VERSION 5.7 ;
BUSBITCHARS "[]" ;
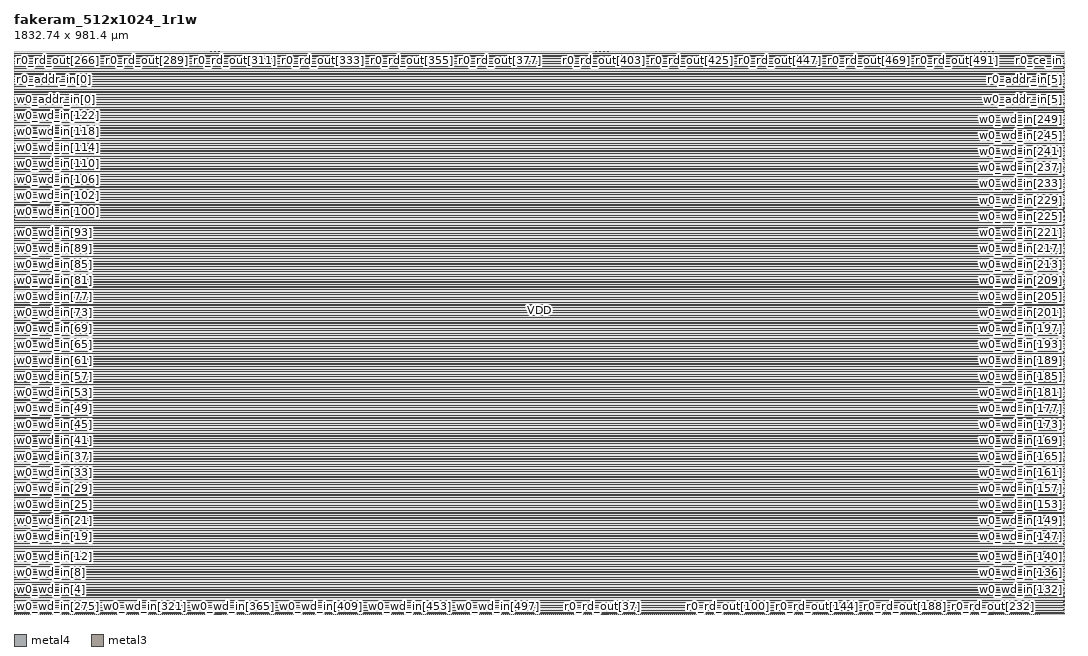
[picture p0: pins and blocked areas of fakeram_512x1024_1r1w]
MACRO fakeram_512x1024_1r1w
  FOREIGN fakeram_512x1024_1r1w 0 0 ;
  SYMMETRY X Y R90 ;
  SIZE 1832.740 BY 981.400 ;
  CLASS BLOCK ;
  PIN w0_wd_in[0]
    DIRECTION INPUT ;
    USE SIGNAL ;
    SHAPE ABUTMENT ;
    PORT
      LAYER metal4 ;
      RECT 0.000 1.645 0.210 1.715 ;
    END
  END w0_wd_in[0]
  PIN w0_wd_in[1]
    DIRECTION INPUT ;
    USE SIGNAL ;
    SHAPE ABUTMENT ;
    PORT
      LAYER metal4 ;
      RECT 0.000 8.645 0.210 8.715 ;
    END
  END w0_wd_in[1]
  PIN w0_wd_in[2]
    DIRECTION INPUT ;
    USE SIGNAL ;
    SHAPE ABUTMENT ;
    PORT
      LAYER metal4 ;
      RECT 0.000 15.645 0.210 15.715 ;
    END
  END w0_wd_in[2]
  PIN w0_wd_in[3]
    DIRECTION INPUT ;
    USE SIGNAL ;
    SHAPE ABUTMENT ;
    PORT
      LAYER metal4 ;
      RECT 0.000 22.645 0.210 22.715 ;
    END
  END w0_wd_in[3]
  PIN w0_wd_in[4]
    DIRECTION INPUT ;
    USE SIGNAL ;
    SHAPE ABUTMENT ;
    PORT
      LAYER metal4 ;
      RECT 0.000 29.645 0.210 29.715 ;
    END
  END w0_wd_in[4]
  PIN w0_wd_in[5]
    DIRECTION INPUT ;
    USE SIGNAL ;
    SHAPE ABUTMENT ;
    PORT
      LAYER metal4 ;
      RECT 0.000 36.645 0.210 36.715 ;
    END
  END w0_wd_in[5]
  PIN w0_wd_in[6]
    DIRECTION INPUT ;
    USE SIGNAL ;
    SHAPE ABUTMENT ;
    PORT
      LAYER metal4 ;
      RECT 0.000 43.645 0.210 43.715 ;
    END
  END w0_wd_in[6]
  PIN w0_wd_in[7]
    DIRECTION INPUT ;
    USE SIGNAL ;
    SHAPE ABUTMENT ;
    PORT
      LAYER metal4 ;
      RECT 0.000 50.645 0.210 50.715 ;
    END
  END w0_wd_in[7]
  PIN w0_wd_in[8]
    DIRECTION INPUT ;
    USE SIGNAL ;
    SHAPE ABUTMENT ;
    PORT
      LAYER metal4 ;
      RECT 0.000 57.645 0.210 57.715 ;
    END
  END w0_wd_in[8]
  PIN w0_wd_in[9]
    DIRECTION INPUT ;
    USE SIGNAL ;
    SHAPE ABUTMENT ;
    PORT
      LAYER metal4 ;
      RECT 0.000 64.645 0.210 64.715 ;
    END
  END w0_wd_in[9]
  PIN w0_wd_in[10]
    DIRECTION INPUT ;
    USE SIGNAL ;
    SHAPE ABUTMENT ;
    PORT
      LAYER metal4 ;
      RECT 0.000 71.645 0.210 71.715 ;
    END
  END w0_wd_in[10]
  PIN w0_wd_in[11]
    DIRECTION INPUT ;
    USE SIGNAL ;
    SHAPE ABUTMENT ;
    PORT
      LAYER metal4 ;
      RECT 0.000 78.645 0.210 78.715 ;
    END
  END w0_wd_in[11]
  PIN w0_wd_in[12]
    DIRECTION INPUT ;
    USE SIGNAL ;
    SHAPE ABUTMENT ;
    PORT
      LAYER metal4 ;
      RECT 0.000 85.645 0.210 85.715 ;
    END
  END w0_wd_in[12]
  PIN w0_wd_in[13]
    DIRECTION INPUT ;
    USE SIGNAL ;
    SHAPE ABUTMENT ;
    PORT
      LAYER metal4 ;
      RECT 0.000 92.645 0.210 92.715 ;
    END
  END w0_wd_in[13]
  PIN w0_wd_in[14]
    DIRECTION INPUT ;
    USE SIGNAL ;
    SHAPE ABUTMENT ;
    PORT
      LAYER metal4 ;
      RECT 0.000 99.645 0.210 99.715 ;
    END
  END w0_wd_in[14]
  PIN w0_wd_in[15]
    DIRECTION INPUT ;
    USE SIGNAL ;
    SHAPE ABUTMENT ;
    PORT
      LAYER metal4 ;
      RECT 0.000 106.645 0.210 106.715 ;
    END
  END w0_wd_in[15]
  PIN w0_wd_in[16]
    DIRECTION INPUT ;
    USE SIGNAL ;
    SHAPE ABUTMENT ;
    PORT
      LAYER metal4 ;
      RECT 0.000 113.645 0.210 113.715 ;
    END
  END w0_wd_in[16]
  PIN w0_wd_in[17]
    DIRECTION INPUT ;
    USE SIGNAL ;
    SHAPE ABUTMENT ;
    PORT
      LAYER metal4 ;
      RECT 0.000 120.645 0.210 120.715 ;
    END
  END w0_wd_in[17]
  PIN w0_wd_in[18]
    DIRECTION INPUT ;
    USE SIGNAL ;
    SHAPE ABUTMENT ;
    PORT
      LAYER metal4 ;
      RECT 0.000 127.645 0.210 127.715 ;
    END
  END w0_wd_in[18]
  PIN w0_wd_in[19]
    DIRECTION INPUT ;
    USE SIGNAL ;
    SHAPE ABUTMENT ;
    PORT
      LAYER metal4 ;
      RECT 0.000 134.645 0.210 134.715 ;
    END
  END w0_wd_in[19]
  PIN w0_wd_in[20]
    DIRECTION INPUT ;
    USE SIGNAL ;
    SHAPE ABUTMENT ;
    PORT
      LAYER metal4 ;
      RECT 0.000 141.645 0.210 141.715 ;
    END
  END w0_wd_in[20]
  PIN w0_wd_in[21]
    DIRECTION INPUT ;
    USE SIGNAL ;
    SHAPE ABUTMENT ;
    PORT
      LAYER metal4 ;
      RECT 0.000 148.645 0.210 148.715 ;
    END
  END w0_wd_in[21]
  PIN w0_wd_in[22]
    DIRECTION INPUT ;
    USE SIGNAL ;
    SHAPE ABUTMENT ;
    PORT
      LAYER metal4 ;
      RECT 0.000 155.645 0.210 155.715 ;
    END
  END w0_wd_in[22]
  PIN w0_wd_in[23]
    DIRECTION INPUT ;
    USE SIGNAL ;
    SHAPE ABUTMENT ;
    PORT
      LAYER metal4 ;
      RECT 0.000 162.645 0.210 162.715 ;
    END
  END w0_wd_in[23]
  PIN w0_wd_in[24]
    DIRECTION INPUT ;
    USE SIGNAL ;
    SHAPE ABUTMENT ;
    PORT
      LAYER metal4 ;
      RECT 0.000 169.645 0.210 169.715 ;
    END
  END w0_wd_in[24]
  PIN w0_wd_in[25]
    DIRECTION INPUT ;
    USE SIGNAL ;
    SHAPE ABUTMENT ;
    PORT
      LAYER metal4 ;
      RECT 0.000 176.645 0.210 176.715 ;
    END
  END w0_wd_in[25]
  PIN w0_wd_in[26]
    DIRECTION INPUT ;
    USE SIGNAL ;
    SHAPE ABUTMENT ;
    PORT
      LAYER metal4 ;
      RECT 0.000 183.645 0.210 183.715 ;
    END
  END w0_wd_in[26]
  PIN w0_wd_in[27]
    DIRECTION INPUT ;
    USE SIGNAL ;
    SHAPE ABUTMENT ;
    PORT
      LAYER metal4 ;
      RECT 0.000 190.645 0.210 190.715 ;
    END
  END w0_wd_in[27]
  PIN w0_wd_in[28]
    DIRECTION INPUT ;
    USE SIGNAL ;
    SHAPE ABUTMENT ;
    PORT
      LAYER metal4 ;
      RECT 0.000 197.645 0.210 197.715 ;
    END
  END w0_wd_in[28]
  PIN w0_wd_in[29]
    DIRECTION INPUT ;
    USE SIGNAL ;
    SHAPE ABUTMENT ;
    PORT
      LAYER metal4 ;
      RECT 0.000 204.645 0.210 204.715 ;
    END
  END w0_wd_in[29]
  PIN w0_wd_in[30]
    DIRECTION INPUT ;
    USE SIGNAL ;
    SHAPE ABUTMENT ;
    PORT
      LAYER metal4 ;
      RECT 0.000 211.645 0.210 211.715 ;
    END
  END w0_wd_in[30]
  PIN w0_wd_in[31]
    DIRECTION INPUT ;
    USE SIGNAL ;
    SHAPE ABUTMENT ;
    PORT
      LAYER metal4 ;
      RECT 0.000 218.645 0.210 218.715 ;
    END
  END w0_wd_in[31]
  PIN w0_wd_in[32]
    DIRECTION INPUT ;
    USE SIGNAL ;
    SHAPE ABUTMENT ;
    PORT
      LAYER metal4 ;
      RECT 0.000 225.645 0.210 225.715 ;
    END
  END w0_wd_in[32]
  PIN w0_wd_in[33]
    DIRECTION INPUT ;
    USE SIGNAL ;
    SHAPE ABUTMENT ;
    PORT
      LAYER metal4 ;
      RECT 0.000 232.645 0.210 232.715 ;
    END
  END w0_wd_in[33]
  PIN w0_wd_in[34]
    DIRECTION INPUT ;
    USE SIGNAL ;
    SHAPE ABUTMENT ;
    PORT
      LAYER metal4 ;
      RECT 0.000 239.645 0.210 239.715 ;
    END
  END w0_wd_in[34]
  PIN w0_wd_in[35]
    DIRECTION INPUT ;
    USE SIGNAL ;
    SHAPE ABUTMENT ;
    PORT
      LAYER metal4 ;
      RECT 0.000 246.645 0.210 246.715 ;
    END
  END w0_wd_in[35]
  PIN w0_wd_in[36]
    DIRECTION INPUT ;
    USE SIGNAL ;
    SHAPE ABUTMENT ;
    PORT
      LAYER metal4 ;
      RECT 0.000 253.645 0.210 253.715 ;
    END
  END w0_wd_in[36]
  PIN w0_wd_in[37]
    DIRECTION INPUT ;
    USE SIGNAL ;
    SHAPE ABUTMENT ;
    PORT
      LAYER metal4 ;
      RECT 0.000 260.645 0.210 260.715 ;
    END
  END w0_wd_in[37]
  PIN w0_wd_in[38]
    DIRECTION INPUT ;
    USE SIGNAL ;
    SHAPE ABUTMENT ;
    PORT
      LAYER metal4 ;
      RECT 0.000 267.645 0.210 267.715 ;
    END
  END w0_wd_in[38]
  PIN w0_wd_in[39]
    DIRECTION INPUT ;
    USE SIGNAL ;
    SHAPE ABUTMENT ;
    PORT
      LAYER metal4 ;
      RECT 0.000 274.645 0.210 274.715 ;
    END
  END w0_wd_in[39]
  PIN w0_wd_in[40]
    DIRECTION INPUT ;
    USE SIGNAL ;
    SHAPE ABUTMENT ;
    PORT
      LAYER metal4 ;
      RECT 0.000 281.645 0.210 281.715 ;
    END
  END w0_wd_in[40]
  PIN w0_wd_in[41]
    DIRECTION INPUT ;
    USE SIGNAL ;
    SHAPE ABUTMENT ;
    PORT
      LAYER metal4 ;
      RECT 0.000 288.645 0.210 288.715 ;
    END
  END w0_wd_in[41]
  PIN w0_wd_in[42]
    DIRECTION INPUT ;
    USE SIGNAL ;
    SHAPE ABUTMENT ;
    PORT
      LAYER metal4 ;
      RECT 0.000 295.645 0.210 295.715 ;
    END
  END w0_wd_in[42]
  PIN w0_wd_in[43]
    DIRECTION INPUT ;
    USE SIGNAL ;
    SHAPE ABUTMENT ;
    PORT
      LAYER metal4 ;
      RECT 0.000 302.645 0.210 302.715 ;
    END
  END w0_wd_in[43]
  PIN w0_wd_in[44]
    DIRECTION INPUT ;
    USE SIGNAL ;
    SHAPE ABUTMENT ;
    PORT
      LAYER metal4 ;
      RECT 0.000 309.645 0.210 309.715 ;
    END
  END w0_wd_in[44]
  PIN w0_wd_in[45]
    DIRECTION INPUT ;
    USE SIGNAL ;
    SHAPE ABUTMENT ;
    PORT
      LAYER metal4 ;
      RECT 0.000 316.645 0.210 316.715 ;
    END
  END w0_wd_in[45]
  PIN w0_wd_in[46]
    DIRECTION INPUT ;
    USE SIGNAL ;
    SHAPE ABUTMENT ;
    PORT
      LAYER metal4 ;
      RECT 0.000 323.645 0.210 323.715 ;
    END
  END w0_wd_in[46]
  PIN w0_wd_in[47]
    DIRECTION INPUT ;
    USE SIGNAL ;
    SHAPE ABUTMENT ;
    PORT
      LAYER metal4 ;
      RECT 0.000 330.645 0.210 330.715 ;
    END
  END w0_wd_in[47]
  PIN w0_wd_in[48]
    DIRECTION INPUT ;
    USE SIGNAL ;
    SHAPE ABUTMENT ;
    PORT
      LAYER metal4 ;
      RECT 0.000 337.645 0.210 337.715 ;
    END
  END w0_wd_in[48]
  PIN w0_wd_in[49]
    DIRECTION INPUT ;
    USE SIGNAL ;
    SHAPE ABUTMENT ;
    PORT
      LAYER metal4 ;
      RECT 0.000 344.645 0.210 344.715 ;
    END
  END w0_wd_in[49]
  PIN w0_wd_in[50]
    DIRECTION INPUT ;
    USE SIGNAL ;
    SHAPE ABUTMENT ;
    PORT
      LAYER metal4 ;
      RECT 0.000 351.645 0.210 351.715 ;
    END
  END w0_wd_in[50]
  PIN w0_wd_in[51]
    DIRECTION INPUT ;
    USE SIGNAL ;
    SHAPE ABUTMENT ;
    PORT
      LAYER metal4 ;
      RECT 0.000 358.645 0.210 358.715 ;
    END
  END w0_wd_in[51]
  PIN w0_wd_in[52]
    DIRECTION INPUT ;
    USE SIGNAL ;
    SHAPE ABUTMENT ;
    PORT
      LAYER metal4 ;
      RECT 0.000 365.645 0.210 365.715 ;
    END
  END w0_wd_in[52]
  PIN w0_wd_in[53]
    DIRECTION INPUT ;
    USE SIGNAL ;
    SHAPE ABUTMENT ;
    PORT
      LAYER metal4 ;
      RECT 0.000 372.645 0.210 372.715 ;
    END
  END w0_wd_in[53]
  PIN w0_wd_in[54]
    DIRECTION INPUT ;
    USE SIGNAL ;
    SHAPE ABUTMENT ;
    PORT
      LAYER metal4 ;
      RECT 0.000 379.645 0.210 379.715 ;
    END
  END w0_wd_in[54]
  PIN w0_wd_in[55]
    DIRECTION INPUT ;
    USE SIGNAL ;
    SHAPE ABUTMENT ;
    PORT
      LAYER metal4 ;
      RECT 0.000 386.645 0.210 386.715 ;
    END
  END w0_wd_in[55]
  PIN w0_wd_in[56]
    DIRECTION INPUT ;
    USE SIGNAL ;
    SHAPE ABUTMENT ;
    PORT
      LAYER metal4 ;
      RECT 0.000 393.645 0.210 393.715 ;
    END
  END w0_wd_in[56]
  PIN w0_wd_in[57]
    DIRECTION INPUT ;
    USE SIGNAL ;
    SHAPE ABUTMENT ;
    PORT
      LAYER metal4 ;
      RECT 0.000 400.645 0.210 400.715 ;
    END
  END w0_wd_in[57]
  PIN w0_wd_in[58]
    DIRECTION INPUT ;
    USE SIGNAL ;
    SHAPE ABUTMENT ;
    PORT
      LAYER metal4 ;
      RECT 0.000 407.645 0.210 407.715 ;
    END
  END w0_wd_in[58]
  PIN w0_wd_in[59]
    DIRECTION INPUT ;
    USE SIGNAL ;
    SHAPE ABUTMENT ;
    PORT
      LAYER metal4 ;
      RECT 0.000 414.645 0.210 414.715 ;
    END
  END w0_wd_in[59]
  PIN w0_wd_in[60]
    DIRECTION INPUT ;
    USE SIGNAL ;
    SHAPE ABUTMENT ;
    PORT
      LAYER metal4 ;
      RECT 0.000 421.645 0.210 421.715 ;
    END
  END w0_wd_in[60]
  PIN w0_wd_in[61]
    DIRECTION INPUT ;
    USE SIGNAL ;
    SHAPE ABUTMENT ;
    PORT
      LAYER metal4 ;
      RECT 0.000 428.645 0.210 428.715 ;
    END
  END w0_wd_in[61]
  PIN w0_wd_in[62]
    DIRECTION INPUT ;
    USE SIGNAL ;
    SHAPE ABUTMENT ;
    PORT
      LAYER metal4 ;
      RECT 0.000 435.645 0.210 435.715 ;
    END
  END w0_wd_in[62]
  PIN w0_wd_in[63]
    DIRECTION INPUT ;
    USE SIGNAL ;
    SHAPE ABUTMENT ;
    PORT
      LAYER metal4 ;
      RECT 0.000 442.645 0.210 442.715 ;
    END
  END w0_wd_in[63]
  PIN w0_wd_in[64]
    DIRECTION INPUT ;
    USE SIGNAL ;
    SHAPE ABUTMENT ;
    PORT
      LAYER metal4 ;
      RECT 0.000 449.645 0.210 449.715 ;
    END
  END w0_wd_in[64]
  PIN w0_wd_in[65]
    DIRECTION INPUT ;
    USE SIGNAL ;
    SHAPE ABUTMENT ;
    PORT
      LAYER metal4 ;
      RECT 0.000 456.645 0.210 456.715 ;
    END
  END w0_wd_in[65]
  PIN w0_wd_in[66]
    DIRECTION INPUT ;
    USE SIGNAL ;
    SHAPE ABUTMENT ;
    PORT
      LAYER metal4 ;
      RECT 0.000 463.645 0.210 463.715 ;
    END
  END w0_wd_in[66]
  PIN w0_wd_in[67]
    DIRECTION INPUT ;
    USE SIGNAL ;
    SHAPE ABUTMENT ;
    PORT
      LAYER metal4 ;
      RECT 0.000 470.645 0.210 470.715 ;
    END
  END w0_wd_in[67]
  PIN w0_wd_in[68]
    DIRECTION INPUT ;
    USE SIGNAL ;
    SHAPE ABUTMENT ;
    PORT
      LAYER metal4 ;
      RECT 0.000 477.645 0.210 477.715 ;
    END
  END w0_wd_in[68]
  PIN w0_wd_in[69]
    DIRECTION INPUT ;
    USE SIGNAL ;
    SHAPE ABUTMENT ;
    PORT
      LAYER metal4 ;
      RECT 0.000 484.645 0.210 484.715 ;
    END
  END w0_wd_in[69]
  PIN w0_wd_in[70]
    DIRECTION INPUT ;
    USE SIGNAL ;
    SHAPE ABUTMENT ;
    PORT
      LAYER metal4 ;
      RECT 0.000 491.645 0.210 491.715 ;
    END
  END w0_wd_in[70]
  PIN w0_wd_in[71]
    DIRECTION INPUT ;
    USE SIGNAL ;
    SHAPE ABUTMENT ;
    PORT
      LAYER metal4 ;
      RECT 0.000 498.645 0.210 498.715 ;
    END
  END w0_wd_in[71]
  PIN w0_wd_in[72]
    DIRECTION INPUT ;
    USE SIGNAL ;
    SHAPE ABUTMENT ;
    PORT
      LAYER metal4 ;
      RECT 0.000 505.645 0.210 505.715 ;
    END
  END w0_wd_in[72]
  PIN w0_wd_in[73]
    DIRECTION INPUT ;
    USE SIGNAL ;
    SHAPE ABUTMENT ;
    PORT
      LAYER metal4 ;
      RECT 0.000 512.645 0.210 512.715 ;
    END
  END w0_wd_in[73]
  PIN w0_wd_in[74]
    DIRECTION INPUT ;
    USE SIGNAL ;
    SHAPE ABUTMENT ;
    PORT
      LAYER metal4 ;
      RECT 0.000 519.645 0.210 519.715 ;
    END
  END w0_wd_in[74]
  PIN w0_wd_in[75]
    DIRECTION INPUT ;
    USE SIGNAL ;
    SHAPE ABUTMENT ;
    PORT
      LAYER metal4 ;
      RECT 0.000 526.645 0.210 526.715 ;
    END
  END w0_wd_in[75]
  PIN w0_wd_in[76]
    DIRECTION INPUT ;
    USE SIGNAL ;
    SHAPE ABUTMENT ;
    PORT
      LAYER metal4 ;
      RECT 0.000 533.645 0.210 533.715 ;
    END
  END w0_wd_in[76]
  PIN w0_wd_in[77]
    DIRECTION INPUT ;
    USE SIGNAL ;
    SHAPE ABUTMENT ;
    PORT
      LAYER metal4 ;
      RECT 0.000 540.645 0.210 540.715 ;
    END
  END w0_wd_in[77]
  PIN w0_wd_in[78]
    DIRECTION INPUT ;
    USE SIGNAL ;
    SHAPE ABUTMENT ;
    PORT
      LAYER metal4 ;
      RECT 0.000 547.645 0.210 547.715 ;
    END
  END w0_wd_in[78]
  PIN w0_wd_in[79]
    DIRECTION INPUT ;
    USE SIGNAL ;
    SHAPE ABUTMENT ;
    PORT
      LAYER metal4 ;
      RECT 0.000 554.645 0.210 554.715 ;
    END
  END w0_wd_in[79]
  PIN w0_wd_in[80]
    DIRECTION INPUT ;
    USE SIGNAL ;
    SHAPE ABUTMENT ;
    PORT
      LAYER metal4 ;
      RECT 0.000 561.645 0.210 561.715 ;
    END
  END w0_wd_in[80]
  PIN w0_wd_in[81]
    DIRECTION INPUT ;
    USE SIGNAL ;
    SHAPE ABUTMENT ;
    PORT
      LAYER metal4 ;
      RECT 0.000 568.645 0.210 568.715 ;
    END
  END w0_wd_in[81]
  PIN w0_wd_in[82]
    DIRECTION INPUT ;
    USE SIGNAL ;
    SHAPE ABUTMENT ;
    PORT
      LAYER metal4 ;
      RECT 0.000 575.645 0.210 575.715 ;
    END
  END w0_wd_in[82]
  PIN w0_wd_in[83]
    DIRECTION INPUT ;
    USE SIGNAL ;
    SHAPE ABUTMENT ;
    PORT
      LAYER metal4 ;
      RECT 0.000 582.645 0.210 582.715 ;
    END
  END w0_wd_in[83]
  PIN w0_wd_in[84]
    DIRECTION INPUT ;
    USE SIGNAL ;
    SHAPE ABUTMENT ;
    PORT
      LAYER metal4 ;
      RECT 0.000 589.645 0.210 589.715 ;
    END
  END w0_wd_in[84]
  PIN w0_wd_in[85]
    DIRECTION INPUT ;
    USE SIGNAL ;
    SHAPE ABUTMENT ;
    PORT
      LAYER metal4 ;
      RECT 0.000 596.645 0.210 596.715 ;
    END
  END w0_wd_in[85]
  PIN w0_wd_in[86]
    DIRECTION INPUT ;
    USE SIGNAL ;
    SHAPE ABUTMENT ;
    PORT
      LAYER metal4 ;
      RECT 0.000 603.645 0.210 603.715 ;
    END
  END w0_wd_in[86]
  PIN w0_wd_in[87]
    DIRECTION INPUT ;
    USE SIGNAL ;
    SHAPE ABUTMENT ;
    PORT
      LAYER metal4 ;
      RECT 0.000 610.645 0.210 610.715 ;
    END
  END w0_wd_in[87]
  PIN w0_wd_in[88]
    DIRECTION INPUT ;
    USE SIGNAL ;
    SHAPE ABUTMENT ;
    PORT
      LAYER metal4 ;
      RECT 0.000 617.645 0.210 617.715 ;
    END
  END w0_wd_in[88]
  PIN w0_wd_in[89]
    DIRECTION INPUT ;
    USE SIGNAL ;
    SHAPE ABUTMENT ;
    PORT
      LAYER metal4 ;
      RECT 0.000 624.645 0.210 624.715 ;
    END
  END w0_wd_in[89]
  PIN w0_wd_in[90]
    DIRECTION INPUT ;
    USE SIGNAL ;
    SHAPE ABUTMENT ;
    PORT
      LAYER metal4 ;
      RECT 0.000 631.645 0.210 631.715 ;
    END
  END w0_wd_in[90]
  PIN w0_wd_in[91]
    DIRECTION INPUT ;
    USE SIGNAL ;
    SHAPE ABUTMENT ;
    PORT
      LAYER metal4 ;
      RECT 0.000 638.645 0.210 638.715 ;
    END
  END w0_wd_in[91]
  PIN w0_wd_in[92]
    DIRECTION INPUT ;
    USE SIGNAL ;
    SHAPE ABUTMENT ;
    PORT
      LAYER metal4 ;
      RECT 0.000 645.645 0.210 645.715 ;
    END
  END w0_wd_in[92]
  PIN w0_wd_in[93]
    DIRECTION INPUT ;
    USE SIGNAL ;
    SHAPE ABUTMENT ;
    PORT
      LAYER metal4 ;
      RECT 0.000 652.645 0.210 652.715 ;
    END
  END w0_wd_in[93]
  PIN w0_wd_in[94]
    DIRECTION INPUT ;
    USE SIGNAL ;
    SHAPE ABUTMENT ;
    PORT
      LAYER metal4 ;
      RECT 0.000 659.645 0.210 659.715 ;
    END
  END w0_wd_in[94]
  PIN w0_wd_in[95]
    DIRECTION INPUT ;
    USE SIGNAL ;
    SHAPE ABUTMENT ;
    PORT
      LAYER metal4 ;
      RECT 0.000 666.645 0.210 666.715 ;
    END
  END w0_wd_in[95]
  PIN w0_wd_in[96]
    DIRECTION INPUT ;
    USE SIGNAL ;
    SHAPE ABUTMENT ;
    PORT
      LAYER metal4 ;
      RECT 0.000 673.645 0.210 673.715 ;
    END
  END w0_wd_in[96]
  PIN w0_wd_in[97]
    DIRECTION INPUT ;
    USE SIGNAL ;
    SHAPE ABUTMENT ;
    PORT
      LAYER metal4 ;
      RECT 0.000 680.645 0.210 680.715 ;
    END
  END w0_wd_in[97]
  PIN w0_wd_in[98]
    DIRECTION INPUT ;
    USE SIGNAL ;
    SHAPE ABUTMENT ;
    PORT
      LAYER metal4 ;
      RECT 0.000 687.645 0.210 687.715 ;
    END
  END w0_wd_in[98]
  PIN w0_wd_in[99]
    DIRECTION INPUT ;
    USE SIGNAL ;
    SHAPE ABUTMENT ;
    PORT
      LAYER metal4 ;
      RECT 0.000 694.645 0.210 694.715 ;
    END
  END w0_wd_in[99]
  PIN w0_wd_in[100]
    DIRECTION INPUT ;
    USE SIGNAL ;
    SHAPE ABUTMENT ;
    PORT
      LAYER metal4 ;
      RECT 0.000 701.645 0.210 701.715 ;
    END
  END w0_wd_in[100]
  PIN w0_wd_in[101]
    DIRECTION INPUT ;
    USE SIGNAL ;
    SHAPE ABUTMENT ;
    PORT
      LAYER metal4 ;
      RECT 0.000 708.645 0.210 708.715 ;
    END
  END w0_wd_in[101]
  PIN w0_wd_in[102]
    DIRECTION INPUT ;
    USE SIGNAL ;
    SHAPE ABUTMENT ;
    PORT
      LAYER metal4 ;
      RECT 0.000 715.645 0.210 715.715 ;
    END
  END w0_wd_in[102]
  PIN w0_wd_in[103]
    DIRECTION INPUT ;
    USE SIGNAL ;
    SHAPE ABUTMENT ;
    PORT
      LAYER metal4 ;
      RECT 0.000 722.645 0.210 722.715 ;
    END
  END w0_wd_in[103]
  PIN w0_wd_in[104]
    DIRECTION INPUT ;
    USE SIGNAL ;
    SHAPE ABUTMENT ;
    PORT
      LAYER metal4 ;
      RECT 0.000 729.645 0.210 729.715 ;
    END
  END w0_wd_in[104]
  PIN w0_wd_in[105]
    DIRECTION INPUT ;
    USE SIGNAL ;
    SHAPE ABUTMENT ;
    PORT
      LAYER metal4 ;
      RECT 0.000 736.645 0.210 736.715 ;
    END
  END w0_wd_in[105]
  PIN w0_wd_in[106]
    DIRECTION INPUT ;
    USE SIGNAL ;
    SHAPE ABUTMENT ;
    PORT
      LAYER metal4 ;
      RECT 0.000 743.645 0.210 743.715 ;
    END
  END w0_wd_in[106]
  PIN w0_wd_in[107]
    DIRECTION INPUT ;
    USE SIGNAL ;
    SHAPE ABUTMENT ;
    PORT
      LAYER metal4 ;
      RECT 0.000 750.645 0.210 750.715 ;
    END
  END w0_wd_in[107]
  PIN w0_wd_in[108]
    DIRECTION INPUT ;
    USE SIGNAL ;
    SHAPE ABUTMENT ;
    PORT
      LAYER metal4 ;
      RECT 0.000 757.645 0.210 757.715 ;
    END
  END w0_wd_in[108]
  PIN w0_wd_in[109]
    DIRECTION INPUT ;
    USE SIGNAL ;
    SHAPE ABUTMENT ;
    PORT
      LAYER metal4 ;
      RECT 0.000 764.645 0.210 764.715 ;
    END
  END w0_wd_in[109]
  PIN w0_wd_in[110]
    DIRECTION INPUT ;
    USE SIGNAL ;
    SHAPE ABUTMENT ;
    PORT
      LAYER metal4 ;
      RECT 0.000 771.645 0.210 771.715 ;
    END
  END w0_wd_in[110]
  PIN w0_wd_in[111]
    DIRECTION INPUT ;
    USE SIGNAL ;
    SHAPE ABUTMENT ;
    PORT
      LAYER metal4 ;
      RECT 0.000 778.645 0.210 778.715 ;
    END
  END w0_wd_in[111]
  PIN w0_wd_in[112]
    DIRECTION INPUT ;
    USE SIGNAL ;
    SHAPE ABUTMENT ;
    PORT
      LAYER metal4 ;
      RECT 0.000 785.645 0.210 785.715 ;
    END
  END w0_wd_in[112]
  PIN w0_wd_in[113]
    DIRECTION INPUT ;
    USE SIGNAL ;
    SHAPE ABUTMENT ;
    PORT
      LAYER metal4 ;
      RECT 0.000 792.645 0.210 792.715 ;
    END
  END w0_wd_in[113]
  PIN w0_wd_in[114]
    DIRECTION INPUT ;
    USE SIGNAL ;
    SHAPE ABUTMENT ;
    PORT
      LAYER metal4 ;
      RECT 0.000 799.645 0.210 799.715 ;
    END
  END w0_wd_in[114]
  PIN w0_wd_in[115]
    DIRECTION INPUT ;
    USE SIGNAL ;
    SHAPE ABUTMENT ;
    PORT
      LAYER metal4 ;
      RECT 0.000 806.645 0.210 806.715 ;
    END
  END w0_wd_in[115]
  PIN w0_wd_in[116]
    DIRECTION INPUT ;
    USE SIGNAL ;
    SHAPE ABUTMENT ;
    PORT
      LAYER metal4 ;
      RECT 0.000 813.645 0.210 813.715 ;
    END
  END w0_wd_in[116]
  PIN w0_wd_in[117]
    DIRECTION INPUT ;
    USE SIGNAL ;
    SHAPE ABUTMENT ;
    PORT
      LAYER metal4 ;
      RECT 0.000 820.645 0.210 820.715 ;
    END
  END w0_wd_in[117]
  PIN w0_wd_in[118]
    DIRECTION INPUT ;
    USE SIGNAL ;
    SHAPE ABUTMENT ;
    PORT
      LAYER metal4 ;
      RECT 0.000 827.645 0.210 827.715 ;
    END
  END w0_wd_in[118]
  PIN w0_wd_in[119]
    DIRECTION INPUT ;
    USE SIGNAL ;
    SHAPE ABUTMENT ;
    PORT
      LAYER metal4 ;
      RECT 0.000 834.645 0.210 834.715 ;
    END
  END w0_wd_in[119]
  PIN w0_wd_in[120]
    DIRECTION INPUT ;
    USE SIGNAL ;
    SHAPE ABUTMENT ;
    PORT
      LAYER metal4 ;
      RECT 0.000 841.645 0.210 841.715 ;
    END
  END w0_wd_in[120]
  PIN w0_wd_in[121]
    DIRECTION INPUT ;
    USE SIGNAL ;
    SHAPE ABUTMENT ;
    PORT
      LAYER metal4 ;
      RECT 0.000 848.645 0.210 848.715 ;
    END
  END w0_wd_in[121]
  PIN w0_wd_in[122]
    DIRECTION INPUT ;
    USE SIGNAL ;
    SHAPE ABUTMENT ;
    PORT
      LAYER metal4 ;
      RECT 0.000 855.645 0.210 855.715 ;
    END
  END w0_wd_in[122]
  PIN w0_wd_in[123]
    DIRECTION INPUT ;
    USE SIGNAL ;
    SHAPE ABUTMENT ;
    PORT
      LAYER metal4 ;
      RECT 0.000 862.645 0.210 862.715 ;
    END
  END w0_wd_in[123]
  PIN w0_wd_in[124]
    DIRECTION INPUT ;
    USE SIGNAL ;
    SHAPE ABUTMENT ;
    PORT
      LAYER metal4 ;
      RECT 0.000 869.645 0.210 869.715 ;
    END
  END w0_wd_in[124]
  PIN w0_wd_in[125]
    DIRECTION INPUT ;
    USE SIGNAL ;
    SHAPE ABUTMENT ;
    PORT
      LAYER metal4 ;
      RECT 0.000 876.645 0.210 876.715 ;
    END
  END w0_wd_in[125]
  PIN w0_wd_in[126]
    DIRECTION INPUT ;
    USE SIGNAL ;
    SHAPE ABUTMENT ;
    PORT
      LAYER metal4 ;
      RECT 0.000 883.645 0.210 883.715 ;
    END
  END w0_wd_in[126]
  PIN w0_wd_in[127]
    DIRECTION INPUT ;
    USE SIGNAL ;
    SHAPE ABUTMENT ;
    PORT
      LAYER metal4 ;
      RECT 0.000 890.645 0.210 890.715 ;
    END
  END w0_wd_in[127]
  PIN w0_wd_in[128]
    DIRECTION INPUT ;
    USE SIGNAL ;
    SHAPE ABUTMENT ;
    PORT
      LAYER metal4 ;
      RECT 1832.530 1.645 1832.740 1.715 ;
    END
  END w0_wd_in[128]
  PIN w0_wd_in[129]
    DIRECTION INPUT ;
    USE SIGNAL ;
    SHAPE ABUTMENT ;
    PORT
      LAYER metal4 ;
      RECT 1832.530 8.645 1832.740 8.715 ;
    END
  END w0_wd_in[129]
  PIN w0_wd_in[130]
    DIRECTION INPUT ;
    USE SIGNAL ;
    SHAPE ABUTMENT ;
    PORT
      LAYER metal4 ;
      RECT 1832.530 15.645 1832.740 15.715 ;
    END
  END w0_wd_in[130]
  PIN w0_wd_in[131]
    DIRECTION INPUT ;
    USE SIGNAL ;
    SHAPE ABUTMENT ;
    PORT
      LAYER metal4 ;
      RECT 1832.530 22.645 1832.740 22.715 ;
    END
  END w0_wd_in[131]
  PIN w0_wd_in[132]
    DIRECTION INPUT ;
    USE SIGNAL ;
    SHAPE ABUTMENT ;
    PORT
      LAYER metal4 ;
      RECT 1832.530 29.645 1832.740 29.715 ;
    END
  END w0_wd_in[132]
  PIN w0_wd_in[133]
    DIRECTION INPUT ;
    USE SIGNAL ;
    SHAPE ABUTMENT ;
    PORT
      LAYER metal4 ;
      RECT 1832.530 36.645 1832.740 36.715 ;
    END
  END w0_wd_in[133]
  PIN w0_wd_in[134]
    DIRECTION INPUT ;
    USE SIGNAL ;
    SHAPE ABUTMENT ;
    PORT
      LAYER metal4 ;
      RECT 1832.530 43.645 1832.740 43.715 ;
    END
  END w0_wd_in[134]
  PIN w0_wd_in[135]
    DIRECTION INPUT ;
    USE SIGNAL ;
    SHAPE ABUTMENT ;
    PORT
      LAYER metal4 ;
      RECT 1832.530 50.645 1832.740 50.715 ;
    END
  END w0_wd_in[135]
  PIN w0_wd_in[136]
    DIRECTION INPUT ;
    USE SIGNAL ;
    SHAPE ABUTMENT ;
    PORT
      LAYER metal4 ;
      RECT 1832.530 57.645 1832.740 57.715 ;
    END
  END w0_wd_in[136]
  PIN w0_wd_in[137]
    DIRECTION INPUT ;
    USE SIGNAL ;
    SHAPE ABUTMENT ;
    PORT
      LAYER metal4 ;
      RECT 1832.530 64.645 1832.740 64.715 ;
    END
  END w0_wd_in[137]
  PIN w0_wd_in[138]
    DIRECTION INPUT ;
    USE SIGNAL ;
    SHAPE ABUTMENT ;
    PORT
      LAYER metal4 ;
      RECT 1832.530 71.645 1832.740 71.715 ;
    END
  END w0_wd_in[138]
  PIN w0_wd_in[139]
    DIRECTION INPUT ;
    USE SIGNAL ;
    SHAPE ABUTMENT ;
    PORT
      LAYER metal4 ;
      RECT 1832.530 78.645 1832.740 78.715 ;
    END
  END w0_wd_in[139]
  PIN w0_wd_in[140]
    DIRECTION INPUT ;
    USE SIGNAL ;
    SHAPE ABUTMENT ;
    PORT
      LAYER metal4 ;
      RECT 1832.530 85.645 1832.740 85.715 ;
    END
  END w0_wd_in[140]
  PIN w0_wd_in[141]
    DIRECTION INPUT ;
    USE SIGNAL ;
    SHAPE ABUTMENT ;
    PORT
      LAYER metal4 ;
      RECT 1832.530 92.645 1832.740 92.715 ;
    END
  END w0_wd_in[141]
  PIN w0_wd_in[142]
    DIRECTION INPUT ;
    USE SIGNAL ;
    SHAPE ABUTMENT ;
    PORT
      LAYER metal4 ;
      RECT 1832.530 99.645 1832.740 99.715 ;
    END
  END w0_wd_in[142]
  PIN w0_wd_in[143]
    DIRECTION INPUT ;
    USE SIGNAL ;
    SHAPE ABUTMENT ;
    PORT
      LAYER metal4 ;
      RECT 1832.530 106.645 1832.740 106.715 ;
    END
  END w0_wd_in[143]
  PIN w0_wd_in[144]
    DIRECTION INPUT ;
    USE SIGNAL ;
    SHAPE ABUTMENT ;
    PORT
      LAYER metal4 ;
      RECT 1832.530 113.645 1832.740 113.715 ;
    END
  END w0_wd_in[144]
  PIN w0_wd_in[145]
    DIRECTION INPUT ;
    USE SIGNAL ;
    SHAPE ABUTMENT ;
    PORT
      LAYER metal4 ;
      RECT 1832.530 120.645 1832.740 120.715 ;
    END
  END w0_wd_in[145]
  PIN w0_wd_in[146]
    DIRECTION INPUT ;
    USE SIGNAL ;
    SHAPE ABUTMENT ;
    PORT
      LAYER metal4 ;
      RECT 1832.530 127.645 1832.740 127.715 ;
    END
  END w0_wd_in[146]
  PIN w0_wd_in[147]
    DIRECTION INPUT ;
    USE SIGNAL ;
    SHAPE ABUTMENT ;
    PORT
      LAYER metal4 ;
      RECT 1832.530 134.645 1832.740 134.715 ;
    END
  END w0_wd_in[147]
  PIN w0_wd_in[148]
    DIRECTION INPUT ;
    USE SIGNAL ;
    SHAPE ABUTMENT ;
    PORT
      LAYER metal4 ;
      RECT 1832.530 141.645 1832.740 141.715 ;
    END
  END w0_wd_in[148]
  PIN w0_wd_in[149]
    DIRECTION INPUT ;
    USE SIGNAL ;
    SHAPE ABUTMENT ;
    PORT
      LAYER metal4 ;
      RECT 1832.530 148.645 1832.740 148.715 ;
    END
  END w0_wd_in[149]
  PIN w0_wd_in[150]
    DIRECTION INPUT ;
    USE SIGNAL ;
    SHAPE ABUTMENT ;
    PORT
      LAYER metal4 ;
      RECT 1832.530 155.645 1832.740 155.715 ;
    END
  END w0_wd_in[150]
  PIN w0_wd_in[151]
    DIRECTION INPUT ;
    USE SIGNAL ;
    SHAPE ABUTMENT ;
    PORT
      LAYER metal4 ;
      RECT 1832.530 162.645 1832.740 162.715 ;
    END
  END w0_wd_in[151]
  PIN w0_wd_in[152]
    DIRECTION INPUT ;
    USE SIGNAL ;
    SHAPE ABUTMENT ;
    PORT
      LAYER metal4 ;
      RECT 1832.530 169.645 1832.740 169.715 ;
    END
  END w0_wd_in[152]
  PIN w0_wd_in[153]
    DIRECTION INPUT ;
    USE SIGNAL ;
    SHAPE ABUTMENT ;
    PORT
      LAYER metal4 ;
      RECT 1832.530 176.645 1832.740 176.715 ;
    END
  END w0_wd_in[153]
  PIN w0_wd_in[154]
    DIRECTION INPUT ;
    USE SIGNAL ;
    SHAPE ABUTMENT ;
    PORT
      LAYER metal4 ;
      RECT 1832.530 183.645 1832.740 183.715 ;
    END
  END w0_wd_in[154]
  PIN w0_wd_in[155]
    DIRECTION INPUT ;
    USE SIGNAL ;
    SHAPE ABUTMENT ;
    PORT
      LAYER metal4 ;
      RECT 1832.530 190.645 1832.740 190.715 ;
    END
  END w0_wd_in[155]
  PIN w0_wd_in[156]
    DIRECTION INPUT ;
    USE SIGNAL ;
    SHAPE ABUTMENT ;
    PORT
      LAYER metal4 ;
      RECT 1832.530 197.645 1832.740 197.715 ;
    END
  END w0_wd_in[156]
  PIN w0_wd_in[157]
    DIRECTION INPUT ;
    USE SIGNAL ;
    SHAPE ABUTMENT ;
    PORT
      LAYER metal4 ;
      RECT 1832.530 204.645 1832.740 204.715 ;
    END
  END w0_wd_in[157]
  PIN w0_wd_in[158]
    DIRECTION INPUT ;
    USE SIGNAL ;
    SHAPE ABUTMENT ;
    PORT
      LAYER metal4 ;
      RECT 1832.530 211.645 1832.740 211.715 ;
    END
  END w0_wd_in[158]
  PIN w0_wd_in[159]
    DIRECTION INPUT ;
    USE SIGNAL ;
    SHAPE ABUTMENT ;
    PORT
      LAYER metal4 ;
      RECT 1832.530 218.645 1832.740 218.715 ;
    END
  END w0_wd_in[159]
  PIN w0_wd_in[160]
    DIRECTION INPUT ;
    USE SIGNAL ;
    SHAPE ABUTMENT ;
    PORT
      LAYER metal4 ;
      RECT 1832.530 225.645 1832.740 225.715 ;
    END
  END w0_wd_in[160]
  PIN w0_wd_in[161]
    DIRECTION INPUT ;
    USE SIGNAL ;
    SHAPE ABUTMENT ;
    PORT
      LAYER metal4 ;
      RECT 1832.530 232.645 1832.740 232.715 ;
    END
  END w0_wd_in[161]
  PIN w0_wd_in[162]
    DIRECTION INPUT ;
    USE SIGNAL ;
    SHAPE ABUTMENT ;
    PORT
      LAYER metal4 ;
      RECT 1832.530 239.645 1832.740 239.715 ;
    END
  END w0_wd_in[162]
  PIN w0_wd_in[163]
    DIRECTION INPUT ;
    USE SIGNAL ;
    SHAPE ABUTMENT ;
    PORT
      LAYER metal4 ;
      RECT 1832.530 246.645 1832.740 246.715 ;
    END
  END w0_wd_in[163]
  PIN w0_wd_in[164]
    DIRECTION INPUT ;
    USE SIGNAL ;
    SHAPE ABUTMENT ;
    PORT
      LAYER metal4 ;
      RECT 1832.530 253.645 1832.740 253.715 ;
    END
  END w0_wd_in[164]
  PIN w0_wd_in[165]
    DIRECTION INPUT ;
    USE SIGNAL ;
    SHAPE ABUTMENT ;
    PORT
      LAYER metal4 ;
      RECT 1832.530 260.645 1832.740 260.715 ;
    END
  END w0_wd_in[165]
  PIN w0_wd_in[166]
    DIRECTION INPUT ;
    USE SIGNAL ;
    SHAPE ABUTMENT ;
    PORT
      LAYER metal4 ;
      RECT 1832.530 267.645 1832.740 267.715 ;
    END
  END w0_wd_in[166]
  PIN w0_wd_in[167]
    DIRECTION INPUT ;
    USE SIGNAL ;
    SHAPE ABUTMENT ;
    PORT
      LAYER metal4 ;
      RECT 1832.530 274.645 1832.740 274.715 ;
    END
  END w0_wd_in[167]
  PIN w0_wd_in[168]
    DIRECTION INPUT ;
    USE SIGNAL ;
    SHAPE ABUTMENT ;
    PORT
      LAYER metal4 ;
      RECT 1832.530 281.645 1832.740 281.715 ;
    END
  END w0_wd_in[168]
  PIN w0_wd_in[169]
    DIRECTION INPUT ;
    USE SIGNAL ;
    SHAPE ABUTMENT ;
    PORT
      LAYER metal4 ;
      RECT 1832.530 288.645 1832.740 288.715 ;
    END
  END w0_wd_in[169]
  PIN w0_wd_in[170]
    DIRECTION INPUT ;
    USE SIGNAL ;
    SHAPE ABUTMENT ;
    PORT
      LAYER metal4 ;
      RECT 1832.530 295.645 1832.740 295.715 ;
    END
  END w0_wd_in[170]
  PIN w0_wd_in[171]
    DIRECTION INPUT ;
    USE SIGNAL ;
    SHAPE ABUTMENT ;
    PORT
      LAYER metal4 ;
      RECT 1832.530 302.645 1832.740 302.715 ;
    END
  END w0_wd_in[171]
  PIN w0_wd_in[172]
    DIRECTION INPUT ;
    USE SIGNAL ;
    SHAPE ABUTMENT ;
    PORT
      LAYER metal4 ;
      RECT 1832.530 309.645 1832.740 309.715 ;
    END
  END w0_wd_in[172]
  PIN w0_wd_in[173]
    DIRECTION INPUT ;
    USE SIGNAL ;
    SHAPE ABUTMENT ;
    PORT
      LAYER metal4 ;
      RECT 1832.530 316.645 1832.740 316.715 ;
    END
  END w0_wd_in[173]
  PIN w0_wd_in[174]
    DIRECTION INPUT ;
    USE SIGNAL ;
    SHAPE ABUTMENT ;
    PORT
      LAYER metal4 ;
      RECT 1832.530 323.645 1832.740 323.715 ;
    END
  END w0_wd_in[174]
  PIN w0_wd_in[175]
    DIRECTION INPUT ;
    USE SIGNAL ;
    SHAPE ABUTMENT ;
    PORT
      LAYER metal4 ;
      RECT 1832.530 330.645 1832.740 330.715 ;
    END
  END w0_wd_in[175]
  PIN w0_wd_in[176]
    DIRECTION INPUT ;
    USE SIGNAL ;
    SHAPE ABUTMENT ;
    PORT
      LAYER metal4 ;
      RECT 1832.530 337.645 1832.740 337.715 ;
    END
  END w0_wd_in[176]
  PIN w0_wd_in[177]
    DIRECTION INPUT ;
    USE SIGNAL ;
    SHAPE ABUTMENT ;
    PORT
      LAYER metal4 ;
      RECT 1832.530 344.645 1832.740 344.715 ;
    END
  END w0_wd_in[177]
  PIN w0_wd_in[178]
    DIRECTION INPUT ;
    USE SIGNAL ;
    SHAPE ABUTMENT ;
    PORT
      LAYER metal4 ;
      RECT 1832.530 351.645 1832.740 351.715 ;
    END
  END w0_wd_in[178]
  PIN w0_wd_in[179]
    DIRECTION INPUT ;
    USE SIGNAL ;
    SHAPE ABUTMENT ;
    PORT
      LAYER metal4 ;
      RECT 1832.530 358.645 1832.740 358.715 ;
    END
  END w0_wd_in[179]
  PIN w0_wd_in[180]
    DIRECTION INPUT ;
    USE SIGNAL ;
    SHAPE ABUTMENT ;
    PORT
      LAYER metal4 ;
      RECT 1832.530 365.645 1832.740 365.715 ;
    END
  END w0_wd_in[180]
  PIN w0_wd_in[181]
    DIRECTION INPUT ;
    USE SIGNAL ;
    SHAPE ABUTMENT ;
    PORT
      LAYER metal4 ;
      RECT 1832.530 372.645 1832.740 372.715 ;
    END
  END w0_wd_in[181]
  PIN w0_wd_in[182]
    DIRECTION INPUT ;
    USE SIGNAL ;
    SHAPE ABUTMENT ;
    PORT
      LAYER metal4 ;
      RECT 1832.530 379.645 1832.740 379.715 ;
    END
  END w0_wd_in[182]
  PIN w0_wd_in[183]
    DIRECTION INPUT ;
    USE SIGNAL ;
    SHAPE ABUTMENT ;
    PORT
      LAYER metal4 ;
      RECT 1832.530 386.645 1832.740 386.715 ;
    END
  END w0_wd_in[183]
  PIN w0_wd_in[184]
    DIRECTION INPUT ;
    USE SIGNAL ;
    SHAPE ABUTMENT ;
    PORT
      LAYER metal4 ;
      RECT 1832.530 393.645 1832.740 393.715 ;
    END
  END w0_wd_in[184]
  PIN w0_wd_in[185]
    DIRECTION INPUT ;
    USE SIGNAL ;
    SHAPE ABUTMENT ;
    PORT
      LAYER metal4 ;
      RECT 1832.530 400.645 1832.740 400.715 ;
    END
  END w0_wd_in[185]
  PIN w0_wd_in[186]
    DIRECTION INPUT ;
    USE SIGNAL ;
    SHAPE ABUTMENT ;
    PORT
      LAYER metal4 ;
      RECT 1832.530 407.645 1832.740 407.715 ;
    END
  END w0_wd_in[186]
  PIN w0_wd_in[187]
    DIRECTION INPUT ;
    USE SIGNAL ;
    SHAPE ABUTMENT ;
    PORT
      LAYER metal4 ;
      RECT 1832.530 414.645 1832.740 414.715 ;
    END
  END w0_wd_in[187]
  PIN w0_wd_in[188]
    DIRECTION INPUT ;
    USE SIGNAL ;
    SHAPE ABUTMENT ;
    PORT
      LAYER metal4 ;
      RECT 1832.530 421.645 1832.740 421.715 ;
    END
  END w0_wd_in[188]
  PIN w0_wd_in[189]
    DIRECTION INPUT ;
    USE SIGNAL ;
    SHAPE ABUTMENT ;
    PORT
      LAYER metal4 ;
      RECT 1832.530 428.645 1832.740 428.715 ;
    END
  END w0_wd_in[189]
  PIN w0_wd_in[190]
    DIRECTION INPUT ;
    USE SIGNAL ;
    SHAPE ABUTMENT ;
    PORT
      LAYER metal4 ;
      RECT 1832.530 435.645 1832.740 435.715 ;
    END
  END w0_wd_in[190]
  PIN w0_wd_in[191]
    DIRECTION INPUT ;
    USE SIGNAL ;
    SHAPE ABUTMENT ;
    PORT
      LAYER metal4 ;
      RECT 1832.530 442.645 1832.740 442.715 ;
    END
  END w0_wd_in[191]
  PIN w0_wd_in[192]
    DIRECTION INPUT ;
    USE SIGNAL ;
    SHAPE ABUTMENT ;
    PORT
      LAYER metal4 ;
      RECT 1832.530 449.645 1832.740 449.715 ;
    END
  END w0_wd_in[192]
  PIN w0_wd_in[193]
    DIRECTION INPUT ;
    USE SIGNAL ;
    SHAPE ABUTMENT ;
    PORT
      LAYER metal4 ;
      RECT 1832.530 456.645 1832.740 456.715 ;
    END
  END w0_wd_in[193]
  PIN w0_wd_in[194]
    DIRECTION INPUT ;
    USE SIGNAL ;
    SHAPE ABUTMENT ;
    PORT
      LAYER metal4 ;
      RECT 1832.530 463.645 1832.740 463.715 ;
    END
  END w0_wd_in[194]
  PIN w0_wd_in[195]
    DIRECTION INPUT ;
    USE SIGNAL ;
    SHAPE ABUTMENT ;
    PORT
      LAYER metal4 ;
      RECT 1832.530 470.645 1832.740 470.715 ;
    END
  END w0_wd_in[195]
  PIN w0_wd_in[196]
    DIRECTION INPUT ;
    USE SIGNAL ;
    SHAPE ABUTMENT ;
    PORT
      LAYER metal4 ;
      RECT 1832.530 477.645 1832.740 477.715 ;
    END
  END w0_wd_in[196]
  PIN w0_wd_in[197]
    DIRECTION INPUT ;
    USE SIGNAL ;
    SHAPE ABUTMENT ;
    PORT
      LAYER metal4 ;
      RECT 1832.530 484.645 1832.740 484.715 ;
    END
  END w0_wd_in[197]
  PIN w0_wd_in[198]
    DIRECTION INPUT ;
    USE SIGNAL ;
    SHAPE ABUTMENT ;
    PORT
      LAYER metal4 ;
      RECT 1832.530 491.645 1832.740 491.715 ;
    END
  END w0_wd_in[198]
  PIN w0_wd_in[199]
    DIRECTION INPUT ;
    USE SIGNAL ;
    SHAPE ABUTMENT ;
    PORT
      LAYER metal4 ;
      RECT 1832.530 498.645 1832.740 498.715 ;
    END
  END w0_wd_in[199]
  PIN w0_wd_in[200]
    DIRECTION INPUT ;
    USE SIGNAL ;
    SHAPE ABUTMENT ;
    PORT
      LAYER metal4 ;
      RECT 1832.530 505.645 1832.740 505.715 ;
    END
  END w0_wd_in[200]
  PIN w0_wd_in[201]
    DIRECTION INPUT ;
    USE SIGNAL ;
    SHAPE ABUTMENT ;
    PORT
      LAYER metal4 ;
      RECT 1832.530 512.645 1832.740 512.715 ;
    END
  END w0_wd_in[201]
  PIN w0_wd_in[202]
    DIRECTION INPUT ;
    USE SIGNAL ;
    SHAPE ABUTMENT ;
    PORT
      LAYER metal4 ;
      RECT 1832.530 519.645 1832.740 519.715 ;
    END
  END w0_wd_in[202]
  PIN w0_wd_in[203]
    DIRECTION INPUT ;
    USE SIGNAL ;
    SHAPE ABUTMENT ;
    PORT
      LAYER metal4 ;
      RECT 1832.530 526.645 1832.740 526.715 ;
    END
  END w0_wd_in[203]
  PIN w0_wd_in[204]
    DIRECTION INPUT ;
    USE SIGNAL ;
    SHAPE ABUTMENT ;
    PORT
      LAYER metal4 ;
      RECT 1832.530 533.645 1832.740 533.715 ;
    END
  END w0_wd_in[204]
  PIN w0_wd_in[205]
    DIRECTION INPUT ;
    USE SIGNAL ;
    SHAPE ABUTMENT ;
    PORT
      LAYER metal4 ;
      RECT 1832.530 540.645 1832.740 540.715 ;
    END
  END w0_wd_in[205]
  PIN w0_wd_in[206]
    DIRECTION INPUT ;
    USE SIGNAL ;
    SHAPE ABUTMENT ;
    PORT
      LAYER metal4 ;
      RECT 1832.530 547.645 1832.740 547.715 ;
    END
  END w0_wd_in[206]
  PIN w0_wd_in[207]
    DIRECTION INPUT ;
    USE SIGNAL ;
    SHAPE ABUTMENT ;
    PORT
      LAYER metal4 ;
      RECT 1832.530 554.645 1832.740 554.715 ;
    END
  END w0_wd_in[207]
  PIN w0_wd_in[208]
    DIRECTION INPUT ;
    USE SIGNAL ;
    SHAPE ABUTMENT ;
    PORT
      LAYER metal4 ;
      RECT 1832.530 561.645 1832.740 561.715 ;
    END
  END w0_wd_in[208]
  PIN w0_wd_in[209]
    DIRECTION INPUT ;
    USE SIGNAL ;
    SHAPE ABUTMENT ;
    PORT
      LAYER metal4 ;
      RECT 1832.530 568.645 1832.740 568.715 ;
    END
  END w0_wd_in[209]
  PIN w0_wd_in[210]
    DIRECTION INPUT ;
    USE SIGNAL ;
    SHAPE ABUTMENT ;
    PORT
      LAYER metal4 ;
      RECT 1832.530 575.645 1832.740 575.715 ;
    END
  END w0_wd_in[210]
  PIN w0_wd_in[211]
    DIRECTION INPUT ;
    USE SIGNAL ;
    SHAPE ABUTMENT ;
    PORT
      LAYER metal4 ;
      RECT 1832.530 582.645 1832.740 582.715 ;
    END
  END w0_wd_in[211]
  PIN w0_wd_in[212]
    DIRECTION INPUT ;
    USE SIGNAL ;
    SHAPE ABUTMENT ;
    PORT
      LAYER metal4 ;
      RECT 1832.530 589.645 1832.740 589.715 ;
    END
  END w0_wd_in[212]
  PIN w0_wd_in[213]
    DIRECTION INPUT ;
    USE SIGNAL ;
    SHAPE ABUTMENT ;
    PORT
      LAYER metal4 ;
      RECT 1832.530 596.645 1832.740 596.715 ;
    END
  END w0_wd_in[213]
  PIN w0_wd_in[214]
    DIRECTION INPUT ;
    USE SIGNAL ;
    SHAPE ABUTMENT ;
    PORT
      LAYER metal4 ;
      RECT 1832.530 603.645 1832.740 603.715 ;
    END
  END w0_wd_in[214]
  PIN w0_wd_in[215]
    DIRECTION INPUT ;
    USE SIGNAL ;
    SHAPE ABUTMENT ;
    PORT
      LAYER metal4 ;
      RECT 1832.530 610.645 1832.740 610.715 ;
    END
  END w0_wd_in[215]
  PIN w0_wd_in[216]
    DIRECTION INPUT ;
    USE SIGNAL ;
    SHAPE ABUTMENT ;
    PORT
      LAYER metal4 ;
      RECT 1832.530 617.645 1832.740 617.715 ;
    END
  END w0_wd_in[216]
  PIN w0_wd_in[217]
    DIRECTION INPUT ;
    USE SIGNAL ;
    SHAPE ABUTMENT ;
    PORT
      LAYER metal4 ;
      RECT 1832.530 624.645 1832.740 624.715 ;
    END
  END w0_wd_in[217]
  PIN w0_wd_in[218]
    DIRECTION INPUT ;
    USE SIGNAL ;
    SHAPE ABUTMENT ;
    PORT
      LAYER metal4 ;
      RECT 1832.530 631.645 1832.740 631.715 ;
    END
  END w0_wd_in[218]
  PIN w0_wd_in[219]
    DIRECTION INPUT ;
    USE SIGNAL ;
    SHAPE ABUTMENT ;
    PORT
      LAYER metal4 ;
      RECT 1832.530 638.645 1832.740 638.715 ;
    END
  END w0_wd_in[219]
  PIN w0_wd_in[220]
    DIRECTION INPUT ;
    USE SIGNAL ;
    SHAPE ABUTMENT ;
    PORT
      LAYER metal4 ;
      RECT 1832.530 645.645 1832.740 645.715 ;
    END
  END w0_wd_in[220]
  PIN w0_wd_in[221]
    DIRECTION INPUT ;
    USE SIGNAL ;
    SHAPE ABUTMENT ;
    PORT
      LAYER metal4 ;
      RECT 1832.530 652.645 1832.740 652.715 ;
    END
  END w0_wd_in[221]
  PIN w0_wd_in[222]
    DIRECTION INPUT ;
    USE SIGNAL ;
    SHAPE ABUTMENT ;
    PORT
      LAYER metal4 ;
      RECT 1832.530 659.645 1832.740 659.715 ;
    END
  END w0_wd_in[222]
  PIN w0_wd_in[223]
    DIRECTION INPUT ;
    USE SIGNAL ;
    SHAPE ABUTMENT ;
    PORT
      LAYER metal4 ;
      RECT 1832.530 666.645 1832.740 666.715 ;
    END
  END w0_wd_in[223]
  PIN w0_wd_in[224]
    DIRECTION INPUT ;
    USE SIGNAL ;
    SHAPE ABUTMENT ;
    PORT
      LAYER metal4 ;
      RECT 1832.530 673.645 1832.740 673.715 ;
    END
  END w0_wd_in[224]
  PIN w0_wd_in[225]
    DIRECTION INPUT ;
    USE SIGNAL ;
    SHAPE ABUTMENT ;
    PORT
      LAYER metal4 ;
      RECT 1832.530 680.645 1832.740 680.715 ;
    END
  END w0_wd_in[225]
  PIN w0_wd_in[226]
    DIRECTION INPUT ;
    USE SIGNAL ;
    SHAPE ABUTMENT ;
    PORT
      LAYER metal4 ;
      RECT 1832.530 687.645 1832.740 687.715 ;
    END
  END w0_wd_in[226]
  PIN w0_wd_in[227]
    DIRECTION INPUT ;
    USE SIGNAL ;
    SHAPE ABUTMENT ;
    PORT
      LAYER metal4 ;
      RECT 1832.530 694.645 1832.740 694.715 ;
    END
  END w0_wd_in[227]
  PIN w0_wd_in[228]
    DIRECTION INPUT ;
    USE SIGNAL ;
    SHAPE ABUTMENT ;
    PORT
      LAYER metal4 ;
      RECT 1832.530 701.645 1832.740 701.715 ;
    END
  END w0_wd_in[228]
  PIN w0_wd_in[229]
    DIRECTION INPUT ;
    USE SIGNAL ;
    SHAPE ABUTMENT ;
    PORT
      LAYER metal4 ;
      RECT 1832.530 708.645 1832.740 708.715 ;
    END
  END w0_wd_in[229]
  PIN w0_wd_in[230]
    DIRECTION INPUT ;
    USE SIGNAL ;
    SHAPE ABUTMENT ;
    PORT
      LAYER metal4 ;
      RECT 1832.530 715.645 1832.740 715.715 ;
    END
  END w0_wd_in[230]
  PIN w0_wd_in[231]
    DIRECTION INPUT ;
    USE SIGNAL ;
    SHAPE ABUTMENT ;
    PORT
      LAYER metal4 ;
      RECT 1832.530 722.645 1832.740 722.715 ;
    END
  END w0_wd_in[231]
  PIN w0_wd_in[232]
    DIRECTION INPUT ;
    USE SIGNAL ;
    SHAPE ABUTMENT ;
    PORT
      LAYER metal4 ;
      RECT 1832.530 729.645 1832.740 729.715 ;
    END
  END w0_wd_in[232]
  PIN w0_wd_in[233]
    DIRECTION INPUT ;
    USE SIGNAL ;
    SHAPE ABUTMENT ;
    PORT
      LAYER metal4 ;
      RECT 1832.530 736.645 1832.740 736.715 ;
    END
  END w0_wd_in[233]
  PIN w0_wd_in[234]
    DIRECTION INPUT ;
    USE SIGNAL ;
    SHAPE ABUTMENT ;
    PORT
      LAYER metal4 ;
      RECT 1832.530 743.645 1832.740 743.715 ;
    END
  END w0_wd_in[234]
  PIN w0_wd_in[235]
    DIRECTION INPUT ;
    USE SIGNAL ;
    SHAPE ABUTMENT ;
    PORT
      LAYER metal4 ;
      RECT 1832.530 750.645 1832.740 750.715 ;
    END
  END w0_wd_in[235]
  PIN w0_wd_in[236]
    DIRECTION INPUT ;
    USE SIGNAL ;
    SHAPE ABUTMENT ;
    PORT
      LAYER metal4 ;
      RECT 1832.530 757.645 1832.740 757.715 ;
    END
  END w0_wd_in[236]
  PIN w0_wd_in[237]
    DIRECTION INPUT ;
    USE SIGNAL ;
    SHAPE ABUTMENT ;
    PORT
      LAYER metal4 ;
      RECT 1832.530 764.645 1832.740 764.715 ;
    END
  END w0_wd_in[237]
  PIN w0_wd_in[238]
    DIRECTION INPUT ;
    USE SIGNAL ;
    SHAPE ABUTMENT ;
    PORT
      LAYER metal4 ;
      RECT 1832.530 771.645 1832.740 771.715 ;
    END
  END w0_wd_in[238]
  PIN w0_wd_in[239]
    DIRECTION INPUT ;
    USE SIGNAL ;
    SHAPE ABUTMENT ;
    PORT
      LAYER metal4 ;
      RECT 1832.530 778.645 1832.740 778.715 ;
    END
  END w0_wd_in[239]
  PIN w0_wd_in[240]
    DIRECTION INPUT ;
    USE SIGNAL ;
    SHAPE ABUTMENT ;
    PORT
      LAYER metal4 ;
      RECT 1832.530 785.645 1832.740 785.715 ;
    END
  END w0_wd_in[240]
  PIN w0_wd_in[241]
    DIRECTION INPUT ;
    USE SIGNAL ;
    SHAPE ABUTMENT ;
    PORT
      LAYER metal4 ;
      RECT 1832.530 792.645 1832.740 792.715 ;
    END
  END w0_wd_in[241]
  PIN w0_wd_in[242]
    DIRECTION INPUT ;
    USE SIGNAL ;
    SHAPE ABUTMENT ;
    PORT
      LAYER metal4 ;
      RECT 1832.530 799.645 1832.740 799.715 ;
    END
  END w0_wd_in[242]
  PIN w0_wd_in[243]
    DIRECTION INPUT ;
    USE SIGNAL ;
    SHAPE ABUTMENT ;
    PORT
      LAYER metal4 ;
      RECT 1832.530 806.645 1832.740 806.715 ;
    END
  END w0_wd_in[243]
  PIN w0_wd_in[244]
    DIRECTION INPUT ;
    USE SIGNAL ;
    SHAPE ABUTMENT ;
    PORT
      LAYER metal4 ;
      RECT 1832.530 813.645 1832.740 813.715 ;
    END
  END w0_wd_in[244]
  PIN w0_wd_in[245]
    DIRECTION INPUT ;
    USE SIGNAL ;
    SHAPE ABUTMENT ;
    PORT
      LAYER metal4 ;
      RECT 1832.530 820.645 1832.740 820.715 ;
    END
  END w0_wd_in[245]
  PIN w0_wd_in[246]
    DIRECTION INPUT ;
    USE SIGNAL ;
    SHAPE ABUTMENT ;
    PORT
      LAYER metal4 ;
      RECT 1832.530 827.645 1832.740 827.715 ;
    END
  END w0_wd_in[246]
  PIN w0_wd_in[247]
    DIRECTION INPUT ;
    USE SIGNAL ;
    SHAPE ABUTMENT ;
    PORT
      LAYER metal4 ;
      RECT 1832.530 834.645 1832.740 834.715 ;
    END
  END w0_wd_in[247]
  PIN w0_wd_in[248]
    DIRECTION INPUT ;
    USE SIGNAL ;
    SHAPE ABUTMENT ;
    PORT
      LAYER metal4 ;
      RECT 1832.530 841.645 1832.740 841.715 ;
    END
  END w0_wd_in[248]
  PIN w0_wd_in[249]
    DIRECTION INPUT ;
    USE SIGNAL ;
    SHAPE ABUTMENT ;
    PORT
      LAYER metal4 ;
      RECT 1832.530 848.645 1832.740 848.715 ;
    END
  END w0_wd_in[249]
  PIN w0_wd_in[250]
    DIRECTION INPUT ;
    USE SIGNAL ;
    SHAPE ABUTMENT ;
    PORT
      LAYER metal4 ;
      RECT 1832.530 855.645 1832.740 855.715 ;
    END
  END w0_wd_in[250]
  PIN w0_wd_in[251]
    DIRECTION INPUT ;
    USE SIGNAL ;
    SHAPE ABUTMENT ;
    PORT
      LAYER metal4 ;
      RECT 1832.530 862.645 1832.740 862.715 ;
    END
  END w0_wd_in[251]
  PIN w0_wd_in[252]
    DIRECTION INPUT ;
    USE SIGNAL ;
    SHAPE ABUTMENT ;
    PORT
      LAYER metal4 ;
      RECT 1832.530 869.645 1832.740 869.715 ;
    END
  END w0_wd_in[252]
  PIN w0_wd_in[253]
    DIRECTION INPUT ;
    USE SIGNAL ;
    SHAPE ABUTMENT ;
    PORT
      LAYER metal4 ;
      RECT 1832.530 876.645 1832.740 876.715 ;
    END
  END w0_wd_in[253]
  PIN w0_wd_in[254]
    DIRECTION INPUT ;
    USE SIGNAL ;
    SHAPE ABUTMENT ;
    PORT
      LAYER metal4 ;
      RECT 1832.530 883.645 1832.740 883.715 ;
    END
  END w0_wd_in[254]
  PIN w0_wd_in[255]
    DIRECTION INPUT ;
    USE SIGNAL ;
    SHAPE ABUTMENT ;
    PORT
      LAYER metal4 ;
      RECT 1832.530 890.645 1832.740 890.715 ;
    END
  END w0_wd_in[255]
  PIN w0_wd_in[256]
    DIRECTION OUTPUT ;
    USE SIGNAL ;
    SHAPE ABUTMENT ;
    PORT
      LAYER metal3 ;
      RECT 0.805 0.000 0.875 0.210 ;
    END
  END w0_wd_in[256]
  PIN w0_wd_in[257]
    DIRECTION OUTPUT ;
    USE SIGNAL ;
    SHAPE ABUTMENT ;
    PORT
      LAYER metal3 ;
      RECT 4.305 0.000 4.375 0.210 ;
    END
  END w0_wd_in[257]
  PIN w0_wd_in[258]
    DIRECTION OUTPUT ;
    USE SIGNAL ;
    SHAPE ABUTMENT ;
    PORT
      LAYER metal3 ;
      RECT 7.805 0.000 7.875 0.210 ;
    END
  END w0_wd_in[258]
  PIN w0_wd_in[259]
    DIRECTION OUTPUT ;
    USE SIGNAL ;
    SHAPE ABUTMENT ;
    PORT
      LAYER metal3 ;
      RECT 11.305 0.000 11.375 0.210 ;
    END
  END w0_wd_in[259]
  PIN w0_wd_in[260]
    DIRECTION OUTPUT ;
    USE SIGNAL ;
    SHAPE ABUTMENT ;
    PORT
      LAYER metal3 ;
      RECT 14.805 0.000 14.875 0.210 ;
    END
  END w0_wd_in[260]
  PIN w0_wd_in[261]
    DIRECTION OUTPUT ;
    USE SIGNAL ;
    SHAPE ABUTMENT ;
    PORT
      LAYER metal3 ;
      RECT 18.305 0.000 18.375 0.210 ;
    END
  END w0_wd_in[261]
  PIN w0_wd_in[262]
    DIRECTION OUTPUT ;
    USE SIGNAL ;
    SHAPE ABUTMENT ;
    PORT
      LAYER metal3 ;
      RECT 21.805 0.000 21.875 0.210 ;
    END
  END w0_wd_in[262]
  PIN w0_wd_in[263]
    DIRECTION OUTPUT ;
    USE SIGNAL ;
    SHAPE ABUTMENT ;
    PORT
      LAYER metal3 ;
      RECT 25.305 0.000 25.375 0.210 ;
    END
  END w0_wd_in[263]
  PIN w0_wd_in[264]
    DIRECTION OUTPUT ;
    USE SIGNAL ;
    SHAPE ABUTMENT ;
    PORT
      LAYER metal3 ;
      RECT 28.805 0.000 28.875 0.210 ;
    END
  END w0_wd_in[264]
  PIN w0_wd_in[265]
    DIRECTION OUTPUT ;
    USE SIGNAL ;
    SHAPE ABUTMENT ;
    PORT
      LAYER metal3 ;
      RECT 32.305 0.000 32.375 0.210 ;
    END
  END w0_wd_in[265]
  PIN w0_wd_in[266]
    DIRECTION OUTPUT ;
    USE SIGNAL ;
    SHAPE ABUTMENT ;
    PORT
      LAYER metal3 ;
      RECT 35.805 0.000 35.875 0.210 ;
    END
  END w0_wd_in[266]
  PIN w0_wd_in[267]
    DIRECTION OUTPUT ;
    USE SIGNAL ;
    SHAPE ABUTMENT ;
    PORT
      LAYER metal3 ;
      RECT 39.305 0.000 39.375 0.210 ;
    END
  END w0_wd_in[267]
  PIN w0_wd_in[268]
    DIRECTION OUTPUT ;
    USE SIGNAL ;
    SHAPE ABUTMENT ;
    PORT
      LAYER metal3 ;
      RECT 42.805 0.000 42.875 0.210 ;
    END
  END w0_wd_in[268]
  PIN w0_wd_in[269]
    DIRECTION OUTPUT ;
    USE SIGNAL ;
    SHAPE ABUTMENT ;
    PORT
      LAYER metal3 ;
      RECT 46.305 0.000 46.375 0.210 ;
    END
  END w0_wd_in[269]
  PIN w0_wd_in[270]
    DIRECTION OUTPUT ;
    USE SIGNAL ;
    SHAPE ABUTMENT ;
    PORT
      LAYER metal3 ;
      RECT 49.805 0.000 49.875 0.210 ;
    END
  END w0_wd_in[270]
  PIN w0_wd_in[271]
    DIRECTION OUTPUT ;
    USE SIGNAL ;
    SHAPE ABUTMENT ;
    PORT
      LAYER metal3 ;
      RECT 53.305 0.000 53.375 0.210 ;
    END
  END w0_wd_in[271]
  PIN w0_wd_in[272]
    DIRECTION OUTPUT ;
    USE SIGNAL ;
    SHAPE ABUTMENT ;
    PORT
      LAYER metal3 ;
      RECT 56.805 0.000 56.875 0.210 ;
    END
  END w0_wd_in[272]
  PIN w0_wd_in[273]
    DIRECTION OUTPUT ;
    USE SIGNAL ;
    SHAPE ABUTMENT ;
    PORT
      LAYER metal3 ;
      RECT 60.305 0.000 60.375 0.210 ;
    END
  END w0_wd_in[273]
  PIN w0_wd_in[274]
    DIRECTION OUTPUT ;
    USE SIGNAL ;
    SHAPE ABUTMENT ;
    PORT
      LAYER metal3 ;
      RECT 63.805 0.000 63.875 0.210 ;
    END
  END w0_wd_in[274]
  PIN w0_wd_in[275]
    DIRECTION OUTPUT ;
    USE SIGNAL ;
    SHAPE ABUTMENT ;
    PORT
      LAYER metal3 ;
      RECT 67.305 0.000 67.375 0.210 ;
    END
  END w0_wd_in[275]
  PIN w0_wd_in[276]
    DIRECTION OUTPUT ;
    USE SIGNAL ;
    SHAPE ABUTMENT ;
    PORT
      LAYER metal3 ;
      RECT 70.805 0.000 70.875 0.210 ;
    END
  END w0_wd_in[276]
  PIN w0_wd_in[277]
    DIRECTION OUTPUT ;
    USE SIGNAL ;
    SHAPE ABUTMENT ;
    PORT
      LAYER metal3 ;
      RECT 74.305 0.000 74.375 0.210 ;
    END
  END w0_wd_in[277]
  PIN w0_wd_in[278]
    DIRECTION OUTPUT ;
    USE SIGNAL ;
    SHAPE ABUTMENT ;
    PORT
      LAYER metal3 ;
      RECT 77.805 0.000 77.875 0.210 ;
    END
  END w0_wd_in[278]
  PIN w0_wd_in[279]
    DIRECTION OUTPUT ;
    USE SIGNAL ;
    SHAPE ABUTMENT ;
    PORT
      LAYER metal3 ;
      RECT 81.305 0.000 81.375 0.210 ;
    END
  END w0_wd_in[279]
  PIN w0_wd_in[280]
    DIRECTION OUTPUT ;
    USE SIGNAL ;
    SHAPE ABUTMENT ;
    PORT
      LAYER metal3 ;
      RECT 84.805 0.000 84.875 0.210 ;
    END
  END w0_wd_in[280]
  PIN w0_wd_in[281]
    DIRECTION OUTPUT ;
    USE SIGNAL ;
    SHAPE ABUTMENT ;
    PORT
      LAYER metal3 ;
      RECT 88.305 0.000 88.375 0.210 ;
    END
  END w0_wd_in[281]
  PIN w0_wd_in[282]
    DIRECTION OUTPUT ;
    USE SIGNAL ;
    SHAPE ABUTMENT ;
    PORT
      LAYER metal3 ;
      RECT 91.805 0.000 91.875 0.210 ;
    END
  END w0_wd_in[282]
  PIN w0_wd_in[283]
    DIRECTION OUTPUT ;
    USE SIGNAL ;
    SHAPE ABUTMENT ;
    PORT
      LAYER metal3 ;
      RECT 95.305 0.000 95.375 0.210 ;
    END
  END w0_wd_in[283]
  PIN w0_wd_in[284]
    DIRECTION OUTPUT ;
    USE SIGNAL ;
    SHAPE ABUTMENT ;
    PORT
      LAYER metal3 ;
      RECT 98.805 0.000 98.875 0.210 ;
    END
  END w0_wd_in[284]
  PIN w0_wd_in[285]
    DIRECTION OUTPUT ;
    USE SIGNAL ;
    SHAPE ABUTMENT ;
    PORT
      LAYER metal3 ;
      RECT 102.305 0.000 102.375 0.210 ;
    END
  END w0_wd_in[285]
  PIN w0_wd_in[286]
    DIRECTION OUTPUT ;
    USE SIGNAL ;
    SHAPE ABUTMENT ;
    PORT
      LAYER metal3 ;
      RECT 105.805 0.000 105.875 0.210 ;
    END
  END w0_wd_in[286]
  PIN w0_wd_in[287]
    DIRECTION OUTPUT ;
    USE SIGNAL ;
    SHAPE ABUTMENT ;
    PORT
      LAYER metal3 ;
      RECT 109.305 0.000 109.375 0.210 ;
    END
  END w0_wd_in[287]
  PIN w0_wd_in[288]
    DIRECTION OUTPUT ;
    USE SIGNAL ;
    SHAPE ABUTMENT ;
    PORT
      LAYER metal3 ;
      RECT 112.805 0.000 112.875 0.210 ;
    END
  END w0_wd_in[288]
  PIN w0_wd_in[289]
    DIRECTION OUTPUT ;
    USE SIGNAL ;
    SHAPE ABUTMENT ;
    PORT
      LAYER metal3 ;
      RECT 116.305 0.000 116.375 0.210 ;
    END
  END w0_wd_in[289]
  PIN w0_wd_in[290]
    DIRECTION OUTPUT ;
    USE SIGNAL ;
    SHAPE ABUTMENT ;
    PORT
      LAYER metal3 ;
      RECT 119.805 0.000 119.875 0.210 ;
    END
  END w0_wd_in[290]
  PIN w0_wd_in[291]
    DIRECTION OUTPUT ;
    USE SIGNAL ;
    SHAPE ABUTMENT ;
    PORT
      LAYER metal3 ;
      RECT 123.305 0.000 123.375 0.210 ;
    END
  END w0_wd_in[291]
  PIN w0_wd_in[292]
    DIRECTION OUTPUT ;
    USE SIGNAL ;
    SHAPE ABUTMENT ;
    PORT
      LAYER metal3 ;
      RECT 126.805 0.000 126.875 0.210 ;
    END
  END w0_wd_in[292]
  PIN w0_wd_in[293]
    DIRECTION OUTPUT ;
    USE SIGNAL ;
    SHAPE ABUTMENT ;
    PORT
      LAYER metal3 ;
      RECT 130.305 0.000 130.375 0.210 ;
    END
  END w0_wd_in[293]
  PIN w0_wd_in[294]
    DIRECTION OUTPUT ;
    USE SIGNAL ;
    SHAPE ABUTMENT ;
    PORT
      LAYER metal3 ;
      RECT 133.805 0.000 133.875 0.210 ;
    END
  END w0_wd_in[294]
  PIN w0_wd_in[295]
    DIRECTION OUTPUT ;
    USE SIGNAL ;
    SHAPE ABUTMENT ;
    PORT
      LAYER metal3 ;
      RECT 137.305 0.000 137.375 0.210 ;
    END
  END w0_wd_in[295]
  PIN w0_wd_in[296]
    DIRECTION OUTPUT ;
    USE SIGNAL ;
    SHAPE ABUTMENT ;
    PORT
      LAYER metal3 ;
      RECT 140.805 0.000 140.875 0.210 ;
    END
  END w0_wd_in[296]
  PIN w0_wd_in[297]
    DIRECTION OUTPUT ;
    USE SIGNAL ;
    SHAPE ABUTMENT ;
    PORT
      LAYER metal3 ;
      RECT 144.305 0.000 144.375 0.210 ;
    END
  END w0_wd_in[297]
  PIN w0_wd_in[298]
    DIRECTION OUTPUT ;
    USE SIGNAL ;
    SHAPE ABUTMENT ;
    PORT
      LAYER metal3 ;
      RECT 147.805 0.000 147.875 0.210 ;
    END
  END w0_wd_in[298]
  PIN w0_wd_in[299]
    DIRECTION OUTPUT ;
    USE SIGNAL ;
    SHAPE ABUTMENT ;
    PORT
      LAYER metal3 ;
      RECT 151.305 0.000 151.375 0.210 ;
    END
  END w0_wd_in[299]
  PIN w0_wd_in[300]
    DIRECTION OUTPUT ;
    USE SIGNAL ;
    SHAPE ABUTMENT ;
    PORT
      LAYER metal3 ;
      RECT 154.805 0.000 154.875 0.210 ;
    END
  END w0_wd_in[300]
  PIN w0_wd_in[301]
    DIRECTION OUTPUT ;
    USE SIGNAL ;
    SHAPE ABUTMENT ;
    PORT
      LAYER metal3 ;
      RECT 158.305 0.000 158.375 0.210 ;
    END
  END w0_wd_in[301]
  PIN w0_wd_in[302]
    DIRECTION OUTPUT ;
    USE SIGNAL ;
    SHAPE ABUTMENT ;
    PORT
      LAYER metal3 ;
      RECT 161.805 0.000 161.875 0.210 ;
    END
  END w0_wd_in[302]
  PIN w0_wd_in[303]
    DIRECTION OUTPUT ;
    USE SIGNAL ;
    SHAPE ABUTMENT ;
    PORT
      LAYER metal3 ;
      RECT 165.305 0.000 165.375 0.210 ;
    END
  END w0_wd_in[303]
  PIN w0_wd_in[304]
    DIRECTION OUTPUT ;
    USE SIGNAL ;
    SHAPE ABUTMENT ;
    PORT
      LAYER metal3 ;
      RECT 168.805 0.000 168.875 0.210 ;
    END
  END w0_wd_in[304]
  PIN w0_wd_in[305]
    DIRECTION OUTPUT ;
    USE SIGNAL ;
    SHAPE ABUTMENT ;
    PORT
      LAYER metal3 ;
      RECT 172.305 0.000 172.375 0.210 ;
    END
  END w0_wd_in[305]
  PIN w0_wd_in[306]
    DIRECTION OUTPUT ;
    USE SIGNAL ;
    SHAPE ABUTMENT ;
    PORT
      LAYER metal3 ;
      RECT 175.805 0.000 175.875 0.210 ;
    END
  END w0_wd_in[306]
  PIN w0_wd_in[307]
    DIRECTION OUTPUT ;
    USE SIGNAL ;
    SHAPE ABUTMENT ;
    PORT
      LAYER metal3 ;
      RECT 179.305 0.000 179.375 0.210 ;
    END
  END w0_wd_in[307]
  PIN w0_wd_in[308]
    DIRECTION OUTPUT ;
    USE SIGNAL ;
    SHAPE ABUTMENT ;
    PORT
      LAYER metal3 ;
      RECT 182.805 0.000 182.875 0.210 ;
    END
  END w0_wd_in[308]
  PIN w0_wd_in[309]
    DIRECTION OUTPUT ;
    USE SIGNAL ;
    SHAPE ABUTMENT ;
    PORT
      LAYER metal3 ;
      RECT 186.305 0.000 186.375 0.210 ;
    END
  END w0_wd_in[309]
  PIN w0_wd_in[310]
    DIRECTION OUTPUT ;
    USE SIGNAL ;
    SHAPE ABUTMENT ;
    PORT
      LAYER metal3 ;
      RECT 189.805 0.000 189.875 0.210 ;
    END
  END w0_wd_in[310]
  PIN w0_wd_in[311]
    DIRECTION OUTPUT ;
    USE SIGNAL ;
    SHAPE ABUTMENT ;
    PORT
      LAYER metal3 ;
      RECT 193.305 0.000 193.375 0.210 ;
    END
  END w0_wd_in[311]
  PIN w0_wd_in[312]
    DIRECTION OUTPUT ;
    USE SIGNAL ;
    SHAPE ABUTMENT ;
    PORT
      LAYER metal3 ;
      RECT 196.805 0.000 196.875 0.210 ;
    END
  END w0_wd_in[312]
  PIN w0_wd_in[313]
    DIRECTION OUTPUT ;
    USE SIGNAL ;
    SHAPE ABUTMENT ;
    PORT
      LAYER metal3 ;
      RECT 200.305 0.000 200.375 0.210 ;
    END
  END w0_wd_in[313]
  PIN w0_wd_in[314]
    DIRECTION OUTPUT ;
    USE SIGNAL ;
    SHAPE ABUTMENT ;
    PORT
      LAYER metal3 ;
      RECT 203.805 0.000 203.875 0.210 ;
    END
  END w0_wd_in[314]
  PIN w0_wd_in[315]
    DIRECTION OUTPUT ;
    USE SIGNAL ;
    SHAPE ABUTMENT ;
    PORT
      LAYER metal3 ;
      RECT 207.305 0.000 207.375 0.210 ;
    END
  END w0_wd_in[315]
  PIN w0_wd_in[316]
    DIRECTION OUTPUT ;
    USE SIGNAL ;
    SHAPE ABUTMENT ;
    PORT
      LAYER metal3 ;
      RECT 210.805 0.000 210.875 0.210 ;
    END
  END w0_wd_in[316]
  PIN w0_wd_in[317]
    DIRECTION OUTPUT ;
    USE SIGNAL ;
    SHAPE ABUTMENT ;
    PORT
      LAYER metal3 ;
      RECT 214.305 0.000 214.375 0.210 ;
    END
  END w0_wd_in[317]
  PIN w0_wd_in[318]
    DIRECTION OUTPUT ;
    USE SIGNAL ;
    SHAPE ABUTMENT ;
    PORT
      LAYER metal3 ;
      RECT 217.805 0.000 217.875 0.210 ;
    END
  END w0_wd_in[318]
  PIN w0_wd_in[319]
    DIRECTION OUTPUT ;
    USE SIGNAL ;
    SHAPE ABUTMENT ;
    PORT
      LAYER metal3 ;
      RECT 221.305 0.000 221.375 0.210 ;
    END
  END w0_wd_in[319]
  PIN w0_wd_in[320]
    DIRECTION OUTPUT ;
    USE SIGNAL ;
    SHAPE ABUTMENT ;
    PORT
      LAYER metal3 ;
      RECT 224.805 0.000 224.875 0.210 ;
    END
  END w0_wd_in[320]
  PIN w0_wd_in[321]
    DIRECTION OUTPUT ;
    USE SIGNAL ;
    SHAPE ABUTMENT ;
    PORT
      LAYER metal3 ;
      RECT 228.305 0.000 228.375 0.210 ;
    END
  END w0_wd_in[321]
  PIN w0_wd_in[322]
    DIRECTION OUTPUT ;
    USE SIGNAL ;
    SHAPE ABUTMENT ;
    PORT
      LAYER metal3 ;
      RECT 231.805 0.000 231.875 0.210 ;
    END
  END w0_wd_in[322]
  PIN w0_wd_in[323]
    DIRECTION OUTPUT ;
    USE SIGNAL ;
    SHAPE ABUTMENT ;
    PORT
      LAYER metal3 ;
      RECT 235.305 0.000 235.375 0.210 ;
    END
  END w0_wd_in[323]
  PIN w0_wd_in[324]
    DIRECTION OUTPUT ;
    USE SIGNAL ;
    SHAPE ABUTMENT ;
    PORT
      LAYER metal3 ;
      RECT 238.805 0.000 238.875 0.210 ;
    END
  END w0_wd_in[324]
  PIN w0_wd_in[325]
    DIRECTION OUTPUT ;
    USE SIGNAL ;
    SHAPE ABUTMENT ;
    PORT
      LAYER metal3 ;
      RECT 242.305 0.000 242.375 0.210 ;
    END
  END w0_wd_in[325]
  PIN w0_wd_in[326]
    DIRECTION OUTPUT ;
    USE SIGNAL ;
    SHAPE ABUTMENT ;
    PORT
      LAYER metal3 ;
      RECT 245.805 0.000 245.875 0.210 ;
    END
  END w0_wd_in[326]
  PIN w0_wd_in[327]
    DIRECTION OUTPUT ;
    USE SIGNAL ;
    SHAPE ABUTMENT ;
    PORT
      LAYER metal3 ;
      RECT 249.305 0.000 249.375 0.210 ;
    END
  END w0_wd_in[327]
  PIN w0_wd_in[328]
    DIRECTION OUTPUT ;
    USE SIGNAL ;
    SHAPE ABUTMENT ;
    PORT
      LAYER metal3 ;
      RECT 252.805 0.000 252.875 0.210 ;
    END
  END w0_wd_in[328]
  PIN w0_wd_in[329]
    DIRECTION OUTPUT ;
    USE SIGNAL ;
    SHAPE ABUTMENT ;
    PORT
      LAYER metal3 ;
      RECT 256.305 0.000 256.375 0.210 ;
    END
  END w0_wd_in[329]
  PIN w0_wd_in[330]
    DIRECTION OUTPUT ;
    USE SIGNAL ;
    SHAPE ABUTMENT ;
    PORT
      LAYER metal3 ;
      RECT 259.805 0.000 259.875 0.210 ;
    END
  END w0_wd_in[330]
  PIN w0_wd_in[331]
    DIRECTION OUTPUT ;
    USE SIGNAL ;
    SHAPE ABUTMENT ;
    PORT
      LAYER metal3 ;
      RECT 263.305 0.000 263.375 0.210 ;
    END
  END w0_wd_in[331]
  PIN w0_wd_in[332]
    DIRECTION OUTPUT ;
    USE SIGNAL ;
    SHAPE ABUTMENT ;
    PORT
      LAYER metal3 ;
      RECT 266.805 0.000 266.875 0.210 ;
    END
  END w0_wd_in[332]
  PIN w0_wd_in[333]
    DIRECTION OUTPUT ;
    USE SIGNAL ;
    SHAPE ABUTMENT ;
    PORT
      LAYER metal3 ;
      RECT 270.305 0.000 270.375 0.210 ;
    END
  END w0_wd_in[333]
  PIN w0_wd_in[334]
    DIRECTION OUTPUT ;
    USE SIGNAL ;
    SHAPE ABUTMENT ;
    PORT
      LAYER metal3 ;
      RECT 273.805 0.000 273.875 0.210 ;
    END
  END w0_wd_in[334]
  PIN w0_wd_in[335]
    DIRECTION OUTPUT ;
    USE SIGNAL ;
    SHAPE ABUTMENT ;
    PORT
      LAYER metal3 ;
      RECT 277.305 0.000 277.375 0.210 ;
    END
  END w0_wd_in[335]
  PIN w0_wd_in[336]
    DIRECTION OUTPUT ;
    USE SIGNAL ;
    SHAPE ABUTMENT ;
    PORT
      LAYER metal3 ;
      RECT 280.805 0.000 280.875 0.210 ;
    END
  END w0_wd_in[336]
  PIN w0_wd_in[337]
    DIRECTION OUTPUT ;
    USE SIGNAL ;
    SHAPE ABUTMENT ;
    PORT
      LAYER metal3 ;
      RECT 284.305 0.000 284.375 0.210 ;
    END
  END w0_wd_in[337]
  PIN w0_wd_in[338]
    DIRECTION OUTPUT ;
    USE SIGNAL ;
    SHAPE ABUTMENT ;
    PORT
      LAYER metal3 ;
      RECT 287.805 0.000 287.875 0.210 ;
    END
  END w0_wd_in[338]
  PIN w0_wd_in[339]
    DIRECTION OUTPUT ;
    USE SIGNAL ;
    SHAPE ABUTMENT ;
    PORT
      LAYER metal3 ;
      RECT 291.305 0.000 291.375 0.210 ;
    END
  END w0_wd_in[339]
  PIN w0_wd_in[340]
    DIRECTION OUTPUT ;
    USE SIGNAL ;
    SHAPE ABUTMENT ;
    PORT
      LAYER metal3 ;
      RECT 294.805 0.000 294.875 0.210 ;
    END
  END w0_wd_in[340]
  PIN w0_wd_in[341]
    DIRECTION OUTPUT ;
    USE SIGNAL ;
    SHAPE ABUTMENT ;
    PORT
      LAYER metal3 ;
      RECT 298.305 0.000 298.375 0.210 ;
    END
  END w0_wd_in[341]
  PIN w0_wd_in[342]
    DIRECTION OUTPUT ;
    USE SIGNAL ;
    SHAPE ABUTMENT ;
    PORT
      LAYER metal3 ;
      RECT 301.805 0.000 301.875 0.210 ;
    END
  END w0_wd_in[342]
  PIN w0_wd_in[343]
    DIRECTION OUTPUT ;
    USE SIGNAL ;
    SHAPE ABUTMENT ;
    PORT
      LAYER metal3 ;
      RECT 305.305 0.000 305.375 0.210 ;
    END
  END w0_wd_in[343]
  PIN w0_wd_in[344]
    DIRECTION OUTPUT ;
    USE SIGNAL ;
    SHAPE ABUTMENT ;
    PORT
      LAYER metal3 ;
      RECT 308.805 0.000 308.875 0.210 ;
    END
  END w0_wd_in[344]
  PIN w0_wd_in[345]
    DIRECTION OUTPUT ;
    USE SIGNAL ;
    SHAPE ABUTMENT ;
    PORT
      LAYER metal3 ;
      RECT 312.305 0.000 312.375 0.210 ;
    END
  END w0_wd_in[345]
  PIN w0_wd_in[346]
    DIRECTION OUTPUT ;
    USE SIGNAL ;
    SHAPE ABUTMENT ;
    PORT
      LAYER metal3 ;
      RECT 315.805 0.000 315.875 0.210 ;
    END
  END w0_wd_in[346]
  PIN w0_wd_in[347]
    DIRECTION OUTPUT ;
    USE SIGNAL ;
    SHAPE ABUTMENT ;
    PORT
      LAYER metal3 ;
      RECT 319.305 0.000 319.375 0.210 ;
    END
  END w0_wd_in[347]
  PIN w0_wd_in[348]
    DIRECTION OUTPUT ;
    USE SIGNAL ;
    SHAPE ABUTMENT ;
    PORT
      LAYER metal3 ;
      RECT 322.805 0.000 322.875 0.210 ;
    END
  END w0_wd_in[348]
  PIN w0_wd_in[349]
    DIRECTION OUTPUT ;
    USE SIGNAL ;
    SHAPE ABUTMENT ;
    PORT
      LAYER metal3 ;
      RECT 326.305 0.000 326.375 0.210 ;
    END
  END w0_wd_in[349]
  PIN w0_wd_in[350]
    DIRECTION OUTPUT ;
    USE SIGNAL ;
    SHAPE ABUTMENT ;
    PORT
      LAYER metal3 ;
      RECT 329.805 0.000 329.875 0.210 ;
    END
  END w0_wd_in[350]
  PIN w0_wd_in[351]
    DIRECTION OUTPUT ;
    USE SIGNAL ;
    SHAPE ABUTMENT ;
    PORT
      LAYER metal3 ;
      RECT 333.305 0.000 333.375 0.210 ;
    END
  END w0_wd_in[351]
  PIN w0_wd_in[352]
    DIRECTION OUTPUT ;
    USE SIGNAL ;
    SHAPE ABUTMENT ;
    PORT
      LAYER metal3 ;
      RECT 336.805 0.000 336.875 0.210 ;
    END
  END w0_wd_in[352]
  PIN w0_wd_in[353]
    DIRECTION OUTPUT ;
    USE SIGNAL ;
    SHAPE ABUTMENT ;
    PORT
      LAYER metal3 ;
      RECT 340.305 0.000 340.375 0.210 ;
    END
  END w0_wd_in[353]
  PIN w0_wd_in[354]
    DIRECTION OUTPUT ;
    USE SIGNAL ;
    SHAPE ABUTMENT ;
    PORT
      LAYER metal3 ;
      RECT 343.805 0.000 343.875 0.210 ;
    END
  END w0_wd_in[354]
  PIN w0_wd_in[355]
    DIRECTION OUTPUT ;
    USE SIGNAL ;
    SHAPE ABUTMENT ;
    PORT
      LAYER metal3 ;
      RECT 347.305 0.000 347.375 0.210 ;
    END
  END w0_wd_in[355]
  PIN w0_wd_in[356]
    DIRECTION OUTPUT ;
    USE SIGNAL ;
    SHAPE ABUTMENT ;
    PORT
      LAYER metal3 ;
      RECT 350.805 0.000 350.875 0.210 ;
    END
  END w0_wd_in[356]
  PIN w0_wd_in[357]
    DIRECTION OUTPUT ;
    USE SIGNAL ;
    SHAPE ABUTMENT ;
    PORT
      LAYER metal3 ;
      RECT 354.305 0.000 354.375 0.210 ;
    END
  END w0_wd_in[357]
  PIN w0_wd_in[358]
    DIRECTION OUTPUT ;
    USE SIGNAL ;
    SHAPE ABUTMENT ;
    PORT
      LAYER metal3 ;
      RECT 357.805 0.000 357.875 0.210 ;
    END
  END w0_wd_in[358]
  PIN w0_wd_in[359]
    DIRECTION OUTPUT ;
    USE SIGNAL ;
    SHAPE ABUTMENT ;
    PORT
      LAYER metal3 ;
      RECT 361.305 0.000 361.375 0.210 ;
    END
  END w0_wd_in[359]
  PIN w0_wd_in[360]
    DIRECTION OUTPUT ;
    USE SIGNAL ;
    SHAPE ABUTMENT ;
    PORT
      LAYER metal3 ;
      RECT 364.805 0.000 364.875 0.210 ;
    END
  END w0_wd_in[360]
  PIN w0_wd_in[361]
    DIRECTION OUTPUT ;
    USE SIGNAL ;
    SHAPE ABUTMENT ;
    PORT
      LAYER metal3 ;
      RECT 368.305 0.000 368.375 0.210 ;
    END
  END w0_wd_in[361]
  PIN w0_wd_in[362]
    DIRECTION OUTPUT ;
    USE SIGNAL ;
    SHAPE ABUTMENT ;
    PORT
      LAYER metal3 ;
      RECT 371.805 0.000 371.875 0.210 ;
    END
  END w0_wd_in[362]
  PIN w0_wd_in[363]
    DIRECTION OUTPUT ;
    USE SIGNAL ;
    SHAPE ABUTMENT ;
    PORT
      LAYER metal3 ;
      RECT 375.305 0.000 375.375 0.210 ;
    END
  END w0_wd_in[363]
  PIN w0_wd_in[364]
    DIRECTION OUTPUT ;
    USE SIGNAL ;
    SHAPE ABUTMENT ;
    PORT
      LAYER metal3 ;
      RECT 378.805 0.000 378.875 0.210 ;
    END
  END w0_wd_in[364]
  PIN w0_wd_in[365]
    DIRECTION OUTPUT ;
    USE SIGNAL ;
    SHAPE ABUTMENT ;
    PORT
      LAYER metal3 ;
      RECT 382.305 0.000 382.375 0.210 ;
    END
  END w0_wd_in[365]
  PIN w0_wd_in[366]
    DIRECTION OUTPUT ;
    USE SIGNAL ;
    SHAPE ABUTMENT ;
    PORT
      LAYER metal3 ;
      RECT 385.805 0.000 385.875 0.210 ;
    END
  END w0_wd_in[366]
  PIN w0_wd_in[367]
    DIRECTION OUTPUT ;
    USE SIGNAL ;
    SHAPE ABUTMENT ;
    PORT
      LAYER metal3 ;
      RECT 389.305 0.000 389.375 0.210 ;
    END
  END w0_wd_in[367]
  PIN w0_wd_in[368]
    DIRECTION OUTPUT ;
    USE SIGNAL ;
    SHAPE ABUTMENT ;
    PORT
      LAYER metal3 ;
      RECT 392.805 0.000 392.875 0.210 ;
    END
  END w0_wd_in[368]
  PIN w0_wd_in[369]
    DIRECTION OUTPUT ;
    USE SIGNAL ;
    SHAPE ABUTMENT ;
    PORT
      LAYER metal3 ;
      RECT 396.305 0.000 396.375 0.210 ;
    END
  END w0_wd_in[369]
  PIN w0_wd_in[370]
    DIRECTION OUTPUT ;
    USE SIGNAL ;
    SHAPE ABUTMENT ;
    PORT
      LAYER metal3 ;
      RECT 399.805 0.000 399.875 0.210 ;
    END
  END w0_wd_in[370]
  PIN w0_wd_in[371]
    DIRECTION OUTPUT ;
    USE SIGNAL ;
    SHAPE ABUTMENT ;
    PORT
      LAYER metal3 ;
      RECT 403.305 0.000 403.375 0.210 ;
    END
  END w0_wd_in[371]
  PIN w0_wd_in[372]
    DIRECTION OUTPUT ;
    USE SIGNAL ;
    SHAPE ABUTMENT ;
    PORT
      LAYER metal3 ;
      RECT 406.805 0.000 406.875 0.210 ;
    END
  END w0_wd_in[372]
  PIN w0_wd_in[373]
    DIRECTION OUTPUT ;
    USE SIGNAL ;
    SHAPE ABUTMENT ;
    PORT
      LAYER metal3 ;
      RECT 410.305 0.000 410.375 0.210 ;
    END
  END w0_wd_in[373]
  PIN w0_wd_in[374]
    DIRECTION OUTPUT ;
    USE SIGNAL ;
    SHAPE ABUTMENT ;
    PORT
      LAYER metal3 ;
      RECT 413.805 0.000 413.875 0.210 ;
    END
  END w0_wd_in[374]
  PIN w0_wd_in[375]
    DIRECTION OUTPUT ;
    USE SIGNAL ;
    SHAPE ABUTMENT ;
    PORT
      LAYER metal3 ;
      RECT 417.305 0.000 417.375 0.210 ;
    END
  END w0_wd_in[375]
  PIN w0_wd_in[376]
    DIRECTION OUTPUT ;
    USE SIGNAL ;
    SHAPE ABUTMENT ;
    PORT
      LAYER metal3 ;
      RECT 420.805 0.000 420.875 0.210 ;
    END
  END w0_wd_in[376]
  PIN w0_wd_in[377]
    DIRECTION OUTPUT ;
    USE SIGNAL ;
    SHAPE ABUTMENT ;
    PORT
      LAYER metal3 ;
      RECT 424.305 0.000 424.375 0.210 ;
    END
  END w0_wd_in[377]
  PIN w0_wd_in[378]
    DIRECTION OUTPUT ;
    USE SIGNAL ;
    SHAPE ABUTMENT ;
    PORT
      LAYER metal3 ;
      RECT 427.805 0.000 427.875 0.210 ;
    END
  END w0_wd_in[378]
  PIN w0_wd_in[379]
    DIRECTION OUTPUT ;
    USE SIGNAL ;
    SHAPE ABUTMENT ;
    PORT
      LAYER metal3 ;
      RECT 431.305 0.000 431.375 0.210 ;
    END
  END w0_wd_in[379]
  PIN w0_wd_in[380]
    DIRECTION OUTPUT ;
    USE SIGNAL ;
    SHAPE ABUTMENT ;
    PORT
      LAYER metal3 ;
      RECT 434.805 0.000 434.875 0.210 ;
    END
  END w0_wd_in[380]
  PIN w0_wd_in[381]
    DIRECTION OUTPUT ;
    USE SIGNAL ;
    SHAPE ABUTMENT ;
    PORT
      LAYER metal3 ;
      RECT 438.305 0.000 438.375 0.210 ;
    END
  END w0_wd_in[381]
  PIN w0_wd_in[382]
    DIRECTION OUTPUT ;
    USE SIGNAL ;
    SHAPE ABUTMENT ;
    PORT
      LAYER metal3 ;
      RECT 441.805 0.000 441.875 0.210 ;
    END
  END w0_wd_in[382]
  PIN w0_wd_in[383]
    DIRECTION OUTPUT ;
    USE SIGNAL ;
    SHAPE ABUTMENT ;
    PORT
      LAYER metal3 ;
      RECT 445.305 0.000 445.375 0.210 ;
    END
  END w0_wd_in[383]
  PIN w0_wd_in[384]
    DIRECTION OUTPUT ;
    USE SIGNAL ;
    SHAPE ABUTMENT ;
    PORT
      LAYER metal3 ;
      RECT 448.805 0.000 448.875 0.210 ;
    END
  END w0_wd_in[384]
  PIN w0_wd_in[385]
    DIRECTION OUTPUT ;
    USE SIGNAL ;
    SHAPE ABUTMENT ;
    PORT
      LAYER metal3 ;
      RECT 452.305 0.000 452.375 0.210 ;
    END
  END w0_wd_in[385]
  PIN w0_wd_in[386]
    DIRECTION OUTPUT ;
    USE SIGNAL ;
    SHAPE ABUTMENT ;
    PORT
      LAYER metal3 ;
      RECT 455.805 0.000 455.875 0.210 ;
    END
  END w0_wd_in[386]
  PIN w0_wd_in[387]
    DIRECTION OUTPUT ;
    USE SIGNAL ;
    SHAPE ABUTMENT ;
    PORT
      LAYER metal3 ;
      RECT 459.305 0.000 459.375 0.210 ;
    END
  END w0_wd_in[387]
  PIN w0_wd_in[388]
    DIRECTION OUTPUT ;
    USE SIGNAL ;
    SHAPE ABUTMENT ;
    PORT
      LAYER metal3 ;
      RECT 462.805 0.000 462.875 0.210 ;
    END
  END w0_wd_in[388]
  PIN w0_wd_in[389]
    DIRECTION OUTPUT ;
    USE SIGNAL ;
    SHAPE ABUTMENT ;
    PORT
      LAYER metal3 ;
      RECT 466.305 0.000 466.375 0.210 ;
    END
  END w0_wd_in[389]
  PIN w0_wd_in[390]
    DIRECTION OUTPUT ;
    USE SIGNAL ;
    SHAPE ABUTMENT ;
    PORT
      LAYER metal3 ;
      RECT 469.805 0.000 469.875 0.210 ;
    END
  END w0_wd_in[390]
  PIN w0_wd_in[391]
    DIRECTION OUTPUT ;
    USE SIGNAL ;
    SHAPE ABUTMENT ;
    PORT
      LAYER metal3 ;
      RECT 473.305 0.000 473.375 0.210 ;
    END
  END w0_wd_in[391]
  PIN w0_wd_in[392]
    DIRECTION OUTPUT ;
    USE SIGNAL ;
    SHAPE ABUTMENT ;
    PORT
      LAYER metal3 ;
      RECT 476.805 0.000 476.875 0.210 ;
    END
  END w0_wd_in[392]
  PIN w0_wd_in[393]
    DIRECTION OUTPUT ;
    USE SIGNAL ;
    SHAPE ABUTMENT ;
    PORT
      LAYER metal3 ;
      RECT 480.305 0.000 480.375 0.210 ;
    END
  END w0_wd_in[393]
  PIN w0_wd_in[394]
    DIRECTION OUTPUT ;
    USE SIGNAL ;
    SHAPE ABUTMENT ;
    PORT
      LAYER metal3 ;
      RECT 483.805 0.000 483.875 0.210 ;
    END
  END w0_wd_in[394]
  PIN w0_wd_in[395]
    DIRECTION OUTPUT ;
    USE SIGNAL ;
    SHAPE ABUTMENT ;
    PORT
      LAYER metal3 ;
      RECT 487.305 0.000 487.375 0.210 ;
    END
  END w0_wd_in[395]
  PIN w0_wd_in[396]
    DIRECTION OUTPUT ;
    USE SIGNAL ;
    SHAPE ABUTMENT ;
    PORT
      LAYER metal3 ;
      RECT 490.805 0.000 490.875 0.210 ;
    END
  END w0_wd_in[396]
  PIN w0_wd_in[397]
    DIRECTION OUTPUT ;
    USE SIGNAL ;
    SHAPE ABUTMENT ;
    PORT
      LAYER metal3 ;
      RECT 494.305 0.000 494.375 0.210 ;
    END
  END w0_wd_in[397]
  PIN w0_wd_in[398]
    DIRECTION OUTPUT ;
    USE SIGNAL ;
    SHAPE ABUTMENT ;
    PORT
      LAYER metal3 ;
      RECT 497.805 0.000 497.875 0.210 ;
    END
  END w0_wd_in[398]
  PIN w0_wd_in[399]
    DIRECTION OUTPUT ;
    USE SIGNAL ;
    SHAPE ABUTMENT ;
    PORT
      LAYER metal3 ;
      RECT 501.305 0.000 501.375 0.210 ;
    END
  END w0_wd_in[399]
  PIN w0_wd_in[400]
    DIRECTION OUTPUT ;
    USE SIGNAL ;
    SHAPE ABUTMENT ;
    PORT
      LAYER metal3 ;
      RECT 504.805 0.000 504.875 0.210 ;
    END
  END w0_wd_in[400]
  PIN w0_wd_in[401]
    DIRECTION OUTPUT ;
    USE SIGNAL ;
    SHAPE ABUTMENT ;
    PORT
      LAYER metal3 ;
      RECT 508.305 0.000 508.375 0.210 ;
    END
  END w0_wd_in[401]
  PIN w0_wd_in[402]
    DIRECTION OUTPUT ;
    USE SIGNAL ;
    SHAPE ABUTMENT ;
    PORT
      LAYER metal3 ;
      RECT 511.805 0.000 511.875 0.210 ;
    END
  END w0_wd_in[402]
  PIN w0_wd_in[403]
    DIRECTION OUTPUT ;
    USE SIGNAL ;
    SHAPE ABUTMENT ;
    PORT
      LAYER metal3 ;
      RECT 515.305 0.000 515.375 0.210 ;
    END
  END w0_wd_in[403]
  PIN w0_wd_in[404]
    DIRECTION OUTPUT ;
    USE SIGNAL ;
    SHAPE ABUTMENT ;
    PORT
      LAYER metal3 ;
      RECT 518.805 0.000 518.875 0.210 ;
    END
  END w0_wd_in[404]
  PIN w0_wd_in[405]
    DIRECTION OUTPUT ;
    USE SIGNAL ;
    SHAPE ABUTMENT ;
    PORT
      LAYER metal3 ;
      RECT 522.305 0.000 522.375 0.210 ;
    END
  END w0_wd_in[405]
  PIN w0_wd_in[406]
    DIRECTION OUTPUT ;
    USE SIGNAL ;
    SHAPE ABUTMENT ;
    PORT
      LAYER metal3 ;
      RECT 525.805 0.000 525.875 0.210 ;
    END
  END w0_wd_in[406]
  PIN w0_wd_in[407]
    DIRECTION OUTPUT ;
    USE SIGNAL ;
    SHAPE ABUTMENT ;
    PORT
      LAYER metal3 ;
      RECT 529.305 0.000 529.375 0.210 ;
    END
  END w0_wd_in[407]
  PIN w0_wd_in[408]
    DIRECTION OUTPUT ;
    USE SIGNAL ;
    SHAPE ABUTMENT ;
    PORT
      LAYER metal3 ;
      RECT 532.805 0.000 532.875 0.210 ;
    END
  END w0_wd_in[408]
  PIN w0_wd_in[409]
    DIRECTION OUTPUT ;
    USE SIGNAL ;
    SHAPE ABUTMENT ;
    PORT
      LAYER metal3 ;
      RECT 536.305 0.000 536.375 0.210 ;
    END
  END w0_wd_in[409]
  PIN w0_wd_in[410]
    DIRECTION OUTPUT ;
    USE SIGNAL ;
    SHAPE ABUTMENT ;
    PORT
      LAYER metal3 ;
      RECT 539.805 0.000 539.875 0.210 ;
    END
  END w0_wd_in[410]
  PIN w0_wd_in[411]
    DIRECTION OUTPUT ;
    USE SIGNAL ;
    SHAPE ABUTMENT ;
    PORT
      LAYER metal3 ;
      RECT 543.305 0.000 543.375 0.210 ;
    END
  END w0_wd_in[411]
  PIN w0_wd_in[412]
    DIRECTION OUTPUT ;
    USE SIGNAL ;
    SHAPE ABUTMENT ;
    PORT
      LAYER metal3 ;
      RECT 546.805 0.000 546.875 0.210 ;
    END
  END w0_wd_in[412]
  PIN w0_wd_in[413]
    DIRECTION OUTPUT ;
    USE SIGNAL ;
    SHAPE ABUTMENT ;
    PORT
      LAYER metal3 ;
      RECT 550.305 0.000 550.375 0.210 ;
    END
  END w0_wd_in[413]
  PIN w0_wd_in[414]
    DIRECTION OUTPUT ;
    USE SIGNAL ;
    SHAPE ABUTMENT ;
    PORT
      LAYER metal3 ;
      RECT 553.805 0.000 553.875 0.210 ;
    END
  END w0_wd_in[414]
  PIN w0_wd_in[415]
    DIRECTION OUTPUT ;
    USE SIGNAL ;
    SHAPE ABUTMENT ;
    PORT
      LAYER metal3 ;
      RECT 557.305 0.000 557.375 0.210 ;
    END
  END w0_wd_in[415]
  PIN w0_wd_in[416]
    DIRECTION OUTPUT ;
    USE SIGNAL ;
    SHAPE ABUTMENT ;
    PORT
      LAYER metal3 ;
      RECT 560.805 0.000 560.875 0.210 ;
    END
  END w0_wd_in[416]
  PIN w0_wd_in[417]
    DIRECTION OUTPUT ;
    USE SIGNAL ;
    SHAPE ABUTMENT ;
    PORT
      LAYER metal3 ;
      RECT 564.305 0.000 564.375 0.210 ;
    END
  END w0_wd_in[417]
  PIN w0_wd_in[418]
    DIRECTION OUTPUT ;
    USE SIGNAL ;
    SHAPE ABUTMENT ;
    PORT
      LAYER metal3 ;
      RECT 567.805 0.000 567.875 0.210 ;
    END
  END w0_wd_in[418]
  PIN w0_wd_in[419]
    DIRECTION OUTPUT ;
    USE SIGNAL ;
    SHAPE ABUTMENT ;
    PORT
      LAYER metal3 ;
      RECT 571.305 0.000 571.375 0.210 ;
    END
  END w0_wd_in[419]
  PIN w0_wd_in[420]
    DIRECTION OUTPUT ;
    USE SIGNAL ;
    SHAPE ABUTMENT ;
    PORT
      LAYER metal3 ;
      RECT 574.805 0.000 574.875 0.210 ;
    END
  END w0_wd_in[420]
  PIN w0_wd_in[421]
    DIRECTION OUTPUT ;
    USE SIGNAL ;
    SHAPE ABUTMENT ;
    PORT
      LAYER metal3 ;
      RECT 578.305 0.000 578.375 0.210 ;
    END
  END w0_wd_in[421]
  PIN w0_wd_in[422]
    DIRECTION OUTPUT ;
    USE SIGNAL ;
    SHAPE ABUTMENT ;
    PORT
      LAYER metal3 ;
      RECT 581.805 0.000 581.875 0.210 ;
    END
  END w0_wd_in[422]
  PIN w0_wd_in[423]
    DIRECTION OUTPUT ;
    USE SIGNAL ;
    SHAPE ABUTMENT ;
    PORT
      LAYER metal3 ;
      RECT 585.305 0.000 585.375 0.210 ;
    END
  END w0_wd_in[423]
  PIN w0_wd_in[424]
    DIRECTION OUTPUT ;
    USE SIGNAL ;
    SHAPE ABUTMENT ;
    PORT
      LAYER metal3 ;
      RECT 588.805 0.000 588.875 0.210 ;
    END
  END w0_wd_in[424]
  PIN w0_wd_in[425]
    DIRECTION OUTPUT ;
    USE SIGNAL ;
    SHAPE ABUTMENT ;
    PORT
      LAYER metal3 ;
      RECT 592.305 0.000 592.375 0.210 ;
    END
  END w0_wd_in[425]
  PIN w0_wd_in[426]
    DIRECTION OUTPUT ;
    USE SIGNAL ;
    SHAPE ABUTMENT ;
    PORT
      LAYER metal3 ;
      RECT 595.805 0.000 595.875 0.210 ;
    END
  END w0_wd_in[426]
  PIN w0_wd_in[427]
    DIRECTION OUTPUT ;
    USE SIGNAL ;
    SHAPE ABUTMENT ;
    PORT
      LAYER metal3 ;
      RECT 599.305 0.000 599.375 0.210 ;
    END
  END w0_wd_in[427]
  PIN w0_wd_in[428]
    DIRECTION OUTPUT ;
    USE SIGNAL ;
    SHAPE ABUTMENT ;
    PORT
      LAYER metal3 ;
      RECT 602.805 0.000 602.875 0.210 ;
    END
  END w0_wd_in[428]
  PIN w0_wd_in[429]
    DIRECTION OUTPUT ;
    USE SIGNAL ;
    SHAPE ABUTMENT ;
    PORT
      LAYER metal3 ;
      RECT 606.305 0.000 606.375 0.210 ;
    END
  END w0_wd_in[429]
  PIN w0_wd_in[430]
    DIRECTION OUTPUT ;
    USE SIGNAL ;
    SHAPE ABUTMENT ;
    PORT
      LAYER metal3 ;
      RECT 609.805 0.000 609.875 0.210 ;
    END
  END w0_wd_in[430]
  PIN w0_wd_in[431]
    DIRECTION OUTPUT ;
    USE SIGNAL ;
    SHAPE ABUTMENT ;
    PORT
      LAYER metal3 ;
      RECT 613.305 0.000 613.375 0.210 ;
    END
  END w0_wd_in[431]
  PIN w0_wd_in[432]
    DIRECTION OUTPUT ;
    USE SIGNAL ;
    SHAPE ABUTMENT ;
    PORT
      LAYER metal3 ;
      RECT 616.805 0.000 616.875 0.210 ;
    END
  END w0_wd_in[432]
  PIN w0_wd_in[433]
    DIRECTION OUTPUT ;
    USE SIGNAL ;
    SHAPE ABUTMENT ;
    PORT
      LAYER metal3 ;
      RECT 620.305 0.000 620.375 0.210 ;
    END
  END w0_wd_in[433]
  PIN w0_wd_in[434]
    DIRECTION OUTPUT ;
    USE SIGNAL ;
    SHAPE ABUTMENT ;
    PORT
      LAYER metal3 ;
      RECT 623.805 0.000 623.875 0.210 ;
    END
  END w0_wd_in[434]
  PIN w0_wd_in[435]
    DIRECTION OUTPUT ;
    USE SIGNAL ;
    SHAPE ABUTMENT ;
    PORT
      LAYER metal3 ;
      RECT 627.305 0.000 627.375 0.210 ;
    END
  END w0_wd_in[435]
  PIN w0_wd_in[436]
    DIRECTION OUTPUT ;
    USE SIGNAL ;
    SHAPE ABUTMENT ;
    PORT
      LAYER metal3 ;
      RECT 630.805 0.000 630.875 0.210 ;
    END
  END w0_wd_in[436]
  PIN w0_wd_in[437]
    DIRECTION OUTPUT ;
    USE SIGNAL ;
    SHAPE ABUTMENT ;
    PORT
      LAYER metal3 ;
      RECT 634.305 0.000 634.375 0.210 ;
    END
  END w0_wd_in[437]
  PIN w0_wd_in[438]
    DIRECTION OUTPUT ;
    USE SIGNAL ;
    SHAPE ABUTMENT ;
    PORT
      LAYER metal3 ;
      RECT 637.805 0.000 637.875 0.210 ;
    END
  END w0_wd_in[438]
  PIN w0_wd_in[439]
    DIRECTION OUTPUT ;
    USE SIGNAL ;
    SHAPE ABUTMENT ;
    PORT
      LAYER metal3 ;
      RECT 641.305 0.000 641.375 0.210 ;
    END
  END w0_wd_in[439]
  PIN w0_wd_in[440]
    DIRECTION OUTPUT ;
    USE SIGNAL ;
    SHAPE ABUTMENT ;
    PORT
      LAYER metal3 ;
      RECT 644.805 0.000 644.875 0.210 ;
    END
  END w0_wd_in[440]
  PIN w0_wd_in[441]
    DIRECTION OUTPUT ;
    USE SIGNAL ;
    SHAPE ABUTMENT ;
    PORT
      LAYER metal3 ;
      RECT 648.305 0.000 648.375 0.210 ;
    END
  END w0_wd_in[441]
  PIN w0_wd_in[442]
    DIRECTION OUTPUT ;
    USE SIGNAL ;
    SHAPE ABUTMENT ;
    PORT
      LAYER metal3 ;
      RECT 651.805 0.000 651.875 0.210 ;
    END
  END w0_wd_in[442]
  PIN w0_wd_in[443]
    DIRECTION OUTPUT ;
    USE SIGNAL ;
    SHAPE ABUTMENT ;
    PORT
      LAYER metal3 ;
      RECT 655.305 0.000 655.375 0.210 ;
    END
  END w0_wd_in[443]
  PIN w0_wd_in[444]
    DIRECTION OUTPUT ;
    USE SIGNAL ;
    SHAPE ABUTMENT ;
    PORT
      LAYER metal3 ;
      RECT 658.805 0.000 658.875 0.210 ;
    END
  END w0_wd_in[444]
  PIN w0_wd_in[445]
    DIRECTION OUTPUT ;
    USE SIGNAL ;
    SHAPE ABUTMENT ;
    PORT
      LAYER metal3 ;
      RECT 662.305 0.000 662.375 0.210 ;
    END
  END w0_wd_in[445]
  PIN w0_wd_in[446]
    DIRECTION OUTPUT ;
    USE SIGNAL ;
    SHAPE ABUTMENT ;
    PORT
      LAYER metal3 ;
      RECT 665.805 0.000 665.875 0.210 ;
    END
  END w0_wd_in[446]
  PIN w0_wd_in[447]
    DIRECTION OUTPUT ;
    USE SIGNAL ;
    SHAPE ABUTMENT ;
    PORT
      LAYER metal3 ;
      RECT 669.305 0.000 669.375 0.210 ;
    END
  END w0_wd_in[447]
  PIN w0_wd_in[448]
    DIRECTION OUTPUT ;
    USE SIGNAL ;
    SHAPE ABUTMENT ;
    PORT
      LAYER metal3 ;
      RECT 672.805 0.000 672.875 0.210 ;
    END
  END w0_wd_in[448]
  PIN w0_wd_in[449]
    DIRECTION OUTPUT ;
    USE SIGNAL ;
    SHAPE ABUTMENT ;
    PORT
      LAYER metal3 ;
      RECT 676.305 0.000 676.375 0.210 ;
    END
  END w0_wd_in[449]
  PIN w0_wd_in[450]
    DIRECTION OUTPUT ;
    USE SIGNAL ;
    SHAPE ABUTMENT ;
    PORT
      LAYER metal3 ;
      RECT 679.805 0.000 679.875 0.210 ;
    END
  END w0_wd_in[450]
  PIN w0_wd_in[451]
    DIRECTION OUTPUT ;
    USE SIGNAL ;
    SHAPE ABUTMENT ;
    PORT
      LAYER metal3 ;
      RECT 683.305 0.000 683.375 0.210 ;
    END
  END w0_wd_in[451]
  PIN w0_wd_in[452]
    DIRECTION OUTPUT ;
    USE SIGNAL ;
    SHAPE ABUTMENT ;
    PORT
      LAYER metal3 ;
      RECT 686.805 0.000 686.875 0.210 ;
    END
  END w0_wd_in[452]
  PIN w0_wd_in[453]
    DIRECTION OUTPUT ;
    USE SIGNAL ;
    SHAPE ABUTMENT ;
    PORT
      LAYER metal3 ;
      RECT 690.305 0.000 690.375 0.210 ;
    END
  END w0_wd_in[453]
  PIN w0_wd_in[454]
    DIRECTION OUTPUT ;
    USE SIGNAL ;
    SHAPE ABUTMENT ;
    PORT
      LAYER metal3 ;
      RECT 693.805 0.000 693.875 0.210 ;
    END
  END w0_wd_in[454]
  PIN w0_wd_in[455]
    DIRECTION OUTPUT ;
    USE SIGNAL ;
    SHAPE ABUTMENT ;
    PORT
      LAYER metal3 ;
      RECT 697.305 0.000 697.375 0.210 ;
    END
  END w0_wd_in[455]
  PIN w0_wd_in[456]
    DIRECTION OUTPUT ;
    USE SIGNAL ;
    SHAPE ABUTMENT ;
    PORT
      LAYER metal3 ;
      RECT 700.805 0.000 700.875 0.210 ;
    END
  END w0_wd_in[456]
  PIN w0_wd_in[457]
    DIRECTION OUTPUT ;
    USE SIGNAL ;
    SHAPE ABUTMENT ;
    PORT
      LAYER metal3 ;
      RECT 704.305 0.000 704.375 0.210 ;
    END
  END w0_wd_in[457]
  PIN w0_wd_in[458]
    DIRECTION OUTPUT ;
    USE SIGNAL ;
    SHAPE ABUTMENT ;
    PORT
      LAYER metal3 ;
      RECT 707.805 0.000 707.875 0.210 ;
    END
  END w0_wd_in[458]
  PIN w0_wd_in[459]
    DIRECTION OUTPUT ;
    USE SIGNAL ;
    SHAPE ABUTMENT ;
    PORT
      LAYER metal3 ;
      RECT 711.305 0.000 711.375 0.210 ;
    END
  END w0_wd_in[459]
  PIN w0_wd_in[460]
    DIRECTION OUTPUT ;
    USE SIGNAL ;
    SHAPE ABUTMENT ;
    PORT
      LAYER metal3 ;
      RECT 714.805 0.000 714.875 0.210 ;
    END
  END w0_wd_in[460]
  PIN w0_wd_in[461]
    DIRECTION OUTPUT ;
    USE SIGNAL ;
    SHAPE ABUTMENT ;
    PORT
      LAYER metal3 ;
      RECT 718.305 0.000 718.375 0.210 ;
    END
  END w0_wd_in[461]
  PIN w0_wd_in[462]
    DIRECTION OUTPUT ;
    USE SIGNAL ;
    SHAPE ABUTMENT ;
    PORT
      LAYER metal3 ;
      RECT 721.805 0.000 721.875 0.210 ;
    END
  END w0_wd_in[462]
  PIN w0_wd_in[463]
    DIRECTION OUTPUT ;
    USE SIGNAL ;
    SHAPE ABUTMENT ;
    PORT
      LAYER metal3 ;
      RECT 725.305 0.000 725.375 0.210 ;
    END
  END w0_wd_in[463]
  PIN w0_wd_in[464]
    DIRECTION OUTPUT ;
    USE SIGNAL ;
    SHAPE ABUTMENT ;
    PORT
      LAYER metal3 ;
      RECT 728.805 0.000 728.875 0.210 ;
    END
  END w0_wd_in[464]
  PIN w0_wd_in[465]
    DIRECTION OUTPUT ;
    USE SIGNAL ;
    SHAPE ABUTMENT ;
    PORT
      LAYER metal3 ;
      RECT 732.305 0.000 732.375 0.210 ;
    END
  END w0_wd_in[465]
  PIN w0_wd_in[466]
    DIRECTION OUTPUT ;
    USE SIGNAL ;
    SHAPE ABUTMENT ;
    PORT
      LAYER metal3 ;
      RECT 735.805 0.000 735.875 0.210 ;
    END
  END w0_wd_in[466]
  PIN w0_wd_in[467]
    DIRECTION OUTPUT ;
    USE SIGNAL ;
    SHAPE ABUTMENT ;
    PORT
      LAYER metal3 ;
      RECT 739.305 0.000 739.375 0.210 ;
    END
  END w0_wd_in[467]
  PIN w0_wd_in[468]
    DIRECTION OUTPUT ;
    USE SIGNAL ;
    SHAPE ABUTMENT ;
    PORT
      LAYER metal3 ;
      RECT 742.805 0.000 742.875 0.210 ;
    END
  END w0_wd_in[468]
  PIN w0_wd_in[469]
    DIRECTION OUTPUT ;
    USE SIGNAL ;
    SHAPE ABUTMENT ;
    PORT
      LAYER metal3 ;
      RECT 746.305 0.000 746.375 0.210 ;
    END
  END w0_wd_in[469]
  PIN w0_wd_in[470]
    DIRECTION OUTPUT ;
    USE SIGNAL ;
    SHAPE ABUTMENT ;
    PORT
      LAYER metal3 ;
      RECT 749.805 0.000 749.875 0.210 ;
    END
  END w0_wd_in[470]
  PIN w0_wd_in[471]
    DIRECTION OUTPUT ;
    USE SIGNAL ;
    SHAPE ABUTMENT ;
    PORT
      LAYER metal3 ;
      RECT 753.305 0.000 753.375 0.210 ;
    END
  END w0_wd_in[471]
  PIN w0_wd_in[472]
    DIRECTION OUTPUT ;
    USE SIGNAL ;
    SHAPE ABUTMENT ;
    PORT
      LAYER metal3 ;
      RECT 756.805 0.000 756.875 0.210 ;
    END
  END w0_wd_in[472]
  PIN w0_wd_in[473]
    DIRECTION OUTPUT ;
    USE SIGNAL ;
    SHAPE ABUTMENT ;
    PORT
      LAYER metal3 ;
      RECT 760.305 0.000 760.375 0.210 ;
    END
  END w0_wd_in[473]
  PIN w0_wd_in[474]
    DIRECTION OUTPUT ;
    USE SIGNAL ;
    SHAPE ABUTMENT ;
    PORT
      LAYER metal3 ;
      RECT 763.805 0.000 763.875 0.210 ;
    END
  END w0_wd_in[474]
  PIN w0_wd_in[475]
    DIRECTION OUTPUT ;
    USE SIGNAL ;
    SHAPE ABUTMENT ;
    PORT
      LAYER metal3 ;
      RECT 767.305 0.000 767.375 0.210 ;
    END
  END w0_wd_in[475]
  PIN w0_wd_in[476]
    DIRECTION OUTPUT ;
    USE SIGNAL ;
    SHAPE ABUTMENT ;
    PORT
      LAYER metal3 ;
      RECT 770.805 0.000 770.875 0.210 ;
    END
  END w0_wd_in[476]
  PIN w0_wd_in[477]
    DIRECTION OUTPUT ;
    USE SIGNAL ;
    SHAPE ABUTMENT ;
    PORT
      LAYER metal3 ;
      RECT 774.305 0.000 774.375 0.210 ;
    END
  END w0_wd_in[477]
  PIN w0_wd_in[478]
    DIRECTION OUTPUT ;
    USE SIGNAL ;
    SHAPE ABUTMENT ;
    PORT
      LAYER metal3 ;
      RECT 777.805 0.000 777.875 0.210 ;
    END
  END w0_wd_in[478]
  PIN w0_wd_in[479]
    DIRECTION OUTPUT ;
    USE SIGNAL ;
    SHAPE ABUTMENT ;
    PORT
      LAYER metal3 ;
      RECT 781.305 0.000 781.375 0.210 ;
    END
  END w0_wd_in[479]
  PIN w0_wd_in[480]
    DIRECTION OUTPUT ;
    USE SIGNAL ;
    SHAPE ABUTMENT ;
    PORT
      LAYER metal3 ;
      RECT 784.805 0.000 784.875 0.210 ;
    END
  END w0_wd_in[480]
  PIN w0_wd_in[481]
    DIRECTION OUTPUT ;
    USE SIGNAL ;
    SHAPE ABUTMENT ;
    PORT
      LAYER metal3 ;
      RECT 788.305 0.000 788.375 0.210 ;
    END
  END w0_wd_in[481]
  PIN w0_wd_in[482]
    DIRECTION OUTPUT ;
    USE SIGNAL ;
    SHAPE ABUTMENT ;
    PORT
      LAYER metal3 ;
      RECT 791.805 0.000 791.875 0.210 ;
    END
  END w0_wd_in[482]
  PIN w0_wd_in[483]
    DIRECTION OUTPUT ;
    USE SIGNAL ;
    SHAPE ABUTMENT ;
    PORT
      LAYER metal3 ;
      RECT 795.305 0.000 795.375 0.210 ;
    END
  END w0_wd_in[483]
  PIN w0_wd_in[484]
    DIRECTION OUTPUT ;
    USE SIGNAL ;
    SHAPE ABUTMENT ;
    PORT
      LAYER metal3 ;
      RECT 798.805 0.000 798.875 0.210 ;
    END
  END w0_wd_in[484]
  PIN w0_wd_in[485]
    DIRECTION OUTPUT ;
    USE SIGNAL ;
    SHAPE ABUTMENT ;
    PORT
      LAYER metal3 ;
      RECT 802.305 0.000 802.375 0.210 ;
    END
  END w0_wd_in[485]
  PIN w0_wd_in[486]
    DIRECTION OUTPUT ;
    USE SIGNAL ;
    SHAPE ABUTMENT ;
    PORT
      LAYER metal3 ;
      RECT 805.805 0.000 805.875 0.210 ;
    END
  END w0_wd_in[486]
  PIN w0_wd_in[487]
    DIRECTION OUTPUT ;
    USE SIGNAL ;
    SHAPE ABUTMENT ;
    PORT
      LAYER metal3 ;
      RECT 809.305 0.000 809.375 0.210 ;
    END
  END w0_wd_in[487]
  PIN w0_wd_in[488]
    DIRECTION OUTPUT ;
    USE SIGNAL ;
    SHAPE ABUTMENT ;
    PORT
      LAYER metal3 ;
      RECT 812.805 0.000 812.875 0.210 ;
    END
  END w0_wd_in[488]
  PIN w0_wd_in[489]
    DIRECTION OUTPUT ;
    USE SIGNAL ;
    SHAPE ABUTMENT ;
    PORT
      LAYER metal3 ;
      RECT 816.305 0.000 816.375 0.210 ;
    END
  END w0_wd_in[489]
  PIN w0_wd_in[490]
    DIRECTION OUTPUT ;
    USE SIGNAL ;
    SHAPE ABUTMENT ;
    PORT
      LAYER metal3 ;
      RECT 819.805 0.000 819.875 0.210 ;
    END
  END w0_wd_in[490]
  PIN w0_wd_in[491]
    DIRECTION OUTPUT ;
    USE SIGNAL ;
    SHAPE ABUTMENT ;
    PORT
      LAYER metal3 ;
      RECT 823.305 0.000 823.375 0.210 ;
    END
  END w0_wd_in[491]
  PIN w0_wd_in[492]
    DIRECTION OUTPUT ;
    USE SIGNAL ;
    SHAPE ABUTMENT ;
    PORT
      LAYER metal3 ;
      RECT 826.805 0.000 826.875 0.210 ;
    END
  END w0_wd_in[492]
  PIN w0_wd_in[493]
    DIRECTION OUTPUT ;
    USE SIGNAL ;
    SHAPE ABUTMENT ;
    PORT
      LAYER metal3 ;
      RECT 830.305 0.000 830.375 0.210 ;
    END
  END w0_wd_in[493]
  PIN w0_wd_in[494]
    DIRECTION OUTPUT ;
    USE SIGNAL ;
    SHAPE ABUTMENT ;
    PORT
      LAYER metal3 ;
      RECT 833.805 0.000 833.875 0.210 ;
    END
  END w0_wd_in[494]
  PIN w0_wd_in[495]
    DIRECTION OUTPUT ;
    USE SIGNAL ;
    SHAPE ABUTMENT ;
    PORT
      LAYER metal3 ;
      RECT 837.305 0.000 837.375 0.210 ;
    END
  END w0_wd_in[495]
  PIN w0_wd_in[496]
    DIRECTION OUTPUT ;
    USE SIGNAL ;
    SHAPE ABUTMENT ;
    PORT
      LAYER metal3 ;
      RECT 840.805 0.000 840.875 0.210 ;
    END
  END w0_wd_in[496]
  PIN w0_wd_in[497]
    DIRECTION OUTPUT ;
    USE SIGNAL ;
    SHAPE ABUTMENT ;
    PORT
      LAYER metal3 ;
      RECT 844.305 0.000 844.375 0.210 ;
    END
  END w0_wd_in[497]
  PIN w0_wd_in[498]
    DIRECTION OUTPUT ;
    USE SIGNAL ;
    SHAPE ABUTMENT ;
    PORT
      LAYER metal3 ;
      RECT 847.805 0.000 847.875 0.210 ;
    END
  END w0_wd_in[498]
  PIN w0_wd_in[499]
    DIRECTION OUTPUT ;
    USE SIGNAL ;
    SHAPE ABUTMENT ;
    PORT
      LAYER metal3 ;
      RECT 851.305 0.000 851.375 0.210 ;
    END
  END w0_wd_in[499]
  PIN w0_wd_in[500]
    DIRECTION OUTPUT ;
    USE SIGNAL ;
    SHAPE ABUTMENT ;
    PORT
      LAYER metal3 ;
      RECT 854.805 0.000 854.875 0.210 ;
    END
  END w0_wd_in[500]
  PIN w0_wd_in[501]
    DIRECTION OUTPUT ;
    USE SIGNAL ;
    SHAPE ABUTMENT ;
    PORT
      LAYER metal3 ;
      RECT 858.305 0.000 858.375 0.210 ;
    END
  END w0_wd_in[501]
  PIN w0_wd_in[502]
    DIRECTION OUTPUT ;
    USE SIGNAL ;
    SHAPE ABUTMENT ;
    PORT
      LAYER metal3 ;
      RECT 861.805 0.000 861.875 0.210 ;
    END
  END w0_wd_in[502]
  PIN w0_wd_in[503]
    DIRECTION OUTPUT ;
    USE SIGNAL ;
    SHAPE ABUTMENT ;
    PORT
      LAYER metal3 ;
      RECT 865.305 0.000 865.375 0.210 ;
    END
  END w0_wd_in[503]
  PIN w0_wd_in[504]
    DIRECTION OUTPUT ;
    USE SIGNAL ;
    SHAPE ABUTMENT ;
    PORT
      LAYER metal3 ;
      RECT 868.805 0.000 868.875 0.210 ;
    END
  END w0_wd_in[504]
  PIN w0_wd_in[505]
    DIRECTION OUTPUT ;
    USE SIGNAL ;
    SHAPE ABUTMENT ;
    PORT
      LAYER metal3 ;
      RECT 872.305 0.000 872.375 0.210 ;
    END
  END w0_wd_in[505]
  PIN w0_wd_in[506]
    DIRECTION OUTPUT ;
    USE SIGNAL ;
    SHAPE ABUTMENT ;
    PORT
      LAYER metal3 ;
      RECT 875.805 0.000 875.875 0.210 ;
    END
  END w0_wd_in[506]
  PIN w0_wd_in[507]
    DIRECTION OUTPUT ;
    USE SIGNAL ;
    SHAPE ABUTMENT ;
    PORT
      LAYER metal3 ;
      RECT 879.305 0.000 879.375 0.210 ;
    END
  END w0_wd_in[507]
  PIN w0_wd_in[508]
    DIRECTION OUTPUT ;
    USE SIGNAL ;
    SHAPE ABUTMENT ;
    PORT
      LAYER metal3 ;
      RECT 882.805 0.000 882.875 0.210 ;
    END
  END w0_wd_in[508]
  PIN w0_wd_in[509]
    DIRECTION OUTPUT ;
    USE SIGNAL ;
    SHAPE ABUTMENT ;
    PORT
      LAYER metal3 ;
      RECT 886.305 0.000 886.375 0.210 ;
    END
  END w0_wd_in[509]
  PIN w0_wd_in[510]
    DIRECTION OUTPUT ;
    USE SIGNAL ;
    SHAPE ABUTMENT ;
    PORT
      LAYER metal3 ;
      RECT 889.805 0.000 889.875 0.210 ;
    END
  END w0_wd_in[510]
  PIN w0_wd_in[511]
    DIRECTION OUTPUT ;
    USE SIGNAL ;
    SHAPE ABUTMENT ;
    PORT
      LAYER metal3 ;
      RECT 893.305 0.000 893.375 0.210 ;
    END
  END w0_wd_in[511]
  PIN r0_rd_out[0]
    DIRECTION OUTPUT ;
    USE SIGNAL ;
    SHAPE ABUTMENT ;
    PORT
      LAYER metal3 ;
      RECT 896.805 0.000 896.875 0.210 ;
    END
  END r0_rd_out[0]
  PIN r0_rd_out[1]
    DIRECTION OUTPUT ;
    USE SIGNAL ;
    SHAPE ABUTMENT ;
    PORT
      LAYER metal3 ;
      RECT 900.305 0.000 900.375 0.210 ;
    END
  END r0_rd_out[1]
  PIN r0_rd_out[2]
    DIRECTION OUTPUT ;
    USE SIGNAL ;
    SHAPE ABUTMENT ;
    PORT
      LAYER metal3 ;
      RECT 903.805 0.000 903.875 0.210 ;
    END
  END r0_rd_out[2]
  PIN r0_rd_out[3]
    DIRECTION OUTPUT ;
    USE SIGNAL ;
    SHAPE ABUTMENT ;
    PORT
      LAYER metal3 ;
      RECT 907.305 0.000 907.375 0.210 ;
    END
  END r0_rd_out[3]
  PIN r0_rd_out[4]
    DIRECTION OUTPUT ;
    USE SIGNAL ;
    SHAPE ABUTMENT ;
    PORT
      LAYER metal3 ;
      RECT 910.805 0.000 910.875 0.210 ;
    END
  END r0_rd_out[4]
  PIN r0_rd_out[5]
    DIRECTION OUTPUT ;
    USE SIGNAL ;
    SHAPE ABUTMENT ;
    PORT
      LAYER metal3 ;
      RECT 914.305 0.000 914.375 0.210 ;
    END
  END r0_rd_out[5]
  PIN r0_rd_out[6]
    DIRECTION OUTPUT ;
    USE SIGNAL ;
    SHAPE ABUTMENT ;
    PORT
      LAYER metal3 ;
      RECT 917.805 0.000 917.875 0.210 ;
    END
  END r0_rd_out[6]
  PIN r0_rd_out[7]
    DIRECTION OUTPUT ;
    USE SIGNAL ;
    SHAPE ABUTMENT ;
    PORT
      LAYER metal3 ;
      RECT 921.305 0.000 921.375 0.210 ;
    END
  END r0_rd_out[7]
  PIN r0_rd_out[8]
    DIRECTION OUTPUT ;
    USE SIGNAL ;
    SHAPE ABUTMENT ;
    PORT
      LAYER metal3 ;
      RECT 924.805 0.000 924.875 0.210 ;
    END
  END r0_rd_out[8]
  PIN r0_rd_out[9]
    DIRECTION OUTPUT ;
    USE SIGNAL ;
    SHAPE ABUTMENT ;
    PORT
      LAYER metal3 ;
      RECT 928.305 0.000 928.375 0.210 ;
    END
  END r0_rd_out[9]
  PIN r0_rd_out[10]
    DIRECTION OUTPUT ;
    USE SIGNAL ;
    SHAPE ABUTMENT ;
    PORT
      LAYER metal3 ;
      RECT 931.805 0.000 931.875 0.210 ;
    END
  END r0_rd_out[10]
  PIN r0_rd_out[11]
    DIRECTION OUTPUT ;
    USE SIGNAL ;
    SHAPE ABUTMENT ;
    PORT
      LAYER metal3 ;
      RECT 935.305 0.000 935.375 0.210 ;
    END
  END r0_rd_out[11]
  PIN r0_rd_out[12]
    DIRECTION OUTPUT ;
    USE SIGNAL ;
    SHAPE ABUTMENT ;
    PORT
      LAYER metal3 ;
      RECT 938.805 0.000 938.875 0.210 ;
    END
  END r0_rd_out[12]
  PIN r0_rd_out[13]
    DIRECTION OUTPUT ;
    USE SIGNAL ;
    SHAPE ABUTMENT ;
    PORT
      LAYER metal3 ;
      RECT 942.305 0.000 942.375 0.210 ;
    END
  END r0_rd_out[13]
  PIN r0_rd_out[14]
    DIRECTION OUTPUT ;
    USE SIGNAL ;
    SHAPE ABUTMENT ;
    PORT
      LAYER metal3 ;
      RECT 945.805 0.000 945.875 0.210 ;
    END
  END r0_rd_out[14]
  PIN r0_rd_out[15]
    DIRECTION OUTPUT ;
    USE SIGNAL ;
    SHAPE ABUTMENT ;
    PORT
      LAYER metal3 ;
      RECT 949.305 0.000 949.375 0.210 ;
    END
  END r0_rd_out[15]
  PIN r0_rd_out[16]
    DIRECTION OUTPUT ;
    USE SIGNAL ;
    SHAPE ABUTMENT ;
    PORT
      LAYER metal3 ;
      RECT 952.805 0.000 952.875 0.210 ;
    END
  END r0_rd_out[16]
  PIN r0_rd_out[17]
    DIRECTION OUTPUT ;
    USE SIGNAL ;
    SHAPE ABUTMENT ;
    PORT
      LAYER metal3 ;
      RECT 956.305 0.000 956.375 0.210 ;
    END
  END r0_rd_out[17]
  PIN r0_rd_out[18]
    DIRECTION OUTPUT ;
    USE SIGNAL ;
    SHAPE ABUTMENT ;
    PORT
      LAYER metal3 ;
      RECT 959.805 0.000 959.875 0.210 ;
    END
  END r0_rd_out[18]
  PIN r0_rd_out[19]
    DIRECTION OUTPUT ;
    USE SIGNAL ;
    SHAPE ABUTMENT ;
    PORT
      LAYER metal3 ;
      RECT 963.305 0.000 963.375 0.210 ;
    END
  END r0_rd_out[19]
  PIN r0_rd_out[20]
    DIRECTION OUTPUT ;
    USE SIGNAL ;
    SHAPE ABUTMENT ;
    PORT
      LAYER metal3 ;
      RECT 966.805 0.000 966.875 0.210 ;
    END
  END r0_rd_out[20]
  PIN r0_rd_out[21]
    DIRECTION OUTPUT ;
    USE SIGNAL ;
    SHAPE ABUTMENT ;
    PORT
      LAYER metal3 ;
      RECT 970.305 0.000 970.375 0.210 ;
    END
  END r0_rd_out[21]
  PIN r0_rd_out[22]
    DIRECTION OUTPUT ;
    USE SIGNAL ;
    SHAPE ABUTMENT ;
    PORT
      LAYER metal3 ;
      RECT 973.805 0.000 973.875 0.210 ;
    END
  END r0_rd_out[22]
  PIN r0_rd_out[23]
    DIRECTION OUTPUT ;
    USE SIGNAL ;
    SHAPE ABUTMENT ;
    PORT
      LAYER metal3 ;
      RECT 977.305 0.000 977.375 0.210 ;
    END
  END r0_rd_out[23]
  PIN r0_rd_out[24]
    DIRECTION OUTPUT ;
    USE SIGNAL ;
    SHAPE ABUTMENT ;
    PORT
      LAYER metal3 ;
      RECT 980.805 0.000 980.875 0.210 ;
    END
  END r0_rd_out[24]
  PIN r0_rd_out[25]
    DIRECTION OUTPUT ;
    USE SIGNAL ;
    SHAPE ABUTMENT ;
    PORT
      LAYER metal3 ;
      RECT 984.305 0.000 984.375 0.210 ;
    END
  END r0_rd_out[25]
  PIN r0_rd_out[26]
    DIRECTION OUTPUT ;
    USE SIGNAL ;
    SHAPE ABUTMENT ;
    PORT
      LAYER metal3 ;
      RECT 987.805 0.000 987.875 0.210 ;
    END
  END r0_rd_out[26]
  PIN r0_rd_out[27]
    DIRECTION OUTPUT ;
    USE SIGNAL ;
    SHAPE ABUTMENT ;
    PORT
      LAYER metal3 ;
      RECT 991.305 0.000 991.375 0.210 ;
    END
  END r0_rd_out[27]
  PIN r0_rd_out[28]
    DIRECTION OUTPUT ;
    USE SIGNAL ;
    SHAPE ABUTMENT ;
    PORT
      LAYER metal3 ;
      RECT 994.805 0.000 994.875 0.210 ;
    END
  END r0_rd_out[28]
  PIN r0_rd_out[29]
    DIRECTION OUTPUT ;
    USE SIGNAL ;
    SHAPE ABUTMENT ;
    PORT
      LAYER metal3 ;
      RECT 998.305 0.000 998.375 0.210 ;
    END
  END r0_rd_out[29]
  PIN r0_rd_out[30]
    DIRECTION OUTPUT ;
    USE SIGNAL ;
    SHAPE ABUTMENT ;
    PORT
      LAYER metal3 ;
      RECT 1001.805 0.000 1001.875 0.210 ;
    END
  END r0_rd_out[30]
  PIN r0_rd_out[31]
    DIRECTION OUTPUT ;
    USE SIGNAL ;
    SHAPE ABUTMENT ;
    PORT
      LAYER metal3 ;
      RECT 1005.305 0.000 1005.375 0.210 ;
    END
  END r0_rd_out[31]
  PIN r0_rd_out[32]
    DIRECTION OUTPUT ;
    USE SIGNAL ;
    SHAPE ABUTMENT ;
    PORT
      LAYER metal3 ;
      RECT 1008.805 0.000 1008.875 0.210 ;
    END
  END r0_rd_out[32]
  PIN r0_rd_out[33]
    DIRECTION OUTPUT ;
    USE SIGNAL ;
    SHAPE ABUTMENT ;
    PORT
      LAYER metal3 ;
      RECT 1012.305 0.000 1012.375 0.210 ;
    END
  END r0_rd_out[33]
  PIN r0_rd_out[34]
    DIRECTION OUTPUT ;
    USE SIGNAL ;
    SHAPE ABUTMENT ;
    PORT
      LAYER metal3 ;
      RECT 1015.805 0.000 1015.875 0.210 ;
    END
  END r0_rd_out[34]
  PIN r0_rd_out[35]
    DIRECTION OUTPUT ;
    USE SIGNAL ;
    SHAPE ABUTMENT ;
    PORT
      LAYER metal3 ;
      RECT 1019.305 0.000 1019.375 0.210 ;
    END
  END r0_rd_out[35]
  PIN r0_rd_out[36]
    DIRECTION OUTPUT ;
    USE SIGNAL ;
    SHAPE ABUTMENT ;
    PORT
      LAYER metal3 ;
      RECT 1022.805 0.000 1022.875 0.210 ;
    END
  END r0_rd_out[36]
  PIN r0_rd_out[37]
    DIRECTION OUTPUT ;
    USE SIGNAL ;
    SHAPE ABUTMENT ;
    PORT
      LAYER metal3 ;
      RECT 1026.305 0.000 1026.375 0.210 ;
    END
  END r0_rd_out[37]
  PIN r0_rd_out[38]
    DIRECTION OUTPUT ;
    USE SIGNAL ;
    SHAPE ABUTMENT ;
    PORT
      LAYER metal3 ;
      RECT 1029.805 0.000 1029.875 0.210 ;
    END
  END r0_rd_out[38]
  PIN r0_rd_out[39]
    DIRECTION OUTPUT ;
    USE SIGNAL ;
    SHAPE ABUTMENT ;
    PORT
      LAYER metal3 ;
      RECT 1033.305 0.000 1033.375 0.210 ;
    END
  END r0_rd_out[39]
  PIN r0_rd_out[40]
    DIRECTION OUTPUT ;
    USE SIGNAL ;
    SHAPE ABUTMENT ;
    PORT
      LAYER metal3 ;
      RECT 1036.805 0.000 1036.875 0.210 ;
    END
  END r0_rd_out[40]
  PIN r0_rd_out[41]
    DIRECTION OUTPUT ;
    USE SIGNAL ;
    SHAPE ABUTMENT ;
    PORT
      LAYER metal3 ;
      RECT 1040.305 0.000 1040.375 0.210 ;
    END
  END r0_rd_out[41]
  PIN r0_rd_out[42]
    DIRECTION OUTPUT ;
    USE SIGNAL ;
    SHAPE ABUTMENT ;
    PORT
      LAYER metal3 ;
      RECT 1043.805 0.000 1043.875 0.210 ;
    END
  END r0_rd_out[42]
  PIN r0_rd_out[43]
    DIRECTION OUTPUT ;
    USE SIGNAL ;
    SHAPE ABUTMENT ;
    PORT
      LAYER metal3 ;
      RECT 1047.305 0.000 1047.375 0.210 ;
    END
  END r0_rd_out[43]
  PIN r0_rd_out[44]
    DIRECTION OUTPUT ;
    USE SIGNAL ;
    SHAPE ABUTMENT ;
    PORT
      LAYER metal3 ;
      RECT 1050.805 0.000 1050.875 0.210 ;
    END
  END r0_rd_out[44]
  PIN r0_rd_out[45]
    DIRECTION OUTPUT ;
    USE SIGNAL ;
    SHAPE ABUTMENT ;
    PORT
      LAYER metal3 ;
      RECT 1054.305 0.000 1054.375 0.210 ;
    END
  END r0_rd_out[45]
  PIN r0_rd_out[46]
    DIRECTION OUTPUT ;
    USE SIGNAL ;
    SHAPE ABUTMENT ;
    PORT
      LAYER metal3 ;
      RECT 1057.805 0.000 1057.875 0.210 ;
    END
  END r0_rd_out[46]
  PIN r0_rd_out[47]
    DIRECTION OUTPUT ;
    USE SIGNAL ;
    SHAPE ABUTMENT ;
    PORT
      LAYER metal3 ;
      RECT 1061.305 0.000 1061.375 0.210 ;
    END
  END r0_rd_out[47]
  PIN r0_rd_out[48]
    DIRECTION OUTPUT ;
    USE SIGNAL ;
    SHAPE ABUTMENT ;
    PORT
      LAYER metal3 ;
      RECT 1064.805 0.000 1064.875 0.210 ;
    END
  END r0_rd_out[48]
  PIN r0_rd_out[49]
    DIRECTION OUTPUT ;
    USE SIGNAL ;
    SHAPE ABUTMENT ;
    PORT
      LAYER metal3 ;
      RECT 1068.305 0.000 1068.375 0.210 ;
    END
  END r0_rd_out[49]
  PIN r0_rd_out[50]
    DIRECTION OUTPUT ;
    USE SIGNAL ;
    SHAPE ABUTMENT ;
    PORT
      LAYER metal3 ;
      RECT 1071.805 0.000 1071.875 0.210 ;
    END
  END r0_rd_out[50]
  PIN r0_rd_out[51]
    DIRECTION OUTPUT ;
    USE SIGNAL ;
    SHAPE ABUTMENT ;
    PORT
      LAYER metal3 ;
      RECT 1075.305 0.000 1075.375 0.210 ;
    END
  END r0_rd_out[51]
  PIN r0_rd_out[52]
    DIRECTION OUTPUT ;
    USE SIGNAL ;
    SHAPE ABUTMENT ;
    PORT
      LAYER metal3 ;
      RECT 1078.805 0.000 1078.875 0.210 ;
    END
  END r0_rd_out[52]
  PIN r0_rd_out[53]
    DIRECTION OUTPUT ;
    USE SIGNAL ;
    SHAPE ABUTMENT ;
    PORT
      LAYER metal3 ;
      RECT 1082.305 0.000 1082.375 0.210 ;
    END
  END r0_rd_out[53]
  PIN r0_rd_out[54]
    DIRECTION OUTPUT ;
    USE SIGNAL ;
    SHAPE ABUTMENT ;
    PORT
      LAYER metal3 ;
      RECT 1085.805 0.000 1085.875 0.210 ;
    END
  END r0_rd_out[54]
  PIN r0_rd_out[55]
    DIRECTION OUTPUT ;
    USE SIGNAL ;
    SHAPE ABUTMENT ;
    PORT
      LAYER metal3 ;
      RECT 1089.305 0.000 1089.375 0.210 ;
    END
  END r0_rd_out[55]
  PIN r0_rd_out[56]
    DIRECTION OUTPUT ;
    USE SIGNAL ;
    SHAPE ABUTMENT ;
    PORT
      LAYER metal3 ;
      RECT 1092.805 0.000 1092.875 0.210 ;
    END
  END r0_rd_out[56]
  PIN r0_rd_out[57]
    DIRECTION OUTPUT ;
    USE SIGNAL ;
    SHAPE ABUTMENT ;
    PORT
      LAYER metal3 ;
      RECT 1096.305 0.000 1096.375 0.210 ;
    END
  END r0_rd_out[57]
  PIN r0_rd_out[58]
    DIRECTION OUTPUT ;
    USE SIGNAL ;
    SHAPE ABUTMENT ;
    PORT
      LAYER metal3 ;
      RECT 1099.805 0.000 1099.875 0.210 ;
    END
  END r0_rd_out[58]
  PIN r0_rd_out[59]
    DIRECTION OUTPUT ;
    USE SIGNAL ;
    SHAPE ABUTMENT ;
    PORT
      LAYER metal3 ;
      RECT 1103.305 0.000 1103.375 0.210 ;
    END
  END r0_rd_out[59]
  PIN r0_rd_out[60]
    DIRECTION OUTPUT ;
    USE SIGNAL ;
    SHAPE ABUTMENT ;
    PORT
      LAYER metal3 ;
      RECT 1106.805 0.000 1106.875 0.210 ;
    END
  END r0_rd_out[60]
  PIN r0_rd_out[61]
    DIRECTION OUTPUT ;
    USE SIGNAL ;
    SHAPE ABUTMENT ;
    PORT
      LAYER metal3 ;
      RECT 1110.305 0.000 1110.375 0.210 ;
    END
  END r0_rd_out[61]
  PIN r0_rd_out[62]
    DIRECTION OUTPUT ;
    USE SIGNAL ;
    SHAPE ABUTMENT ;
    PORT
      LAYER metal3 ;
      RECT 1113.805 0.000 1113.875 0.210 ;
    END
  END r0_rd_out[62]
  PIN r0_rd_out[63]
    DIRECTION OUTPUT ;
    USE SIGNAL ;
    SHAPE ABUTMENT ;
    PORT
      LAYER metal3 ;
      RECT 1117.305 0.000 1117.375 0.210 ;
    END
  END r0_rd_out[63]
  PIN r0_rd_out[64]
    DIRECTION OUTPUT ;
    USE SIGNAL ;
    SHAPE ABUTMENT ;
    PORT
      LAYER metal3 ;
      RECT 1120.805 0.000 1120.875 0.210 ;
    END
  END r0_rd_out[64]
  PIN r0_rd_out[65]
    DIRECTION OUTPUT ;
    USE SIGNAL ;
    SHAPE ABUTMENT ;
    PORT
      LAYER metal3 ;
      RECT 1124.305 0.000 1124.375 0.210 ;
    END
  END r0_rd_out[65]
  PIN r0_rd_out[66]
    DIRECTION OUTPUT ;
    USE SIGNAL ;
    SHAPE ABUTMENT ;
    PORT
      LAYER metal3 ;
      RECT 1127.805 0.000 1127.875 0.210 ;
    END
  END r0_rd_out[66]
  PIN r0_rd_out[67]
    DIRECTION OUTPUT ;
    USE SIGNAL ;
    SHAPE ABUTMENT ;
    PORT
      LAYER metal3 ;
      RECT 1131.305 0.000 1131.375 0.210 ;
    END
  END r0_rd_out[67]
  PIN r0_rd_out[68]
    DIRECTION OUTPUT ;
    USE SIGNAL ;
    SHAPE ABUTMENT ;
    PORT
      LAYER metal3 ;
      RECT 1134.805 0.000 1134.875 0.210 ;
    END
  END r0_rd_out[68]
  PIN r0_rd_out[69]
    DIRECTION OUTPUT ;
    USE SIGNAL ;
    SHAPE ABUTMENT ;
    PORT
      LAYER metal3 ;
      RECT 1138.305 0.000 1138.375 0.210 ;
    END
  END r0_rd_out[69]
  PIN r0_rd_out[70]
    DIRECTION OUTPUT ;
    USE SIGNAL ;
    SHAPE ABUTMENT ;
    PORT
      LAYER metal3 ;
      RECT 1141.805 0.000 1141.875 0.210 ;
    END
  END r0_rd_out[70]
  PIN r0_rd_out[71]
    DIRECTION OUTPUT ;
    USE SIGNAL ;
    SHAPE ABUTMENT ;
    PORT
      LAYER metal3 ;
      RECT 1145.305 0.000 1145.375 0.210 ;
    END
  END r0_rd_out[71]
  PIN r0_rd_out[72]
    DIRECTION OUTPUT ;
    USE SIGNAL ;
    SHAPE ABUTMENT ;
    PORT
      LAYER metal3 ;
      RECT 1148.805 0.000 1148.875 0.210 ;
    END
  END r0_rd_out[72]
  PIN r0_rd_out[73]
    DIRECTION OUTPUT ;
    USE SIGNAL ;
    SHAPE ABUTMENT ;
    PORT
      LAYER metal3 ;
      RECT 1152.305 0.000 1152.375 0.210 ;
    END
  END r0_rd_out[73]
  PIN r0_rd_out[74]
    DIRECTION OUTPUT ;
    USE SIGNAL ;
    SHAPE ABUTMENT ;
    PORT
      LAYER metal3 ;
      RECT 1155.805 0.000 1155.875 0.210 ;
    END
  END r0_rd_out[74]
  PIN r0_rd_out[75]
    DIRECTION OUTPUT ;
    USE SIGNAL ;
    SHAPE ABUTMENT ;
    PORT
      LAYER metal3 ;
      RECT 1159.305 0.000 1159.375 0.210 ;
    END
  END r0_rd_out[75]
  PIN r0_rd_out[76]
    DIRECTION OUTPUT ;
    USE SIGNAL ;
    SHAPE ABUTMENT ;
    PORT
      LAYER metal3 ;
      RECT 1162.805 0.000 1162.875 0.210 ;
    END
  END r0_rd_out[76]
  PIN r0_rd_out[77]
    DIRECTION OUTPUT ;
    USE SIGNAL ;
    SHAPE ABUTMENT ;
    PORT
      LAYER metal3 ;
      RECT 1166.305 0.000 1166.375 0.210 ;
    END
  END r0_rd_out[77]
  PIN r0_rd_out[78]
    DIRECTION OUTPUT ;
    USE SIGNAL ;
    SHAPE ABUTMENT ;
    PORT
      LAYER metal3 ;
      RECT 1169.805 0.000 1169.875 0.210 ;
    END
  END r0_rd_out[78]
  PIN r0_rd_out[79]
    DIRECTION OUTPUT ;
    USE SIGNAL ;
    SHAPE ABUTMENT ;
    PORT
      LAYER metal3 ;
      RECT 1173.305 0.000 1173.375 0.210 ;
    END
  END r0_rd_out[79]
  PIN r0_rd_out[80]
    DIRECTION OUTPUT ;
    USE SIGNAL ;
    SHAPE ABUTMENT ;
    PORT
      LAYER metal3 ;
      RECT 1176.805 0.000 1176.875 0.210 ;
    END
  END r0_rd_out[80]
  PIN r0_rd_out[81]
    DIRECTION OUTPUT ;
    USE SIGNAL ;
    SHAPE ABUTMENT ;
    PORT
      LAYER metal3 ;
      RECT 1180.305 0.000 1180.375 0.210 ;
    END
  END r0_rd_out[81]
  PIN r0_rd_out[82]
    DIRECTION OUTPUT ;
    USE SIGNAL ;
    SHAPE ABUTMENT ;
    PORT
      LAYER metal3 ;
      RECT 1183.805 0.000 1183.875 0.210 ;
    END
  END r0_rd_out[82]
  PIN r0_rd_out[83]
    DIRECTION OUTPUT ;
    USE SIGNAL ;
    SHAPE ABUTMENT ;
    PORT
      LAYER metal3 ;
      RECT 1187.305 0.000 1187.375 0.210 ;
    END
  END r0_rd_out[83]
  PIN r0_rd_out[84]
    DIRECTION OUTPUT ;
    USE SIGNAL ;
    SHAPE ABUTMENT ;
    PORT
      LAYER metal3 ;
      RECT 1190.805 0.000 1190.875 0.210 ;
    END
  END r0_rd_out[84]
  PIN r0_rd_out[85]
    DIRECTION OUTPUT ;
    USE SIGNAL ;
    SHAPE ABUTMENT ;
    PORT
      LAYER metal3 ;
      RECT 1194.305 0.000 1194.375 0.210 ;
    END
  END r0_rd_out[85]
  PIN r0_rd_out[86]
    DIRECTION OUTPUT ;
    USE SIGNAL ;
    SHAPE ABUTMENT ;
    PORT
      LAYER metal3 ;
      RECT 1197.805 0.000 1197.875 0.210 ;
    END
  END r0_rd_out[86]
  PIN r0_rd_out[87]
    DIRECTION OUTPUT ;
    USE SIGNAL ;
    SHAPE ABUTMENT ;
    PORT
      LAYER metal3 ;
      RECT 1201.305 0.000 1201.375 0.210 ;
    END
  END r0_rd_out[87]
  PIN r0_rd_out[88]
    DIRECTION OUTPUT ;
    USE SIGNAL ;
    SHAPE ABUTMENT ;
    PORT
      LAYER metal3 ;
      RECT 1204.805 0.000 1204.875 0.210 ;
    END
  END r0_rd_out[88]
  PIN r0_rd_out[89]
    DIRECTION OUTPUT ;
    USE SIGNAL ;
    SHAPE ABUTMENT ;
    PORT
      LAYER metal3 ;
      RECT 1208.305 0.000 1208.375 0.210 ;
    END
  END r0_rd_out[89]
  PIN r0_rd_out[90]
    DIRECTION OUTPUT ;
    USE SIGNAL ;
    SHAPE ABUTMENT ;
    PORT
      LAYER metal3 ;
      RECT 1211.805 0.000 1211.875 0.210 ;
    END
  END r0_rd_out[90]
  PIN r0_rd_out[91]
    DIRECTION OUTPUT ;
    USE SIGNAL ;
    SHAPE ABUTMENT ;
    PORT
      LAYER metal3 ;
      RECT 1215.305 0.000 1215.375 0.210 ;
    END
  END r0_rd_out[91]
  PIN r0_rd_out[92]
    DIRECTION OUTPUT ;
    USE SIGNAL ;
    SHAPE ABUTMENT ;
    PORT
      LAYER metal3 ;
      RECT 1218.805 0.000 1218.875 0.210 ;
    END
  END r0_rd_out[92]
  PIN r0_rd_out[93]
    DIRECTION OUTPUT ;
    USE SIGNAL ;
    SHAPE ABUTMENT ;
    PORT
      LAYER metal3 ;
      RECT 1222.305 0.000 1222.375 0.210 ;
    END
  END r0_rd_out[93]
  PIN r0_rd_out[94]
    DIRECTION OUTPUT ;
    USE SIGNAL ;
    SHAPE ABUTMENT ;
    PORT
      LAYER metal3 ;
      RECT 1225.805 0.000 1225.875 0.210 ;
    END
  END r0_rd_out[94]
  PIN r0_rd_out[95]
    DIRECTION OUTPUT ;
    USE SIGNAL ;
    SHAPE ABUTMENT ;
    PORT
      LAYER metal3 ;
      RECT 1229.305 0.000 1229.375 0.210 ;
    END
  END r0_rd_out[95]
  PIN r0_rd_out[96]
    DIRECTION OUTPUT ;
    USE SIGNAL ;
    SHAPE ABUTMENT ;
    PORT
      LAYER metal3 ;
      RECT 1232.805 0.000 1232.875 0.210 ;
    END
  END r0_rd_out[96]
  PIN r0_rd_out[97]
    DIRECTION OUTPUT ;
    USE SIGNAL ;
    SHAPE ABUTMENT ;
    PORT
      LAYER metal3 ;
      RECT 1236.305 0.000 1236.375 0.210 ;
    END
  END r0_rd_out[97]
  PIN r0_rd_out[98]
    DIRECTION OUTPUT ;
    USE SIGNAL ;
    SHAPE ABUTMENT ;
    PORT
      LAYER metal3 ;
      RECT 1239.805 0.000 1239.875 0.210 ;
    END
  END r0_rd_out[98]
  PIN r0_rd_out[99]
    DIRECTION OUTPUT ;
    USE SIGNAL ;
    SHAPE ABUTMENT ;
    PORT
      LAYER metal3 ;
      RECT 1243.305 0.000 1243.375 0.210 ;
    END
  END r0_rd_out[99]
  PIN r0_rd_out[100]
    DIRECTION OUTPUT ;
    USE SIGNAL ;
    SHAPE ABUTMENT ;
    PORT
      LAYER metal3 ;
      RECT 1246.805 0.000 1246.875 0.210 ;
    END
  END r0_rd_out[100]
  PIN r0_rd_out[101]
    DIRECTION OUTPUT ;
    USE SIGNAL ;
    SHAPE ABUTMENT ;
    PORT
      LAYER metal3 ;
      RECT 1250.305 0.000 1250.375 0.210 ;
    END
  END r0_rd_out[101]
  PIN r0_rd_out[102]
    DIRECTION OUTPUT ;
    USE SIGNAL ;
    SHAPE ABUTMENT ;
    PORT
      LAYER metal3 ;
      RECT 1253.805 0.000 1253.875 0.210 ;
    END
  END r0_rd_out[102]
  PIN r0_rd_out[103]
    DIRECTION OUTPUT ;
    USE SIGNAL ;
    SHAPE ABUTMENT ;
    PORT
      LAYER metal3 ;
      RECT 1257.305 0.000 1257.375 0.210 ;
    END
  END r0_rd_out[103]
  PIN r0_rd_out[104]
    DIRECTION OUTPUT ;
    USE SIGNAL ;
    SHAPE ABUTMENT ;
    PORT
      LAYER metal3 ;
      RECT 1260.805 0.000 1260.875 0.210 ;
    END
  END r0_rd_out[104]
  PIN r0_rd_out[105]
    DIRECTION OUTPUT ;
    USE SIGNAL ;
    SHAPE ABUTMENT ;
    PORT
      LAYER metal3 ;
      RECT 1264.305 0.000 1264.375 0.210 ;
    END
  END r0_rd_out[105]
  PIN r0_rd_out[106]
    DIRECTION OUTPUT ;
    USE SIGNAL ;
    SHAPE ABUTMENT ;
    PORT
      LAYER metal3 ;
      RECT 1267.805 0.000 1267.875 0.210 ;
    END
  END r0_rd_out[106]
  PIN r0_rd_out[107]
    DIRECTION OUTPUT ;
    USE SIGNAL ;
    SHAPE ABUTMENT ;
    PORT
      LAYER metal3 ;
      RECT 1271.305 0.000 1271.375 0.210 ;
    END
  END r0_rd_out[107]
  PIN r0_rd_out[108]
    DIRECTION OUTPUT ;
    USE SIGNAL ;
    SHAPE ABUTMENT ;
    PORT
      LAYER metal3 ;
      RECT 1274.805 0.000 1274.875 0.210 ;
    END
  END r0_rd_out[108]
  PIN r0_rd_out[109]
    DIRECTION OUTPUT ;
    USE SIGNAL ;
    SHAPE ABUTMENT ;
    PORT
      LAYER metal3 ;
      RECT 1278.305 0.000 1278.375 0.210 ;
    END
  END r0_rd_out[109]
  PIN r0_rd_out[110]
    DIRECTION OUTPUT ;
    USE SIGNAL ;
    SHAPE ABUTMENT ;
    PORT
      LAYER metal3 ;
      RECT 1281.805 0.000 1281.875 0.210 ;
    END
  END r0_rd_out[110]
  PIN r0_rd_out[111]
    DIRECTION OUTPUT ;
    USE SIGNAL ;
    SHAPE ABUTMENT ;
    PORT
      LAYER metal3 ;
      RECT 1285.305 0.000 1285.375 0.210 ;
    END
  END r0_rd_out[111]
  PIN r0_rd_out[112]
    DIRECTION OUTPUT ;
    USE SIGNAL ;
    SHAPE ABUTMENT ;
    PORT
      LAYER metal3 ;
      RECT 1288.805 0.000 1288.875 0.210 ;
    END
  END r0_rd_out[112]
  PIN r0_rd_out[113]
    DIRECTION OUTPUT ;
    USE SIGNAL ;
    SHAPE ABUTMENT ;
    PORT
      LAYER metal3 ;
      RECT 1292.305 0.000 1292.375 0.210 ;
    END
  END r0_rd_out[113]
  PIN r0_rd_out[114]
    DIRECTION OUTPUT ;
    USE SIGNAL ;
    SHAPE ABUTMENT ;
    PORT
      LAYER metal3 ;
      RECT 1295.805 0.000 1295.875 0.210 ;
    END
  END r0_rd_out[114]
  PIN r0_rd_out[115]
    DIRECTION OUTPUT ;
    USE SIGNAL ;
    SHAPE ABUTMENT ;
    PORT
      LAYER metal3 ;
      RECT 1299.305 0.000 1299.375 0.210 ;
    END
  END r0_rd_out[115]
  PIN r0_rd_out[116]
    DIRECTION OUTPUT ;
    USE SIGNAL ;
    SHAPE ABUTMENT ;
    PORT
      LAYER metal3 ;
      RECT 1302.805 0.000 1302.875 0.210 ;
    END
  END r0_rd_out[116]
  PIN r0_rd_out[117]
    DIRECTION OUTPUT ;
    USE SIGNAL ;
    SHAPE ABUTMENT ;
    PORT
      LAYER metal3 ;
      RECT 1306.305 0.000 1306.375 0.210 ;
    END
  END r0_rd_out[117]
  PIN r0_rd_out[118]
    DIRECTION OUTPUT ;
    USE SIGNAL ;
    SHAPE ABUTMENT ;
    PORT
      LAYER metal3 ;
      RECT 1309.805 0.000 1309.875 0.210 ;
    END
  END r0_rd_out[118]
  PIN r0_rd_out[119]
    DIRECTION OUTPUT ;
    USE SIGNAL ;
    SHAPE ABUTMENT ;
    PORT
      LAYER metal3 ;
      RECT 1313.305 0.000 1313.375 0.210 ;
    END
  END r0_rd_out[119]
  PIN r0_rd_out[120]
    DIRECTION OUTPUT ;
    USE SIGNAL ;
    SHAPE ABUTMENT ;
    PORT
      LAYER metal3 ;
      RECT 1316.805 0.000 1316.875 0.210 ;
    END
  END r0_rd_out[120]
  PIN r0_rd_out[121]
    DIRECTION OUTPUT ;
    USE SIGNAL ;
    SHAPE ABUTMENT ;
    PORT
      LAYER metal3 ;
      RECT 1320.305 0.000 1320.375 0.210 ;
    END
  END r0_rd_out[121]
  PIN r0_rd_out[122]
    DIRECTION OUTPUT ;
    USE SIGNAL ;
    SHAPE ABUTMENT ;
    PORT
      LAYER metal3 ;
      RECT 1323.805 0.000 1323.875 0.210 ;
    END
  END r0_rd_out[122]
  PIN r0_rd_out[123]
    DIRECTION OUTPUT ;
    USE SIGNAL ;
    SHAPE ABUTMENT ;
    PORT
      LAYER metal3 ;
      RECT 1327.305 0.000 1327.375 0.210 ;
    END
  END r0_rd_out[123]
  PIN r0_rd_out[124]
    DIRECTION OUTPUT ;
    USE SIGNAL ;
    SHAPE ABUTMENT ;
    PORT
      LAYER metal3 ;
      RECT 1330.805 0.000 1330.875 0.210 ;
    END
  END r0_rd_out[124]
  PIN r0_rd_out[125]
    DIRECTION OUTPUT ;
    USE SIGNAL ;
    SHAPE ABUTMENT ;
    PORT
      LAYER metal3 ;
      RECT 1334.305 0.000 1334.375 0.210 ;
    END
  END r0_rd_out[125]
  PIN r0_rd_out[126]
    DIRECTION OUTPUT ;
    USE SIGNAL ;
    SHAPE ABUTMENT ;
    PORT
      LAYER metal3 ;
      RECT 1337.805 0.000 1337.875 0.210 ;
    END
  END r0_rd_out[126]
  PIN r0_rd_out[127]
    DIRECTION OUTPUT ;
    USE SIGNAL ;
    SHAPE ABUTMENT ;
    PORT
      LAYER metal3 ;
      RECT 1341.305 0.000 1341.375 0.210 ;
    END
  END r0_rd_out[127]
  PIN r0_rd_out[128]
    DIRECTION OUTPUT ;
    USE SIGNAL ;
    SHAPE ABUTMENT ;
    PORT
      LAYER metal3 ;
      RECT 1344.805 0.000 1344.875 0.210 ;
    END
  END r0_rd_out[128]
  PIN r0_rd_out[129]
    DIRECTION OUTPUT ;
    USE SIGNAL ;
    SHAPE ABUTMENT ;
    PORT
      LAYER metal3 ;
      RECT 1348.305 0.000 1348.375 0.210 ;
    END
  END r0_rd_out[129]
  PIN r0_rd_out[130]
    DIRECTION OUTPUT ;
    USE SIGNAL ;
    SHAPE ABUTMENT ;
    PORT
      LAYER metal3 ;
      RECT 1351.805 0.000 1351.875 0.210 ;
    END
  END r0_rd_out[130]
  PIN r0_rd_out[131]
    DIRECTION OUTPUT ;
    USE SIGNAL ;
    SHAPE ABUTMENT ;
    PORT
      LAYER metal3 ;
      RECT 1355.305 0.000 1355.375 0.210 ;
    END
  END r0_rd_out[131]
  PIN r0_rd_out[132]
    DIRECTION OUTPUT ;
    USE SIGNAL ;
    SHAPE ABUTMENT ;
    PORT
      LAYER metal3 ;
      RECT 1358.805 0.000 1358.875 0.210 ;
    END
  END r0_rd_out[132]
  PIN r0_rd_out[133]
    DIRECTION OUTPUT ;
    USE SIGNAL ;
    SHAPE ABUTMENT ;
    PORT
      LAYER metal3 ;
      RECT 1362.305 0.000 1362.375 0.210 ;
    END
  END r0_rd_out[133]
  PIN r0_rd_out[134]
    DIRECTION OUTPUT ;
    USE SIGNAL ;
    SHAPE ABUTMENT ;
    PORT
      LAYER metal3 ;
      RECT 1365.805 0.000 1365.875 0.210 ;
    END
  END r0_rd_out[134]
  PIN r0_rd_out[135]
    DIRECTION OUTPUT ;
    USE SIGNAL ;
    SHAPE ABUTMENT ;
    PORT
      LAYER metal3 ;
      RECT 1369.305 0.000 1369.375 0.210 ;
    END
  END r0_rd_out[135]
  PIN r0_rd_out[136]
    DIRECTION OUTPUT ;
    USE SIGNAL ;
    SHAPE ABUTMENT ;
    PORT
      LAYER metal3 ;
      RECT 1372.805 0.000 1372.875 0.210 ;
    END
  END r0_rd_out[136]
  PIN r0_rd_out[137]
    DIRECTION OUTPUT ;
    USE SIGNAL ;
    SHAPE ABUTMENT ;
    PORT
      LAYER metal3 ;
      RECT 1376.305 0.000 1376.375 0.210 ;
    END
  END r0_rd_out[137]
  PIN r0_rd_out[138]
    DIRECTION OUTPUT ;
    USE SIGNAL ;
    SHAPE ABUTMENT ;
    PORT
      LAYER metal3 ;
      RECT 1379.805 0.000 1379.875 0.210 ;
    END
  END r0_rd_out[138]
  PIN r0_rd_out[139]
    DIRECTION OUTPUT ;
    USE SIGNAL ;
    SHAPE ABUTMENT ;
    PORT
      LAYER metal3 ;
      RECT 1383.305 0.000 1383.375 0.210 ;
    END
  END r0_rd_out[139]
  PIN r0_rd_out[140]
    DIRECTION OUTPUT ;
    USE SIGNAL ;
    SHAPE ABUTMENT ;
    PORT
      LAYER metal3 ;
      RECT 1386.805 0.000 1386.875 0.210 ;
    END
  END r0_rd_out[140]
  PIN r0_rd_out[141]
    DIRECTION OUTPUT ;
    USE SIGNAL ;
    SHAPE ABUTMENT ;
    PORT
      LAYER metal3 ;
      RECT 1390.305 0.000 1390.375 0.210 ;
    END
  END r0_rd_out[141]
  PIN r0_rd_out[142]
    DIRECTION OUTPUT ;
    USE SIGNAL ;
    SHAPE ABUTMENT ;
    PORT
      LAYER metal3 ;
      RECT 1393.805 0.000 1393.875 0.210 ;
    END
  END r0_rd_out[142]
  PIN r0_rd_out[143]
    DIRECTION OUTPUT ;
    USE SIGNAL ;
    SHAPE ABUTMENT ;
    PORT
      LAYER metal3 ;
      RECT 1397.305 0.000 1397.375 0.210 ;
    END
  END r0_rd_out[143]
  PIN r0_rd_out[144]
    DIRECTION OUTPUT ;
    USE SIGNAL ;
    SHAPE ABUTMENT ;
    PORT
      LAYER metal3 ;
      RECT 1400.805 0.000 1400.875 0.210 ;
    END
  END r0_rd_out[144]
  PIN r0_rd_out[145]
    DIRECTION OUTPUT ;
    USE SIGNAL ;
    SHAPE ABUTMENT ;
    PORT
      LAYER metal3 ;
      RECT 1404.305 0.000 1404.375 0.210 ;
    END
  END r0_rd_out[145]
  PIN r0_rd_out[146]
    DIRECTION OUTPUT ;
    USE SIGNAL ;
    SHAPE ABUTMENT ;
    PORT
      LAYER metal3 ;
      RECT 1407.805 0.000 1407.875 0.210 ;
    END
  END r0_rd_out[146]
  PIN r0_rd_out[147]
    DIRECTION OUTPUT ;
    USE SIGNAL ;
    SHAPE ABUTMENT ;
    PORT
      LAYER metal3 ;
      RECT 1411.305 0.000 1411.375 0.210 ;
    END
  END r0_rd_out[147]
  PIN r0_rd_out[148]
    DIRECTION OUTPUT ;
    USE SIGNAL ;
    SHAPE ABUTMENT ;
    PORT
      LAYER metal3 ;
      RECT 1414.805 0.000 1414.875 0.210 ;
    END
  END r0_rd_out[148]
  PIN r0_rd_out[149]
    DIRECTION OUTPUT ;
    USE SIGNAL ;
    SHAPE ABUTMENT ;
    PORT
      LAYER metal3 ;
      RECT 1418.305 0.000 1418.375 0.210 ;
    END
  END r0_rd_out[149]
  PIN r0_rd_out[150]
    DIRECTION OUTPUT ;
    USE SIGNAL ;
    SHAPE ABUTMENT ;
    PORT
      LAYER metal3 ;
      RECT 1421.805 0.000 1421.875 0.210 ;
    END
  END r0_rd_out[150]
  PIN r0_rd_out[151]
    DIRECTION OUTPUT ;
    USE SIGNAL ;
    SHAPE ABUTMENT ;
    PORT
      LAYER metal3 ;
      RECT 1425.305 0.000 1425.375 0.210 ;
    END
  END r0_rd_out[151]
  PIN r0_rd_out[152]
    DIRECTION OUTPUT ;
    USE SIGNAL ;
    SHAPE ABUTMENT ;
    PORT
      LAYER metal3 ;
      RECT 1428.805 0.000 1428.875 0.210 ;
    END
  END r0_rd_out[152]
  PIN r0_rd_out[153]
    DIRECTION OUTPUT ;
    USE SIGNAL ;
    SHAPE ABUTMENT ;
    PORT
      LAYER metal3 ;
      RECT 1432.305 0.000 1432.375 0.210 ;
    END
  END r0_rd_out[153]
  PIN r0_rd_out[154]
    DIRECTION OUTPUT ;
    USE SIGNAL ;
    SHAPE ABUTMENT ;
    PORT
      LAYER metal3 ;
      RECT 1435.805 0.000 1435.875 0.210 ;
    END
  END r0_rd_out[154]
  PIN r0_rd_out[155]
    DIRECTION OUTPUT ;
    USE SIGNAL ;
    SHAPE ABUTMENT ;
    PORT
      LAYER metal3 ;
      RECT 1439.305 0.000 1439.375 0.210 ;
    END
  END r0_rd_out[155]
  PIN r0_rd_out[156]
    DIRECTION OUTPUT ;
    USE SIGNAL ;
    SHAPE ABUTMENT ;
    PORT
      LAYER metal3 ;
      RECT 1442.805 0.000 1442.875 0.210 ;
    END
  END r0_rd_out[156]
  PIN r0_rd_out[157]
    DIRECTION OUTPUT ;
    USE SIGNAL ;
    SHAPE ABUTMENT ;
    PORT
      LAYER metal3 ;
      RECT 1446.305 0.000 1446.375 0.210 ;
    END
  END r0_rd_out[157]
  PIN r0_rd_out[158]
    DIRECTION OUTPUT ;
    USE SIGNAL ;
    SHAPE ABUTMENT ;
    PORT
      LAYER metal3 ;
      RECT 1449.805 0.000 1449.875 0.210 ;
    END
  END r0_rd_out[158]
  PIN r0_rd_out[159]
    DIRECTION OUTPUT ;
    USE SIGNAL ;
    SHAPE ABUTMENT ;
    PORT
      LAYER metal3 ;
      RECT 1453.305 0.000 1453.375 0.210 ;
    END
  END r0_rd_out[159]
  PIN r0_rd_out[160]
    DIRECTION OUTPUT ;
    USE SIGNAL ;
    SHAPE ABUTMENT ;
    PORT
      LAYER metal3 ;
      RECT 1456.805 0.000 1456.875 0.210 ;
    END
  END r0_rd_out[160]
  PIN r0_rd_out[161]
    DIRECTION OUTPUT ;
    USE SIGNAL ;
    SHAPE ABUTMENT ;
    PORT
      LAYER metal3 ;
      RECT 1460.305 0.000 1460.375 0.210 ;
    END
  END r0_rd_out[161]
  PIN r0_rd_out[162]
    DIRECTION OUTPUT ;
    USE SIGNAL ;
    SHAPE ABUTMENT ;
    PORT
      LAYER metal3 ;
      RECT 1463.805 0.000 1463.875 0.210 ;
    END
  END r0_rd_out[162]
  PIN r0_rd_out[163]
    DIRECTION OUTPUT ;
    USE SIGNAL ;
    SHAPE ABUTMENT ;
    PORT
      LAYER metal3 ;
      RECT 1467.305 0.000 1467.375 0.210 ;
    END
  END r0_rd_out[163]
  PIN r0_rd_out[164]
    DIRECTION OUTPUT ;
    USE SIGNAL ;
    SHAPE ABUTMENT ;
    PORT
      LAYER metal3 ;
      RECT 1470.805 0.000 1470.875 0.210 ;
    END
  END r0_rd_out[164]
  PIN r0_rd_out[165]
    DIRECTION OUTPUT ;
    USE SIGNAL ;
    SHAPE ABUTMENT ;
    PORT
      LAYER metal3 ;
      RECT 1474.305 0.000 1474.375 0.210 ;
    END
  END r0_rd_out[165]
  PIN r0_rd_out[166]
    DIRECTION OUTPUT ;
    USE SIGNAL ;
    SHAPE ABUTMENT ;
    PORT
      LAYER metal3 ;
      RECT 1477.805 0.000 1477.875 0.210 ;
    END
  END r0_rd_out[166]
  PIN r0_rd_out[167]
    DIRECTION OUTPUT ;
    USE SIGNAL ;
    SHAPE ABUTMENT ;
    PORT
      LAYER metal3 ;
      RECT 1481.305 0.000 1481.375 0.210 ;
    END
  END r0_rd_out[167]
  PIN r0_rd_out[168]
    DIRECTION OUTPUT ;
    USE SIGNAL ;
    SHAPE ABUTMENT ;
    PORT
      LAYER metal3 ;
      RECT 1484.805 0.000 1484.875 0.210 ;
    END
  END r0_rd_out[168]
  PIN r0_rd_out[169]
    DIRECTION OUTPUT ;
    USE SIGNAL ;
    SHAPE ABUTMENT ;
    PORT
      LAYER metal3 ;
      RECT 1488.305 0.000 1488.375 0.210 ;
    END
  END r0_rd_out[169]
  PIN r0_rd_out[170]
    DIRECTION OUTPUT ;
    USE SIGNAL ;
    SHAPE ABUTMENT ;
    PORT
      LAYER metal3 ;
      RECT 1491.805 0.000 1491.875 0.210 ;
    END
  END r0_rd_out[170]
  PIN r0_rd_out[171]
    DIRECTION OUTPUT ;
    USE SIGNAL ;
    SHAPE ABUTMENT ;
    PORT
      LAYER metal3 ;
      RECT 1495.305 0.000 1495.375 0.210 ;
    END
  END r0_rd_out[171]
  PIN r0_rd_out[172]
    DIRECTION OUTPUT ;
    USE SIGNAL ;
    SHAPE ABUTMENT ;
    PORT
      LAYER metal3 ;
      RECT 1498.805 0.000 1498.875 0.210 ;
    END
  END r0_rd_out[172]
  PIN r0_rd_out[173]
    DIRECTION OUTPUT ;
    USE SIGNAL ;
    SHAPE ABUTMENT ;
    PORT
      LAYER metal3 ;
      RECT 1502.305 0.000 1502.375 0.210 ;
    END
  END r0_rd_out[173]
  PIN r0_rd_out[174]
    DIRECTION OUTPUT ;
    USE SIGNAL ;
    SHAPE ABUTMENT ;
    PORT
      LAYER metal3 ;
      RECT 1505.805 0.000 1505.875 0.210 ;
    END
  END r0_rd_out[174]
  PIN r0_rd_out[175]
    DIRECTION OUTPUT ;
    USE SIGNAL ;
    SHAPE ABUTMENT ;
    PORT
      LAYER metal3 ;
      RECT 1509.305 0.000 1509.375 0.210 ;
    END
  END r0_rd_out[175]
  PIN r0_rd_out[176]
    DIRECTION OUTPUT ;
    USE SIGNAL ;
    SHAPE ABUTMENT ;
    PORT
      LAYER metal3 ;
      RECT 1512.805 0.000 1512.875 0.210 ;
    END
  END r0_rd_out[176]
  PIN r0_rd_out[177]
    DIRECTION OUTPUT ;
    USE SIGNAL ;
    SHAPE ABUTMENT ;
    PORT
      LAYER metal3 ;
      RECT 1516.305 0.000 1516.375 0.210 ;
    END
  END r0_rd_out[177]
  PIN r0_rd_out[178]
    DIRECTION OUTPUT ;
    USE SIGNAL ;
    SHAPE ABUTMENT ;
    PORT
      LAYER metal3 ;
      RECT 1519.805 0.000 1519.875 0.210 ;
    END
  END r0_rd_out[178]
  PIN r0_rd_out[179]
    DIRECTION OUTPUT ;
    USE SIGNAL ;
    SHAPE ABUTMENT ;
    PORT
      LAYER metal3 ;
      RECT 1523.305 0.000 1523.375 0.210 ;
    END
  END r0_rd_out[179]
  PIN r0_rd_out[180]
    DIRECTION OUTPUT ;
    USE SIGNAL ;
    SHAPE ABUTMENT ;
    PORT
      LAYER metal3 ;
      RECT 1526.805 0.000 1526.875 0.210 ;
    END
  END r0_rd_out[180]
  PIN r0_rd_out[181]
    DIRECTION OUTPUT ;
    USE SIGNAL ;
    SHAPE ABUTMENT ;
    PORT
      LAYER metal3 ;
      RECT 1530.305 0.000 1530.375 0.210 ;
    END
  END r0_rd_out[181]
  PIN r0_rd_out[182]
    DIRECTION OUTPUT ;
    USE SIGNAL ;
    SHAPE ABUTMENT ;
    PORT
      LAYER metal3 ;
      RECT 1533.805 0.000 1533.875 0.210 ;
    END
  END r0_rd_out[182]
  PIN r0_rd_out[183]
    DIRECTION OUTPUT ;
    USE SIGNAL ;
    SHAPE ABUTMENT ;
    PORT
      LAYER metal3 ;
      RECT 1537.305 0.000 1537.375 0.210 ;
    END
  END r0_rd_out[183]
  PIN r0_rd_out[184]
    DIRECTION OUTPUT ;
    USE SIGNAL ;
    SHAPE ABUTMENT ;
    PORT
      LAYER metal3 ;
      RECT 1540.805 0.000 1540.875 0.210 ;
    END
  END r0_rd_out[184]
  PIN r0_rd_out[185]
    DIRECTION OUTPUT ;
    USE SIGNAL ;
    SHAPE ABUTMENT ;
    PORT
      LAYER metal3 ;
      RECT 1544.305 0.000 1544.375 0.210 ;
    END
  END r0_rd_out[185]
  PIN r0_rd_out[186]
    DIRECTION OUTPUT ;
    USE SIGNAL ;
    SHAPE ABUTMENT ;
    PORT
      LAYER metal3 ;
      RECT 1547.805 0.000 1547.875 0.210 ;
    END
  END r0_rd_out[186]
  PIN r0_rd_out[187]
    DIRECTION OUTPUT ;
    USE SIGNAL ;
    SHAPE ABUTMENT ;
    PORT
      LAYER metal3 ;
      RECT 1551.305 0.000 1551.375 0.210 ;
    END
  END r0_rd_out[187]
  PIN r0_rd_out[188]
    DIRECTION OUTPUT ;
    USE SIGNAL ;
    SHAPE ABUTMENT ;
    PORT
      LAYER metal3 ;
      RECT 1554.805 0.000 1554.875 0.210 ;
    END
  END r0_rd_out[188]
  PIN r0_rd_out[189]
    DIRECTION OUTPUT ;
    USE SIGNAL ;
    SHAPE ABUTMENT ;
    PORT
      LAYER metal3 ;
      RECT 1558.305 0.000 1558.375 0.210 ;
    END
  END r0_rd_out[189]
  PIN r0_rd_out[190]
    DIRECTION OUTPUT ;
    USE SIGNAL ;
    SHAPE ABUTMENT ;
    PORT
      LAYER metal3 ;
      RECT 1561.805 0.000 1561.875 0.210 ;
    END
  END r0_rd_out[190]
  PIN r0_rd_out[191]
    DIRECTION OUTPUT ;
    USE SIGNAL ;
    SHAPE ABUTMENT ;
    PORT
      LAYER metal3 ;
      RECT 1565.305 0.000 1565.375 0.210 ;
    END
  END r0_rd_out[191]
  PIN r0_rd_out[192]
    DIRECTION OUTPUT ;
    USE SIGNAL ;
    SHAPE ABUTMENT ;
    PORT
      LAYER metal3 ;
      RECT 1568.805 0.000 1568.875 0.210 ;
    END
  END r0_rd_out[192]
  PIN r0_rd_out[193]
    DIRECTION OUTPUT ;
    USE SIGNAL ;
    SHAPE ABUTMENT ;
    PORT
      LAYER metal3 ;
      RECT 1572.305 0.000 1572.375 0.210 ;
    END
  END r0_rd_out[193]
  PIN r0_rd_out[194]
    DIRECTION OUTPUT ;
    USE SIGNAL ;
    SHAPE ABUTMENT ;
    PORT
      LAYER metal3 ;
      RECT 1575.805 0.000 1575.875 0.210 ;
    END
  END r0_rd_out[194]
  PIN r0_rd_out[195]
    DIRECTION OUTPUT ;
    USE SIGNAL ;
    SHAPE ABUTMENT ;
    PORT
      LAYER metal3 ;
      RECT 1579.305 0.000 1579.375 0.210 ;
    END
  END r0_rd_out[195]
  PIN r0_rd_out[196]
    DIRECTION OUTPUT ;
    USE SIGNAL ;
    SHAPE ABUTMENT ;
    PORT
      LAYER metal3 ;
      RECT 1582.805 0.000 1582.875 0.210 ;
    END
  END r0_rd_out[196]
  PIN r0_rd_out[197]
    DIRECTION OUTPUT ;
    USE SIGNAL ;
    SHAPE ABUTMENT ;
    PORT
      LAYER metal3 ;
      RECT 1586.305 0.000 1586.375 0.210 ;
    END
  END r0_rd_out[197]
  PIN r0_rd_out[198]
    DIRECTION OUTPUT ;
    USE SIGNAL ;
    SHAPE ABUTMENT ;
    PORT
      LAYER metal3 ;
      RECT 1589.805 0.000 1589.875 0.210 ;
    END
  END r0_rd_out[198]
  PIN r0_rd_out[199]
    DIRECTION OUTPUT ;
    USE SIGNAL ;
    SHAPE ABUTMENT ;
    PORT
      LAYER metal3 ;
      RECT 1593.305 0.000 1593.375 0.210 ;
    END
  END r0_rd_out[199]
  PIN r0_rd_out[200]
    DIRECTION OUTPUT ;
    USE SIGNAL ;
    SHAPE ABUTMENT ;
    PORT
      LAYER metal3 ;
      RECT 1596.805 0.000 1596.875 0.210 ;
    END
  END r0_rd_out[200]
  PIN r0_rd_out[201]
    DIRECTION OUTPUT ;
    USE SIGNAL ;
    SHAPE ABUTMENT ;
    PORT
      LAYER metal3 ;
      RECT 1600.305 0.000 1600.375 0.210 ;
    END
  END r0_rd_out[201]
  PIN r0_rd_out[202]
    DIRECTION OUTPUT ;
    USE SIGNAL ;
    SHAPE ABUTMENT ;
    PORT
      LAYER metal3 ;
      RECT 1603.805 0.000 1603.875 0.210 ;
    END
  END r0_rd_out[202]
  PIN r0_rd_out[203]
    DIRECTION OUTPUT ;
    USE SIGNAL ;
    SHAPE ABUTMENT ;
    PORT
      LAYER metal3 ;
      RECT 1607.305 0.000 1607.375 0.210 ;
    END
  END r0_rd_out[203]
  PIN r0_rd_out[204]
    DIRECTION OUTPUT ;
    USE SIGNAL ;
    SHAPE ABUTMENT ;
    PORT
      LAYER metal3 ;
      RECT 1610.805 0.000 1610.875 0.210 ;
    END
  END r0_rd_out[204]
  PIN r0_rd_out[205]
    DIRECTION OUTPUT ;
    USE SIGNAL ;
    SHAPE ABUTMENT ;
    PORT
      LAYER metal3 ;
      RECT 1614.305 0.000 1614.375 0.210 ;
    END
  END r0_rd_out[205]
  PIN r0_rd_out[206]
    DIRECTION OUTPUT ;
    USE SIGNAL ;
    SHAPE ABUTMENT ;
    PORT
      LAYER metal3 ;
      RECT 1617.805 0.000 1617.875 0.210 ;
    END
  END r0_rd_out[206]
  PIN r0_rd_out[207]
    DIRECTION OUTPUT ;
    USE SIGNAL ;
    SHAPE ABUTMENT ;
    PORT
      LAYER metal3 ;
      RECT 1621.305 0.000 1621.375 0.210 ;
    END
  END r0_rd_out[207]
  PIN r0_rd_out[208]
    DIRECTION OUTPUT ;
    USE SIGNAL ;
    SHAPE ABUTMENT ;
    PORT
      LAYER metal3 ;
      RECT 1624.805 0.000 1624.875 0.210 ;
    END
  END r0_rd_out[208]
  PIN r0_rd_out[209]
    DIRECTION OUTPUT ;
    USE SIGNAL ;
    SHAPE ABUTMENT ;
    PORT
      LAYER metal3 ;
      RECT 1628.305 0.000 1628.375 0.210 ;
    END
  END r0_rd_out[209]
  PIN r0_rd_out[210]
    DIRECTION OUTPUT ;
    USE SIGNAL ;
    SHAPE ABUTMENT ;
    PORT
      LAYER metal3 ;
      RECT 1631.805 0.000 1631.875 0.210 ;
    END
  END r0_rd_out[210]
  PIN r0_rd_out[211]
    DIRECTION OUTPUT ;
    USE SIGNAL ;
    SHAPE ABUTMENT ;
    PORT
      LAYER metal3 ;
      RECT 1635.305 0.000 1635.375 0.210 ;
    END
  END r0_rd_out[211]
  PIN r0_rd_out[212]
    DIRECTION OUTPUT ;
    USE SIGNAL ;
    SHAPE ABUTMENT ;
    PORT
      LAYER metal3 ;
      RECT 1638.805 0.000 1638.875 0.210 ;
    END
  END r0_rd_out[212]
  PIN r0_rd_out[213]
    DIRECTION OUTPUT ;
    USE SIGNAL ;
    SHAPE ABUTMENT ;
    PORT
      LAYER metal3 ;
      RECT 1642.305 0.000 1642.375 0.210 ;
    END
  END r0_rd_out[213]
  PIN r0_rd_out[214]
    DIRECTION OUTPUT ;
    USE SIGNAL ;
    SHAPE ABUTMENT ;
    PORT
      LAYER metal3 ;
      RECT 1645.805 0.000 1645.875 0.210 ;
    END
  END r0_rd_out[214]
  PIN r0_rd_out[215]
    DIRECTION OUTPUT ;
    USE SIGNAL ;
    SHAPE ABUTMENT ;
    PORT
      LAYER metal3 ;
      RECT 1649.305 0.000 1649.375 0.210 ;
    END
  END r0_rd_out[215]
  PIN r0_rd_out[216]
    DIRECTION OUTPUT ;
    USE SIGNAL ;
    SHAPE ABUTMENT ;
    PORT
      LAYER metal3 ;
      RECT 1652.805 0.000 1652.875 0.210 ;
    END
  END r0_rd_out[216]
  PIN r0_rd_out[217]
    DIRECTION OUTPUT ;
    USE SIGNAL ;
    SHAPE ABUTMENT ;
    PORT
      LAYER metal3 ;
      RECT 1656.305 0.000 1656.375 0.210 ;
    END
  END r0_rd_out[217]
  PIN r0_rd_out[218]
    DIRECTION OUTPUT ;
    USE SIGNAL ;
    SHAPE ABUTMENT ;
    PORT
      LAYER metal3 ;
      RECT 1659.805 0.000 1659.875 0.210 ;
    END
  END r0_rd_out[218]
  PIN r0_rd_out[219]
    DIRECTION OUTPUT ;
    USE SIGNAL ;
    SHAPE ABUTMENT ;
    PORT
      LAYER metal3 ;
      RECT 1663.305 0.000 1663.375 0.210 ;
    END
  END r0_rd_out[219]
  PIN r0_rd_out[220]
    DIRECTION OUTPUT ;
    USE SIGNAL ;
    SHAPE ABUTMENT ;
    PORT
      LAYER metal3 ;
      RECT 1666.805 0.000 1666.875 0.210 ;
    END
  END r0_rd_out[220]
  PIN r0_rd_out[221]
    DIRECTION OUTPUT ;
    USE SIGNAL ;
    SHAPE ABUTMENT ;
    PORT
      LAYER metal3 ;
      RECT 1670.305 0.000 1670.375 0.210 ;
    END
  END r0_rd_out[221]
  PIN r0_rd_out[222]
    DIRECTION OUTPUT ;
    USE SIGNAL ;
    SHAPE ABUTMENT ;
    PORT
      LAYER metal3 ;
      RECT 1673.805 0.000 1673.875 0.210 ;
    END
  END r0_rd_out[222]
  PIN r0_rd_out[223]
    DIRECTION OUTPUT ;
    USE SIGNAL ;
    SHAPE ABUTMENT ;
    PORT
      LAYER metal3 ;
      RECT 1677.305 0.000 1677.375 0.210 ;
    END
  END r0_rd_out[223]
  PIN r0_rd_out[224]
    DIRECTION OUTPUT ;
    USE SIGNAL ;
    SHAPE ABUTMENT ;
    PORT
      LAYER metal3 ;
      RECT 1680.805 0.000 1680.875 0.210 ;
    END
  END r0_rd_out[224]
  PIN r0_rd_out[225]
    DIRECTION OUTPUT ;
    USE SIGNAL ;
    SHAPE ABUTMENT ;
    PORT
      LAYER metal3 ;
      RECT 1684.305 0.000 1684.375 0.210 ;
    END
  END r0_rd_out[225]
  PIN r0_rd_out[226]
    DIRECTION OUTPUT ;
    USE SIGNAL ;
    SHAPE ABUTMENT ;
    PORT
      LAYER metal3 ;
      RECT 1687.805 0.000 1687.875 0.210 ;
    END
  END r0_rd_out[226]
  PIN r0_rd_out[227]
    DIRECTION OUTPUT ;
    USE SIGNAL ;
    SHAPE ABUTMENT ;
    PORT
      LAYER metal3 ;
      RECT 1691.305 0.000 1691.375 0.210 ;
    END
  END r0_rd_out[227]
  PIN r0_rd_out[228]
    DIRECTION OUTPUT ;
    USE SIGNAL ;
    SHAPE ABUTMENT ;
    PORT
      LAYER metal3 ;
      RECT 1694.805 0.000 1694.875 0.210 ;
    END
  END r0_rd_out[228]
  PIN r0_rd_out[229]
    DIRECTION OUTPUT ;
    USE SIGNAL ;
    SHAPE ABUTMENT ;
    PORT
      LAYER metal3 ;
      RECT 1698.305 0.000 1698.375 0.210 ;
    END
  END r0_rd_out[229]
  PIN r0_rd_out[230]
    DIRECTION OUTPUT ;
    USE SIGNAL ;
    SHAPE ABUTMENT ;
    PORT
      LAYER metal3 ;
      RECT 1701.805 0.000 1701.875 0.210 ;
    END
  END r0_rd_out[230]
  PIN r0_rd_out[231]
    DIRECTION OUTPUT ;
    USE SIGNAL ;
    SHAPE ABUTMENT ;
    PORT
      LAYER metal3 ;
      RECT 1705.305 0.000 1705.375 0.210 ;
    END
  END r0_rd_out[231]
  PIN r0_rd_out[232]
    DIRECTION OUTPUT ;
    USE SIGNAL ;
    SHAPE ABUTMENT ;
    PORT
      LAYER metal3 ;
      RECT 1708.805 0.000 1708.875 0.210 ;
    END
  END r0_rd_out[232]
  PIN r0_rd_out[233]
    DIRECTION OUTPUT ;
    USE SIGNAL ;
    SHAPE ABUTMENT ;
    PORT
      LAYER metal3 ;
      RECT 1712.305 0.000 1712.375 0.210 ;
    END
  END r0_rd_out[233]
  PIN r0_rd_out[234]
    DIRECTION OUTPUT ;
    USE SIGNAL ;
    SHAPE ABUTMENT ;
    PORT
      LAYER metal3 ;
      RECT 1715.805 0.000 1715.875 0.210 ;
    END
  END r0_rd_out[234]
  PIN r0_rd_out[235]
    DIRECTION OUTPUT ;
    USE SIGNAL ;
    SHAPE ABUTMENT ;
    PORT
      LAYER metal3 ;
      RECT 1719.305 0.000 1719.375 0.210 ;
    END
  END r0_rd_out[235]
  PIN r0_rd_out[236]
    DIRECTION OUTPUT ;
    USE SIGNAL ;
    SHAPE ABUTMENT ;
    PORT
      LAYER metal3 ;
      RECT 1722.805 0.000 1722.875 0.210 ;
    END
  END r0_rd_out[236]
  PIN r0_rd_out[237]
    DIRECTION OUTPUT ;
    USE SIGNAL ;
    SHAPE ABUTMENT ;
    PORT
      LAYER metal3 ;
      RECT 1726.305 0.000 1726.375 0.210 ;
    END
  END r0_rd_out[237]
  PIN r0_rd_out[238]
    DIRECTION OUTPUT ;
    USE SIGNAL ;
    SHAPE ABUTMENT ;
    PORT
      LAYER metal3 ;
      RECT 1729.805 0.000 1729.875 0.210 ;
    END
  END r0_rd_out[238]
  PIN r0_rd_out[239]
    DIRECTION OUTPUT ;
    USE SIGNAL ;
    SHAPE ABUTMENT ;
    PORT
      LAYER metal3 ;
      RECT 1733.305 0.000 1733.375 0.210 ;
    END
  END r0_rd_out[239]
  PIN r0_rd_out[240]
    DIRECTION OUTPUT ;
    USE SIGNAL ;
    SHAPE ABUTMENT ;
    PORT
      LAYER metal3 ;
      RECT 1736.805 0.000 1736.875 0.210 ;
    END
  END r0_rd_out[240]
  PIN r0_rd_out[241]
    DIRECTION OUTPUT ;
    USE SIGNAL ;
    SHAPE ABUTMENT ;
    PORT
      LAYER metal3 ;
      RECT 1740.305 0.000 1740.375 0.210 ;
    END
  END r0_rd_out[241]
  PIN r0_rd_out[242]
    DIRECTION OUTPUT ;
    USE SIGNAL ;
    SHAPE ABUTMENT ;
    PORT
      LAYER metal3 ;
      RECT 1743.805 0.000 1743.875 0.210 ;
    END
  END r0_rd_out[242]
  PIN r0_rd_out[243]
    DIRECTION OUTPUT ;
    USE SIGNAL ;
    SHAPE ABUTMENT ;
    PORT
      LAYER metal3 ;
      RECT 1747.305 0.000 1747.375 0.210 ;
    END
  END r0_rd_out[243]
  PIN r0_rd_out[244]
    DIRECTION OUTPUT ;
    USE SIGNAL ;
    SHAPE ABUTMENT ;
    PORT
      LAYER metal3 ;
      RECT 1750.805 0.000 1750.875 0.210 ;
    END
  END r0_rd_out[244]
  PIN r0_rd_out[245]
    DIRECTION OUTPUT ;
    USE SIGNAL ;
    SHAPE ABUTMENT ;
    PORT
      LAYER metal3 ;
      RECT 1754.305 0.000 1754.375 0.210 ;
    END
  END r0_rd_out[245]
  PIN r0_rd_out[246]
    DIRECTION OUTPUT ;
    USE SIGNAL ;
    SHAPE ABUTMENT ;
    PORT
      LAYER metal3 ;
      RECT 1757.805 0.000 1757.875 0.210 ;
    END
  END r0_rd_out[246]
  PIN r0_rd_out[247]
    DIRECTION OUTPUT ;
    USE SIGNAL ;
    SHAPE ABUTMENT ;
    PORT
      LAYER metal3 ;
      RECT 1761.305 0.000 1761.375 0.210 ;
    END
  END r0_rd_out[247]
  PIN r0_rd_out[248]
    DIRECTION OUTPUT ;
    USE SIGNAL ;
    SHAPE ABUTMENT ;
    PORT
      LAYER metal3 ;
      RECT 1764.805 0.000 1764.875 0.210 ;
    END
  END r0_rd_out[248]
  PIN r0_rd_out[249]
    DIRECTION OUTPUT ;
    USE SIGNAL ;
    SHAPE ABUTMENT ;
    PORT
      LAYER metal3 ;
      RECT 1768.305 0.000 1768.375 0.210 ;
    END
  END r0_rd_out[249]
  PIN r0_rd_out[250]
    DIRECTION OUTPUT ;
    USE SIGNAL ;
    SHAPE ABUTMENT ;
    PORT
      LAYER metal3 ;
      RECT 1771.805 0.000 1771.875 0.210 ;
    END
  END r0_rd_out[250]
  PIN r0_rd_out[251]
    DIRECTION OUTPUT ;
    USE SIGNAL ;
    SHAPE ABUTMENT ;
    PORT
      LAYER metal3 ;
      RECT 1775.305 0.000 1775.375 0.210 ;
    END
  END r0_rd_out[251]
  PIN r0_rd_out[252]
    DIRECTION OUTPUT ;
    USE SIGNAL ;
    SHAPE ABUTMENT ;
    PORT
      LAYER metal3 ;
      RECT 1778.805 0.000 1778.875 0.210 ;
    END
  END r0_rd_out[252]
  PIN r0_rd_out[253]
    DIRECTION OUTPUT ;
    USE SIGNAL ;
    SHAPE ABUTMENT ;
    PORT
      LAYER metal3 ;
      RECT 1782.305 0.000 1782.375 0.210 ;
    END
  END r0_rd_out[253]
  PIN r0_rd_out[254]
    DIRECTION OUTPUT ;
    USE SIGNAL ;
    SHAPE ABUTMENT ;
    PORT
      LAYER metal3 ;
      RECT 1785.805 0.000 1785.875 0.210 ;
    END
  END r0_rd_out[254]
  PIN r0_rd_out[255]
    DIRECTION OUTPUT ;
    USE SIGNAL ;
    SHAPE ABUTMENT ;
    PORT
      LAYER metal3 ;
      RECT 1789.305 0.000 1789.375 0.210 ;
    END
  END r0_rd_out[255]
  PIN r0_rd_out[256]
    DIRECTION OUTPUT ;
    USE SIGNAL ;
    SHAPE ABUTMENT ;
    PORT
      LAYER metal3 ;
      RECT 0.805 981.190 0.875 981.400 ;
    END
  END r0_rd_out[256]
  PIN r0_rd_out[257]
    DIRECTION OUTPUT ;
    USE SIGNAL ;
    SHAPE ABUTMENT ;
    PORT
      LAYER metal3 ;
      RECT 7.805 981.190 7.875 981.400 ;
    END
  END r0_rd_out[257]
  PIN r0_rd_out[258]
    DIRECTION OUTPUT ;
    USE SIGNAL ;
    SHAPE ABUTMENT ;
    PORT
      LAYER metal3 ;
      RECT 14.805 981.190 14.875 981.400 ;
    END
  END r0_rd_out[258]
  PIN r0_rd_out[259]
    DIRECTION OUTPUT ;
    USE SIGNAL ;
    SHAPE ABUTMENT ;
    PORT
      LAYER metal3 ;
      RECT 21.805 981.190 21.875 981.400 ;
    END
  END r0_rd_out[259]
  PIN r0_rd_out[260]
    DIRECTION OUTPUT ;
    USE SIGNAL ;
    SHAPE ABUTMENT ;
    PORT
      LAYER metal3 ;
      RECT 28.805 981.190 28.875 981.400 ;
    END
  END r0_rd_out[260]
  PIN r0_rd_out[261]
    DIRECTION OUTPUT ;
    USE SIGNAL ;
    SHAPE ABUTMENT ;
    PORT
      LAYER metal3 ;
      RECT 35.805 981.190 35.875 981.400 ;
    END
  END r0_rd_out[261]
  PIN r0_rd_out[262]
    DIRECTION OUTPUT ;
    USE SIGNAL ;
    SHAPE ABUTMENT ;
    PORT
      LAYER metal3 ;
      RECT 42.805 981.190 42.875 981.400 ;
    END
  END r0_rd_out[262]
  PIN r0_rd_out[263]
    DIRECTION OUTPUT ;
    USE SIGNAL ;
    SHAPE ABUTMENT ;
    PORT
      LAYER metal3 ;
      RECT 49.805 981.190 49.875 981.400 ;
    END
  END r0_rd_out[263]
  PIN r0_rd_out[264]
    DIRECTION OUTPUT ;
    USE SIGNAL ;
    SHAPE ABUTMENT ;
    PORT
      LAYER metal3 ;
      RECT 56.805 981.190 56.875 981.400 ;
    END
  END r0_rd_out[264]
  PIN r0_rd_out[265]
    DIRECTION OUTPUT ;
    USE SIGNAL ;
    SHAPE ABUTMENT ;
    PORT
      LAYER metal3 ;
      RECT 63.805 981.190 63.875 981.400 ;
    END
  END r0_rd_out[265]
  PIN r0_rd_out[266]
    DIRECTION OUTPUT ;
    USE SIGNAL ;
    SHAPE ABUTMENT ;
    PORT
      LAYER metal3 ;
      RECT 70.805 981.190 70.875 981.400 ;
    END
  END r0_rd_out[266]
  PIN r0_rd_out[267]
    DIRECTION OUTPUT ;
    USE SIGNAL ;
    SHAPE ABUTMENT ;
    PORT
      LAYER metal3 ;
      RECT 77.805 981.190 77.875 981.400 ;
    END
  END r0_rd_out[267]
  PIN r0_rd_out[268]
    DIRECTION OUTPUT ;
    USE SIGNAL ;
    SHAPE ABUTMENT ;
    PORT
      LAYER metal3 ;
      RECT 84.805 981.190 84.875 981.400 ;
    END
  END r0_rd_out[268]
  PIN r0_rd_out[269]
    DIRECTION OUTPUT ;
    USE SIGNAL ;
    SHAPE ABUTMENT ;
    PORT
      LAYER metal3 ;
      RECT 91.805 981.190 91.875 981.400 ;
    END
  END r0_rd_out[269]
  PIN r0_rd_out[270]
    DIRECTION OUTPUT ;
    USE SIGNAL ;
    SHAPE ABUTMENT ;
    PORT
      LAYER metal3 ;
      RECT 98.805 981.190 98.875 981.400 ;
    END
  END r0_rd_out[270]
  PIN r0_rd_out[271]
    DIRECTION OUTPUT ;
    USE SIGNAL ;
    SHAPE ABUTMENT ;
    PORT
      LAYER metal3 ;
      RECT 105.805 981.190 105.875 981.400 ;
    END
  END r0_rd_out[271]
  PIN r0_rd_out[272]
    DIRECTION OUTPUT ;
    USE SIGNAL ;
    SHAPE ABUTMENT ;
    PORT
      LAYER metal3 ;
      RECT 112.805 981.190 112.875 981.400 ;
    END
  END r0_rd_out[272]
  PIN r0_rd_out[273]
    DIRECTION OUTPUT ;
    USE SIGNAL ;
    SHAPE ABUTMENT ;
    PORT
      LAYER metal3 ;
      RECT 119.805 981.190 119.875 981.400 ;
    END
  END r0_rd_out[273]
  PIN r0_rd_out[274]
    DIRECTION OUTPUT ;
    USE SIGNAL ;
    SHAPE ABUTMENT ;
    PORT
      LAYER metal3 ;
      RECT 126.805 981.190 126.875 981.400 ;
    END
  END r0_rd_out[274]
  PIN r0_rd_out[275]
    DIRECTION OUTPUT ;
    USE SIGNAL ;
    SHAPE ABUTMENT ;
    PORT
      LAYER metal3 ;
      RECT 133.805 981.190 133.875 981.400 ;
    END
  END r0_rd_out[275]
  PIN r0_rd_out[276]
    DIRECTION OUTPUT ;
    USE SIGNAL ;
    SHAPE ABUTMENT ;
    PORT
      LAYER metal3 ;
      RECT 140.805 981.190 140.875 981.400 ;
    END
  END r0_rd_out[276]
  PIN r0_rd_out[277]
    DIRECTION OUTPUT ;
    USE SIGNAL ;
    SHAPE ABUTMENT ;
    PORT
      LAYER metal3 ;
      RECT 147.805 981.190 147.875 981.400 ;
    END
  END r0_rd_out[277]
  PIN r0_rd_out[278]
    DIRECTION OUTPUT ;
    USE SIGNAL ;
    SHAPE ABUTMENT ;
    PORT
      LAYER metal3 ;
      RECT 154.805 981.190 154.875 981.400 ;
    END
  END r0_rd_out[278]
  PIN r0_rd_out[279]
    DIRECTION OUTPUT ;
    USE SIGNAL ;
    SHAPE ABUTMENT ;
    PORT
      LAYER metal3 ;
      RECT 161.805 981.190 161.875 981.400 ;
    END
  END r0_rd_out[279]
  PIN r0_rd_out[280]
    DIRECTION OUTPUT ;
    USE SIGNAL ;
    SHAPE ABUTMENT ;
    PORT
      LAYER metal3 ;
      RECT 168.805 981.190 168.875 981.400 ;
    END
  END r0_rd_out[280]
  PIN r0_rd_out[281]
    DIRECTION OUTPUT ;
    USE SIGNAL ;
    SHAPE ABUTMENT ;
    PORT
      LAYER metal3 ;
      RECT 175.805 981.190 175.875 981.400 ;
    END
  END r0_rd_out[281]
  PIN r0_rd_out[282]
    DIRECTION OUTPUT ;
    USE SIGNAL ;
    SHAPE ABUTMENT ;
    PORT
      LAYER metal3 ;
      RECT 182.805 981.190 182.875 981.400 ;
    END
  END r0_rd_out[282]
  PIN r0_rd_out[283]
    DIRECTION OUTPUT ;
    USE SIGNAL ;
    SHAPE ABUTMENT ;
    PORT
      LAYER metal3 ;
      RECT 189.805 981.190 189.875 981.400 ;
    END
  END r0_rd_out[283]
  PIN r0_rd_out[284]
    DIRECTION OUTPUT ;
    USE SIGNAL ;
    SHAPE ABUTMENT ;
    PORT
      LAYER metal3 ;
      RECT 196.805 981.190 196.875 981.400 ;
    END
  END r0_rd_out[284]
  PIN r0_rd_out[285]
    DIRECTION OUTPUT ;
    USE SIGNAL ;
    SHAPE ABUTMENT ;
    PORT
      LAYER metal3 ;
      RECT 203.805 981.190 203.875 981.400 ;
    END
  END r0_rd_out[285]
  PIN r0_rd_out[286]
    DIRECTION OUTPUT ;
    USE SIGNAL ;
    SHAPE ABUTMENT ;
    PORT
      LAYER metal3 ;
      RECT 210.805 981.190 210.875 981.400 ;
    END
  END r0_rd_out[286]
  PIN r0_rd_out[287]
    DIRECTION OUTPUT ;
    USE SIGNAL ;
    SHAPE ABUTMENT ;
    PORT
      LAYER metal3 ;
      RECT 217.805 981.190 217.875 981.400 ;
    END
  END r0_rd_out[287]
  PIN r0_rd_out[288]
    DIRECTION OUTPUT ;
    USE SIGNAL ;
    SHAPE ABUTMENT ;
    PORT
      LAYER metal3 ;
      RECT 224.805 981.190 224.875 981.400 ;
    END
  END r0_rd_out[288]
  PIN r0_rd_out[289]
    DIRECTION OUTPUT ;
    USE SIGNAL ;
    SHAPE ABUTMENT ;
    PORT
      LAYER metal3 ;
      RECT 231.805 981.190 231.875 981.400 ;
    END
  END r0_rd_out[289]
  PIN r0_rd_out[290]
    DIRECTION OUTPUT ;
    USE SIGNAL ;
    SHAPE ABUTMENT ;
    PORT
      LAYER metal3 ;
      RECT 238.805 981.190 238.875 981.400 ;
    END
  END r0_rd_out[290]
  PIN r0_rd_out[291]
    DIRECTION OUTPUT ;
    USE SIGNAL ;
    SHAPE ABUTMENT ;
    PORT
      LAYER metal3 ;
      RECT 245.805 981.190 245.875 981.400 ;
    END
  END r0_rd_out[291]
  PIN r0_rd_out[292]
    DIRECTION OUTPUT ;
    USE SIGNAL ;
    SHAPE ABUTMENT ;
    PORT
      LAYER metal3 ;
      RECT 252.805 981.190 252.875 981.400 ;
    END
  END r0_rd_out[292]
  PIN r0_rd_out[293]
    DIRECTION OUTPUT ;
    USE SIGNAL ;
    SHAPE ABUTMENT ;
    PORT
      LAYER metal3 ;
      RECT 259.805 981.190 259.875 981.400 ;
    END
  END r0_rd_out[293]
  PIN r0_rd_out[294]
    DIRECTION OUTPUT ;
    USE SIGNAL ;
    SHAPE ABUTMENT ;
    PORT
      LAYER metal3 ;
      RECT 266.805 981.190 266.875 981.400 ;
    END
  END r0_rd_out[294]
  PIN r0_rd_out[295]
    DIRECTION OUTPUT ;
    USE SIGNAL ;
    SHAPE ABUTMENT ;
    PORT
      LAYER metal3 ;
      RECT 273.805 981.190 273.875 981.400 ;
    END
  END r0_rd_out[295]
  PIN r0_rd_out[296]
    DIRECTION OUTPUT ;
    USE SIGNAL ;
    SHAPE ABUTMENT ;
    PORT
      LAYER metal3 ;
      RECT 280.805 981.190 280.875 981.400 ;
    END
  END r0_rd_out[296]
  PIN r0_rd_out[297]
    DIRECTION OUTPUT ;
    USE SIGNAL ;
    SHAPE ABUTMENT ;
    PORT
      LAYER metal3 ;
      RECT 287.805 981.190 287.875 981.400 ;
    END
  END r0_rd_out[297]
  PIN r0_rd_out[298]
    DIRECTION OUTPUT ;
    USE SIGNAL ;
    SHAPE ABUTMENT ;
    PORT
      LAYER metal3 ;
      RECT 294.805 981.190 294.875 981.400 ;
    END
  END r0_rd_out[298]
  PIN r0_rd_out[299]
    DIRECTION OUTPUT ;
    USE SIGNAL ;
    SHAPE ABUTMENT ;
    PORT
      LAYER metal3 ;
      RECT 301.805 981.190 301.875 981.400 ;
    END
  END r0_rd_out[299]
  PIN r0_rd_out[300]
    DIRECTION OUTPUT ;
    USE SIGNAL ;
    SHAPE ABUTMENT ;
    PORT
      LAYER metal3 ;
      RECT 308.805 981.190 308.875 981.400 ;
    END
  END r0_rd_out[300]
  PIN r0_rd_out[301]
    DIRECTION OUTPUT ;
    USE SIGNAL ;
    SHAPE ABUTMENT ;
    PORT
      LAYER metal3 ;
      RECT 315.805 981.190 315.875 981.400 ;
    END
  END r0_rd_out[301]
  PIN r0_rd_out[302]
    DIRECTION OUTPUT ;
    USE SIGNAL ;
    SHAPE ABUTMENT ;
    PORT
      LAYER metal3 ;
      RECT 322.805 981.190 322.875 981.400 ;
    END
  END r0_rd_out[302]
  PIN r0_rd_out[303]
    DIRECTION OUTPUT ;
    USE SIGNAL ;
    SHAPE ABUTMENT ;
    PORT
      LAYER metal3 ;
      RECT 329.805 981.190 329.875 981.400 ;
    END
  END r0_rd_out[303]
  PIN r0_rd_out[304]
    DIRECTION OUTPUT ;
    USE SIGNAL ;
    SHAPE ABUTMENT ;
    PORT
      LAYER metal3 ;
      RECT 336.805 981.190 336.875 981.400 ;
    END
  END r0_rd_out[304]
  PIN r0_rd_out[305]
    DIRECTION OUTPUT ;
    USE SIGNAL ;
    SHAPE ABUTMENT ;
    PORT
      LAYER metal3 ;
      RECT 343.805 981.190 343.875 981.400 ;
    END
  END r0_rd_out[305]
  PIN r0_rd_out[306]
    DIRECTION OUTPUT ;
    USE SIGNAL ;
    SHAPE ABUTMENT ;
    PORT
      LAYER metal3 ;
      RECT 350.805 981.190 350.875 981.400 ;
    END
  END r0_rd_out[306]
  PIN r0_rd_out[307]
    DIRECTION OUTPUT ;
    USE SIGNAL ;
    SHAPE ABUTMENT ;
    PORT
      LAYER metal3 ;
      RECT 357.805 981.190 357.875 981.400 ;
    END
  END r0_rd_out[307]
  PIN r0_rd_out[308]
    DIRECTION OUTPUT ;
    USE SIGNAL ;
    SHAPE ABUTMENT ;
    PORT
      LAYER metal3 ;
      RECT 364.805 981.190 364.875 981.400 ;
    END
  END r0_rd_out[308]
  PIN r0_rd_out[309]
    DIRECTION OUTPUT ;
    USE SIGNAL ;
    SHAPE ABUTMENT ;
    PORT
      LAYER metal3 ;
      RECT 371.805 981.190 371.875 981.400 ;
    END
  END r0_rd_out[309]
  PIN r0_rd_out[310]
    DIRECTION OUTPUT ;
    USE SIGNAL ;
    SHAPE ABUTMENT ;
    PORT
      LAYER metal3 ;
      RECT 378.805 981.190 378.875 981.400 ;
    END
  END r0_rd_out[310]
  PIN r0_rd_out[311]
    DIRECTION OUTPUT ;
    USE SIGNAL ;
    SHAPE ABUTMENT ;
    PORT
      LAYER metal3 ;
      RECT 385.805 981.190 385.875 981.400 ;
    END
  END r0_rd_out[311]
  PIN r0_rd_out[312]
    DIRECTION OUTPUT ;
    USE SIGNAL ;
    SHAPE ABUTMENT ;
    PORT
      LAYER metal3 ;
      RECT 392.805 981.190 392.875 981.400 ;
    END
  END r0_rd_out[312]
  PIN r0_rd_out[313]
    DIRECTION OUTPUT ;
    USE SIGNAL ;
    SHAPE ABUTMENT ;
    PORT
      LAYER metal3 ;
      RECT 399.805 981.190 399.875 981.400 ;
    END
  END r0_rd_out[313]
  PIN r0_rd_out[314]
    DIRECTION OUTPUT ;
    USE SIGNAL ;
    SHAPE ABUTMENT ;
    PORT
      LAYER metal3 ;
      RECT 406.805 981.190 406.875 981.400 ;
    END
  END r0_rd_out[314]
  PIN r0_rd_out[315]
    DIRECTION OUTPUT ;
    USE SIGNAL ;
    SHAPE ABUTMENT ;
    PORT
      LAYER metal3 ;
      RECT 413.805 981.190 413.875 981.400 ;
    END
  END r0_rd_out[315]
  PIN r0_rd_out[316]
    DIRECTION OUTPUT ;
    USE SIGNAL ;
    SHAPE ABUTMENT ;
    PORT
      LAYER metal3 ;
      RECT 420.805 981.190 420.875 981.400 ;
    END
  END r0_rd_out[316]
  PIN r0_rd_out[317]
    DIRECTION OUTPUT ;
    USE SIGNAL ;
    SHAPE ABUTMENT ;
    PORT
      LAYER metal3 ;
      RECT 427.805 981.190 427.875 981.400 ;
    END
  END r0_rd_out[317]
  PIN r0_rd_out[318]
    DIRECTION OUTPUT ;
    USE SIGNAL ;
    SHAPE ABUTMENT ;
    PORT
      LAYER metal3 ;
      RECT 434.805 981.190 434.875 981.400 ;
    END
  END r0_rd_out[318]
  PIN r0_rd_out[319]
    DIRECTION OUTPUT ;
    USE SIGNAL ;
    SHAPE ABUTMENT ;
    PORT
      LAYER metal3 ;
      RECT 441.805 981.190 441.875 981.400 ;
    END
  END r0_rd_out[319]
  PIN r0_rd_out[320]
    DIRECTION OUTPUT ;
    USE SIGNAL ;
    SHAPE ABUTMENT ;
    PORT
      LAYER metal3 ;
      RECT 448.805 981.190 448.875 981.400 ;
    END
  END r0_rd_out[320]
  PIN r0_rd_out[321]
    DIRECTION OUTPUT ;
    USE SIGNAL ;
    SHAPE ABUTMENT ;
    PORT
      LAYER metal3 ;
      RECT 455.805 981.190 455.875 981.400 ;
    END
  END r0_rd_out[321]
  PIN r0_rd_out[322]
    DIRECTION OUTPUT ;
    USE SIGNAL ;
    SHAPE ABUTMENT ;
    PORT
      LAYER metal3 ;
      RECT 462.805 981.190 462.875 981.400 ;
    END
  END r0_rd_out[322]
  PIN r0_rd_out[323]
    DIRECTION OUTPUT ;
    USE SIGNAL ;
    SHAPE ABUTMENT ;
    PORT
      LAYER metal3 ;
      RECT 469.805 981.190 469.875 981.400 ;
    END
  END r0_rd_out[323]
  PIN r0_rd_out[324]
    DIRECTION OUTPUT ;
    USE SIGNAL ;
    SHAPE ABUTMENT ;
    PORT
      LAYER metal3 ;
      RECT 476.805 981.190 476.875 981.400 ;
    END
  END r0_rd_out[324]
  PIN r0_rd_out[325]
    DIRECTION OUTPUT ;
    USE SIGNAL ;
    SHAPE ABUTMENT ;
    PORT
      LAYER metal3 ;
      RECT 483.805 981.190 483.875 981.400 ;
    END
  END r0_rd_out[325]
  PIN r0_rd_out[326]
    DIRECTION OUTPUT ;
    USE SIGNAL ;
    SHAPE ABUTMENT ;
    PORT
      LAYER metal3 ;
      RECT 490.805 981.190 490.875 981.400 ;
    END
  END r0_rd_out[326]
  PIN r0_rd_out[327]
    DIRECTION OUTPUT ;
    USE SIGNAL ;
    SHAPE ABUTMENT ;
    PORT
      LAYER metal3 ;
      RECT 497.805 981.190 497.875 981.400 ;
    END
  END r0_rd_out[327]
  PIN r0_rd_out[328]
    DIRECTION OUTPUT ;
    USE SIGNAL ;
    SHAPE ABUTMENT ;
    PORT
      LAYER metal3 ;
      RECT 504.805 981.190 504.875 981.400 ;
    END
  END r0_rd_out[328]
  PIN r0_rd_out[329]
    DIRECTION OUTPUT ;
    USE SIGNAL ;
    SHAPE ABUTMENT ;
    PORT
      LAYER metal3 ;
      RECT 511.805 981.190 511.875 981.400 ;
    END
  END r0_rd_out[329]
  PIN r0_rd_out[330]
    DIRECTION OUTPUT ;
    USE SIGNAL ;
    SHAPE ABUTMENT ;
    PORT
      LAYER metal3 ;
      RECT 518.805 981.190 518.875 981.400 ;
    END
  END r0_rd_out[330]
  PIN r0_rd_out[331]
    DIRECTION OUTPUT ;
    USE SIGNAL ;
    SHAPE ABUTMENT ;
    PORT
      LAYER metal3 ;
      RECT 525.805 981.190 525.875 981.400 ;
    END
  END r0_rd_out[331]
  PIN r0_rd_out[332]
    DIRECTION OUTPUT ;
    USE SIGNAL ;
    SHAPE ABUTMENT ;
    PORT
      LAYER metal3 ;
      RECT 532.805 981.190 532.875 981.400 ;
    END
  END r0_rd_out[332]
  PIN r0_rd_out[333]
    DIRECTION OUTPUT ;
    USE SIGNAL ;
    SHAPE ABUTMENT ;
    PORT
      LAYER metal3 ;
      RECT 539.805 981.190 539.875 981.400 ;
    END
  END r0_rd_out[333]
  PIN r0_rd_out[334]
    DIRECTION OUTPUT ;
    USE SIGNAL ;
    SHAPE ABUTMENT ;
    PORT
      LAYER metal3 ;
      RECT 546.805 981.190 546.875 981.400 ;
    END
  END r0_rd_out[334]
  PIN r0_rd_out[335]
    DIRECTION OUTPUT ;
    USE SIGNAL ;
    SHAPE ABUTMENT ;
    PORT
      LAYER metal3 ;
      RECT 553.805 981.190 553.875 981.400 ;
    END
  END r0_rd_out[335]
  PIN r0_rd_out[336]
    DIRECTION OUTPUT ;
    USE SIGNAL ;
    SHAPE ABUTMENT ;
    PORT
      LAYER metal3 ;
      RECT 560.805 981.190 560.875 981.400 ;
    END
  END r0_rd_out[336]
  PIN r0_rd_out[337]
    DIRECTION OUTPUT ;
    USE SIGNAL ;
    SHAPE ABUTMENT ;
    PORT
      LAYER metal3 ;
      RECT 567.805 981.190 567.875 981.400 ;
    END
  END r0_rd_out[337]
  PIN r0_rd_out[338]
    DIRECTION OUTPUT ;
    USE SIGNAL ;
    SHAPE ABUTMENT ;
    PORT
      LAYER metal3 ;
      RECT 574.805 981.190 574.875 981.400 ;
    END
  END r0_rd_out[338]
  PIN r0_rd_out[339]
    DIRECTION OUTPUT ;
    USE SIGNAL ;
    SHAPE ABUTMENT ;
    PORT
      LAYER metal3 ;
      RECT 581.805 981.190 581.875 981.400 ;
    END
  END r0_rd_out[339]
  PIN r0_rd_out[340]
    DIRECTION OUTPUT ;
    USE SIGNAL ;
    SHAPE ABUTMENT ;
    PORT
      LAYER metal3 ;
      RECT 588.805 981.190 588.875 981.400 ;
    END
  END r0_rd_out[340]
  PIN r0_rd_out[341]
    DIRECTION OUTPUT ;
    USE SIGNAL ;
    SHAPE ABUTMENT ;
    PORT
      LAYER metal3 ;
      RECT 595.805 981.190 595.875 981.400 ;
    END
  END r0_rd_out[341]
  PIN r0_rd_out[342]
    DIRECTION OUTPUT ;
    USE SIGNAL ;
    SHAPE ABUTMENT ;
    PORT
      LAYER metal3 ;
      RECT 602.805 981.190 602.875 981.400 ;
    END
  END r0_rd_out[342]
  PIN r0_rd_out[343]
    DIRECTION OUTPUT ;
    USE SIGNAL ;
    SHAPE ABUTMENT ;
    PORT
      LAYER metal3 ;
      RECT 609.805 981.190 609.875 981.400 ;
    END
  END r0_rd_out[343]
  PIN r0_rd_out[344]
    DIRECTION OUTPUT ;
    USE SIGNAL ;
    SHAPE ABUTMENT ;
    PORT
      LAYER metal3 ;
      RECT 616.805 981.190 616.875 981.400 ;
    END
  END r0_rd_out[344]
  PIN r0_rd_out[345]
    DIRECTION OUTPUT ;
    USE SIGNAL ;
    SHAPE ABUTMENT ;
    PORT
      LAYER metal3 ;
      RECT 623.805 981.190 623.875 981.400 ;
    END
  END r0_rd_out[345]
  PIN r0_rd_out[346]
    DIRECTION OUTPUT ;
    USE SIGNAL ;
    SHAPE ABUTMENT ;
    PORT
      LAYER metal3 ;
      RECT 630.805 981.190 630.875 981.400 ;
    END
  END r0_rd_out[346]
  PIN r0_rd_out[347]
    DIRECTION OUTPUT ;
    USE SIGNAL ;
    SHAPE ABUTMENT ;
    PORT
      LAYER metal3 ;
      RECT 637.805 981.190 637.875 981.400 ;
    END
  END r0_rd_out[347]
  PIN r0_rd_out[348]
    DIRECTION OUTPUT ;
    USE SIGNAL ;
    SHAPE ABUTMENT ;
    PORT
      LAYER metal3 ;
      RECT 644.805 981.190 644.875 981.400 ;
    END
  END r0_rd_out[348]
  PIN r0_rd_out[349]
    DIRECTION OUTPUT ;
    USE SIGNAL ;
    SHAPE ABUTMENT ;
    PORT
      LAYER metal3 ;
      RECT 651.805 981.190 651.875 981.400 ;
    END
  END r0_rd_out[349]
  PIN r0_rd_out[350]
    DIRECTION OUTPUT ;
    USE SIGNAL ;
    SHAPE ABUTMENT ;
    PORT
      LAYER metal3 ;
      RECT 658.805 981.190 658.875 981.400 ;
    END
  END r0_rd_out[350]
  PIN r0_rd_out[351]
    DIRECTION OUTPUT ;
    USE SIGNAL ;
    SHAPE ABUTMENT ;
    PORT
      LAYER metal3 ;
      RECT 665.805 981.190 665.875 981.400 ;
    END
  END r0_rd_out[351]
  PIN r0_rd_out[352]
    DIRECTION OUTPUT ;
    USE SIGNAL ;
    SHAPE ABUTMENT ;
    PORT
      LAYER metal3 ;
      RECT 672.805 981.190 672.875 981.400 ;
    END
  END r0_rd_out[352]
  PIN r0_rd_out[353]
    DIRECTION OUTPUT ;
    USE SIGNAL ;
    SHAPE ABUTMENT ;
    PORT
      LAYER metal3 ;
      RECT 679.805 981.190 679.875 981.400 ;
    END
  END r0_rd_out[353]
  PIN r0_rd_out[354]
    DIRECTION OUTPUT ;
    USE SIGNAL ;
    SHAPE ABUTMENT ;
    PORT
      LAYER metal3 ;
      RECT 686.805 981.190 686.875 981.400 ;
    END
  END r0_rd_out[354]
  PIN r0_rd_out[355]
    DIRECTION OUTPUT ;
    USE SIGNAL ;
    SHAPE ABUTMENT ;
    PORT
      LAYER metal3 ;
      RECT 693.805 981.190 693.875 981.400 ;
    END
  END r0_rd_out[355]
  PIN r0_rd_out[356]
    DIRECTION OUTPUT ;
    USE SIGNAL ;
    SHAPE ABUTMENT ;
    PORT
      LAYER metal3 ;
      RECT 700.805 981.190 700.875 981.400 ;
    END
  END r0_rd_out[356]
  PIN r0_rd_out[357]
    DIRECTION OUTPUT ;
    USE SIGNAL ;
    SHAPE ABUTMENT ;
    PORT
      LAYER metal3 ;
      RECT 707.805 981.190 707.875 981.400 ;
    END
  END r0_rd_out[357]
  PIN r0_rd_out[358]
    DIRECTION OUTPUT ;
    USE SIGNAL ;
    SHAPE ABUTMENT ;
    PORT
      LAYER metal3 ;
      RECT 714.805 981.190 714.875 981.400 ;
    END
  END r0_rd_out[358]
  PIN r0_rd_out[359]
    DIRECTION OUTPUT ;
    USE SIGNAL ;
    SHAPE ABUTMENT ;
    PORT
      LAYER metal3 ;
      RECT 721.805 981.190 721.875 981.400 ;
    END
  END r0_rd_out[359]
  PIN r0_rd_out[360]
    DIRECTION OUTPUT ;
    USE SIGNAL ;
    SHAPE ABUTMENT ;
    PORT
      LAYER metal3 ;
      RECT 728.805 981.190 728.875 981.400 ;
    END
  END r0_rd_out[360]
  PIN r0_rd_out[361]
    DIRECTION OUTPUT ;
    USE SIGNAL ;
    SHAPE ABUTMENT ;
    PORT
      LAYER metal3 ;
      RECT 735.805 981.190 735.875 981.400 ;
    END
  END r0_rd_out[361]
  PIN r0_rd_out[362]
    DIRECTION OUTPUT ;
    USE SIGNAL ;
    SHAPE ABUTMENT ;
    PORT
      LAYER metal3 ;
      RECT 742.805 981.190 742.875 981.400 ;
    END
  END r0_rd_out[362]
  PIN r0_rd_out[363]
    DIRECTION OUTPUT ;
    USE SIGNAL ;
    SHAPE ABUTMENT ;
    PORT
      LAYER metal3 ;
      RECT 749.805 981.190 749.875 981.400 ;
    END
  END r0_rd_out[363]
  PIN r0_rd_out[364]
    DIRECTION OUTPUT ;
    USE SIGNAL ;
    SHAPE ABUTMENT ;
    PORT
      LAYER metal3 ;
      RECT 756.805 981.190 756.875 981.400 ;
    END
  END r0_rd_out[364]
  PIN r0_rd_out[365]
    DIRECTION OUTPUT ;
    USE SIGNAL ;
    SHAPE ABUTMENT ;
    PORT
      LAYER metal3 ;
      RECT 763.805 981.190 763.875 981.400 ;
    END
  END r0_rd_out[365]
  PIN r0_rd_out[366]
    DIRECTION OUTPUT ;
    USE SIGNAL ;
    SHAPE ABUTMENT ;
    PORT
      LAYER metal3 ;
      RECT 770.805 981.190 770.875 981.400 ;
    END
  END r0_rd_out[366]
  PIN r0_rd_out[367]
    DIRECTION OUTPUT ;
    USE SIGNAL ;
    SHAPE ABUTMENT ;
    PORT
      LAYER metal3 ;
      RECT 777.805 981.190 777.875 981.400 ;
    END
  END r0_rd_out[367]
  PIN r0_rd_out[368]
    DIRECTION OUTPUT ;
    USE SIGNAL ;
    SHAPE ABUTMENT ;
    PORT
      LAYER metal3 ;
      RECT 784.805 981.190 784.875 981.400 ;
    END
  END r0_rd_out[368]
  PIN r0_rd_out[369]
    DIRECTION OUTPUT ;
    USE SIGNAL ;
    SHAPE ABUTMENT ;
    PORT
      LAYER metal3 ;
      RECT 791.805 981.190 791.875 981.400 ;
    END
  END r0_rd_out[369]
  PIN r0_rd_out[370]
    DIRECTION OUTPUT ;
    USE SIGNAL ;
    SHAPE ABUTMENT ;
    PORT
      LAYER metal3 ;
      RECT 798.805 981.190 798.875 981.400 ;
    END
  END r0_rd_out[370]
  PIN r0_rd_out[371]
    DIRECTION OUTPUT ;
    USE SIGNAL ;
    SHAPE ABUTMENT ;
    PORT
      LAYER metal3 ;
      RECT 805.805 981.190 805.875 981.400 ;
    END
  END r0_rd_out[371]
  PIN r0_rd_out[372]
    DIRECTION OUTPUT ;
    USE SIGNAL ;
    SHAPE ABUTMENT ;
    PORT
      LAYER metal3 ;
      RECT 812.805 981.190 812.875 981.400 ;
    END
  END r0_rd_out[372]
  PIN r0_rd_out[373]
    DIRECTION OUTPUT ;
    USE SIGNAL ;
    SHAPE ABUTMENT ;
    PORT
      LAYER metal3 ;
      RECT 819.805 981.190 819.875 981.400 ;
    END
  END r0_rd_out[373]
  PIN r0_rd_out[374]
    DIRECTION OUTPUT ;
    USE SIGNAL ;
    SHAPE ABUTMENT ;
    PORT
      LAYER metal3 ;
      RECT 826.805 981.190 826.875 981.400 ;
    END
  END r0_rd_out[374]
  PIN r0_rd_out[375]
    DIRECTION OUTPUT ;
    USE SIGNAL ;
    SHAPE ABUTMENT ;
    PORT
      LAYER metal3 ;
      RECT 833.805 981.190 833.875 981.400 ;
    END
  END r0_rd_out[375]
  PIN r0_rd_out[376]
    DIRECTION OUTPUT ;
    USE SIGNAL ;
    SHAPE ABUTMENT ;
    PORT
      LAYER metal3 ;
      RECT 840.805 981.190 840.875 981.400 ;
    END
  END r0_rd_out[376]
  PIN r0_rd_out[377]
    DIRECTION OUTPUT ;
    USE SIGNAL ;
    SHAPE ABUTMENT ;
    PORT
      LAYER metal3 ;
      RECT 847.805 981.190 847.875 981.400 ;
    END
  END r0_rd_out[377]
  PIN r0_rd_out[378]
    DIRECTION OUTPUT ;
    USE SIGNAL ;
    SHAPE ABUTMENT ;
    PORT
      LAYER metal3 ;
      RECT 854.805 981.190 854.875 981.400 ;
    END
  END r0_rd_out[378]
  PIN r0_rd_out[379]
    DIRECTION OUTPUT ;
    USE SIGNAL ;
    SHAPE ABUTMENT ;
    PORT
      LAYER metal3 ;
      RECT 861.805 981.190 861.875 981.400 ;
    END
  END r0_rd_out[379]
  PIN r0_rd_out[380]
    DIRECTION OUTPUT ;
    USE SIGNAL ;
    SHAPE ABUTMENT ;
    PORT
      LAYER metal3 ;
      RECT 868.805 981.190 868.875 981.400 ;
    END
  END r0_rd_out[380]
  PIN r0_rd_out[381]
    DIRECTION OUTPUT ;
    USE SIGNAL ;
    SHAPE ABUTMENT ;
    PORT
      LAYER metal3 ;
      RECT 875.805 981.190 875.875 981.400 ;
    END
  END r0_rd_out[381]
  PIN r0_rd_out[382]
    DIRECTION OUTPUT ;
    USE SIGNAL ;
    SHAPE ABUTMENT ;
    PORT
      LAYER metal3 ;
      RECT 882.805 981.190 882.875 981.400 ;
    END
  END r0_rd_out[382]
  PIN r0_rd_out[383]
    DIRECTION OUTPUT ;
    USE SIGNAL ;
    SHAPE ABUTMENT ;
    PORT
      LAYER metal3 ;
      RECT 889.805 981.190 889.875 981.400 ;
    END
  END r0_rd_out[383]
  PIN r0_rd_out[384]
    DIRECTION OUTPUT ;
    USE SIGNAL ;
    SHAPE ABUTMENT ;
    PORT
      LAYER metal3 ;
      RECT 896.805 981.190 896.875 981.400 ;
    END
  END r0_rd_out[384]
  PIN r0_rd_out[385]
    DIRECTION OUTPUT ;
    USE SIGNAL ;
    SHAPE ABUTMENT ;
    PORT
      LAYER metal3 ;
      RECT 903.805 981.190 903.875 981.400 ;
    END
  END r0_rd_out[385]
  PIN r0_rd_out[386]
    DIRECTION OUTPUT ;
    USE SIGNAL ;
    SHAPE ABUTMENT ;
    PORT
      LAYER metal3 ;
      RECT 910.805 981.190 910.875 981.400 ;
    END
  END r0_rd_out[386]
  PIN r0_rd_out[387]
    DIRECTION OUTPUT ;
    USE SIGNAL ;
    SHAPE ABUTMENT ;
    PORT
      LAYER metal3 ;
      RECT 917.805 981.190 917.875 981.400 ;
    END
  END r0_rd_out[387]
  PIN r0_rd_out[388]
    DIRECTION OUTPUT ;
    USE SIGNAL ;
    SHAPE ABUTMENT ;
    PORT
      LAYER metal3 ;
      RECT 924.805 981.190 924.875 981.400 ;
    END
  END r0_rd_out[388]
  PIN r0_rd_out[389]
    DIRECTION OUTPUT ;
    USE SIGNAL ;
    SHAPE ABUTMENT ;
    PORT
      LAYER metal3 ;
      RECT 931.805 981.190 931.875 981.400 ;
    END
  END r0_rd_out[389]
  PIN r0_rd_out[390]
    DIRECTION OUTPUT ;
    USE SIGNAL ;
    SHAPE ABUTMENT ;
    PORT
      LAYER metal3 ;
      RECT 938.805 981.190 938.875 981.400 ;
    END
  END r0_rd_out[390]
  PIN r0_rd_out[391]
    DIRECTION OUTPUT ;
    USE SIGNAL ;
    SHAPE ABUTMENT ;
    PORT
      LAYER metal3 ;
      RECT 945.805 981.190 945.875 981.400 ;
    END
  END r0_rd_out[391]
  PIN r0_rd_out[392]
    DIRECTION OUTPUT ;
    USE SIGNAL ;
    SHAPE ABUTMENT ;
    PORT
      LAYER metal3 ;
      RECT 952.805 981.190 952.875 981.400 ;
    END
  END r0_rd_out[392]
  PIN r0_rd_out[393]
    DIRECTION OUTPUT ;
    USE SIGNAL ;
    SHAPE ABUTMENT ;
    PORT
      LAYER metal3 ;
      RECT 959.805 981.190 959.875 981.400 ;
    END
  END r0_rd_out[393]
  PIN r0_rd_out[394]
    DIRECTION OUTPUT ;
    USE SIGNAL ;
    SHAPE ABUTMENT ;
    PORT
      LAYER metal3 ;
      RECT 966.805 981.190 966.875 981.400 ;
    END
  END r0_rd_out[394]
  PIN r0_rd_out[395]
    DIRECTION OUTPUT ;
    USE SIGNAL ;
    SHAPE ABUTMENT ;
    PORT
      LAYER metal3 ;
      RECT 973.805 981.190 973.875 981.400 ;
    END
  END r0_rd_out[395]
  PIN r0_rd_out[396]
    DIRECTION OUTPUT ;
    USE SIGNAL ;
    SHAPE ABUTMENT ;
    PORT
      LAYER metal3 ;
      RECT 980.805 981.190 980.875 981.400 ;
    END
  END r0_rd_out[396]
  PIN r0_rd_out[397]
    DIRECTION OUTPUT ;
    USE SIGNAL ;
    SHAPE ABUTMENT ;
    PORT
      LAYER metal3 ;
      RECT 987.805 981.190 987.875 981.400 ;
    END
  END r0_rd_out[397]
  PIN r0_rd_out[398]
    DIRECTION OUTPUT ;
    USE SIGNAL ;
    SHAPE ABUTMENT ;
    PORT
      LAYER metal3 ;
      RECT 994.805 981.190 994.875 981.400 ;
    END
  END r0_rd_out[398]
  PIN r0_rd_out[399]
    DIRECTION OUTPUT ;
    USE SIGNAL ;
    SHAPE ABUTMENT ;
    PORT
      LAYER metal3 ;
      RECT 1001.805 981.190 1001.875 981.400 ;
    END
  END r0_rd_out[399]
  PIN r0_rd_out[400]
    DIRECTION OUTPUT ;
    USE SIGNAL ;
    SHAPE ABUTMENT ;
    PORT
      LAYER metal3 ;
      RECT 1008.805 981.190 1008.875 981.400 ;
    END
  END r0_rd_out[400]
  PIN r0_rd_out[401]
    DIRECTION OUTPUT ;
    USE SIGNAL ;
    SHAPE ABUTMENT ;
    PORT
      LAYER metal3 ;
      RECT 1015.805 981.190 1015.875 981.400 ;
    END
  END r0_rd_out[401]
  PIN r0_rd_out[402]
    DIRECTION OUTPUT ;
    USE SIGNAL ;
    SHAPE ABUTMENT ;
    PORT
      LAYER metal3 ;
      RECT 1022.805 981.190 1022.875 981.400 ;
    END
  END r0_rd_out[402]
  PIN r0_rd_out[403]
    DIRECTION OUTPUT ;
    USE SIGNAL ;
    SHAPE ABUTMENT ;
    PORT
      LAYER metal3 ;
      RECT 1029.805 981.190 1029.875 981.400 ;
    END
  END r0_rd_out[403]
  PIN r0_rd_out[404]
    DIRECTION OUTPUT ;
    USE SIGNAL ;
    SHAPE ABUTMENT ;
    PORT
      LAYER metal3 ;
      RECT 1036.805 981.190 1036.875 981.400 ;
    END
  END r0_rd_out[404]
  PIN r0_rd_out[405]
    DIRECTION OUTPUT ;
    USE SIGNAL ;
    SHAPE ABUTMENT ;
    PORT
      LAYER metal3 ;
      RECT 1043.805 981.190 1043.875 981.400 ;
    END
  END r0_rd_out[405]
  PIN r0_rd_out[406]
    DIRECTION OUTPUT ;
    USE SIGNAL ;
    SHAPE ABUTMENT ;
    PORT
      LAYER metal3 ;
      RECT 1050.805 981.190 1050.875 981.400 ;
    END
  END r0_rd_out[406]
  PIN r0_rd_out[407]
    DIRECTION OUTPUT ;
    USE SIGNAL ;
    SHAPE ABUTMENT ;
    PORT
      LAYER metal3 ;
      RECT 1057.805 981.190 1057.875 981.400 ;
    END
  END r0_rd_out[407]
  PIN r0_rd_out[408]
    DIRECTION OUTPUT ;
    USE SIGNAL ;
    SHAPE ABUTMENT ;
    PORT
      LAYER metal3 ;
      RECT 1064.805 981.190 1064.875 981.400 ;
    END
  END r0_rd_out[408]
  PIN r0_rd_out[409]
    DIRECTION OUTPUT ;
    USE SIGNAL ;
    SHAPE ABUTMENT ;
    PORT
      LAYER metal3 ;
      RECT 1071.805 981.190 1071.875 981.400 ;
    END
  END r0_rd_out[409]
  PIN r0_rd_out[410]
    DIRECTION OUTPUT ;
    USE SIGNAL ;
    SHAPE ABUTMENT ;
    PORT
      LAYER metal3 ;
      RECT 1078.805 981.190 1078.875 981.400 ;
    END
  END r0_rd_out[410]
  PIN r0_rd_out[411]
    DIRECTION OUTPUT ;
    USE SIGNAL ;
    SHAPE ABUTMENT ;
    PORT
      LAYER metal3 ;
      RECT 1085.805 981.190 1085.875 981.400 ;
    END
  END r0_rd_out[411]
  PIN r0_rd_out[412]
    DIRECTION OUTPUT ;
    USE SIGNAL ;
    SHAPE ABUTMENT ;
    PORT
      LAYER metal3 ;
      RECT 1092.805 981.190 1092.875 981.400 ;
    END
  END r0_rd_out[412]
  PIN r0_rd_out[413]
    DIRECTION OUTPUT ;
    USE SIGNAL ;
    SHAPE ABUTMENT ;
    PORT
      LAYER metal3 ;
      RECT 1099.805 981.190 1099.875 981.400 ;
    END
  END r0_rd_out[413]
  PIN r0_rd_out[414]
    DIRECTION OUTPUT ;
    USE SIGNAL ;
    SHAPE ABUTMENT ;
    PORT
      LAYER metal3 ;
      RECT 1106.805 981.190 1106.875 981.400 ;
    END
  END r0_rd_out[414]
  PIN r0_rd_out[415]
    DIRECTION OUTPUT ;
    USE SIGNAL ;
    SHAPE ABUTMENT ;
    PORT
      LAYER metal3 ;
      RECT 1113.805 981.190 1113.875 981.400 ;
    END
  END r0_rd_out[415]
  PIN r0_rd_out[416]
    DIRECTION OUTPUT ;
    USE SIGNAL ;
    SHAPE ABUTMENT ;
    PORT
      LAYER metal3 ;
      RECT 1120.805 981.190 1120.875 981.400 ;
    END
  END r0_rd_out[416]
  PIN r0_rd_out[417]
    DIRECTION OUTPUT ;
    USE SIGNAL ;
    SHAPE ABUTMENT ;
    PORT
      LAYER metal3 ;
      RECT 1127.805 981.190 1127.875 981.400 ;
    END
  END r0_rd_out[417]
  PIN r0_rd_out[418]
    DIRECTION OUTPUT ;
    USE SIGNAL ;
    SHAPE ABUTMENT ;
    PORT
      LAYER metal3 ;
      RECT 1134.805 981.190 1134.875 981.400 ;
    END
  END r0_rd_out[418]
  PIN r0_rd_out[419]
    DIRECTION OUTPUT ;
    USE SIGNAL ;
    SHAPE ABUTMENT ;
    PORT
      LAYER metal3 ;
      RECT 1141.805 981.190 1141.875 981.400 ;
    END
  END r0_rd_out[419]
  PIN r0_rd_out[420]
    DIRECTION OUTPUT ;
    USE SIGNAL ;
    SHAPE ABUTMENT ;
    PORT
      LAYER metal3 ;
      RECT 1148.805 981.190 1148.875 981.400 ;
    END
  END r0_rd_out[420]
  PIN r0_rd_out[421]
    DIRECTION OUTPUT ;
    USE SIGNAL ;
    SHAPE ABUTMENT ;
    PORT
      LAYER metal3 ;
      RECT 1155.805 981.190 1155.875 981.400 ;
    END
  END r0_rd_out[421]
  PIN r0_rd_out[422]
    DIRECTION OUTPUT ;
    USE SIGNAL ;
    SHAPE ABUTMENT ;
    PORT
      LAYER metal3 ;
      RECT 1162.805 981.190 1162.875 981.400 ;
    END
  END r0_rd_out[422]
  PIN r0_rd_out[423]
    DIRECTION OUTPUT ;
    USE SIGNAL ;
    SHAPE ABUTMENT ;
    PORT
      LAYER metal3 ;
      RECT 1169.805 981.190 1169.875 981.400 ;
    END
  END r0_rd_out[423]
  PIN r0_rd_out[424]
    DIRECTION OUTPUT ;
    USE SIGNAL ;
    SHAPE ABUTMENT ;
    PORT
      LAYER metal3 ;
      RECT 1176.805 981.190 1176.875 981.400 ;
    END
  END r0_rd_out[424]
  PIN r0_rd_out[425]
    DIRECTION OUTPUT ;
    USE SIGNAL ;
    SHAPE ABUTMENT ;
    PORT
      LAYER metal3 ;
      RECT 1183.805 981.190 1183.875 981.400 ;
    END
  END r0_rd_out[425]
  PIN r0_rd_out[426]
    DIRECTION OUTPUT ;
    USE SIGNAL ;
    SHAPE ABUTMENT ;
    PORT
      LAYER metal3 ;
      RECT 1190.805 981.190 1190.875 981.400 ;
    END
  END r0_rd_out[426]
  PIN r0_rd_out[427]
    DIRECTION OUTPUT ;
    USE SIGNAL ;
    SHAPE ABUTMENT ;
    PORT
      LAYER metal3 ;
      RECT 1197.805 981.190 1197.875 981.400 ;
    END
  END r0_rd_out[427]
  PIN r0_rd_out[428]
    DIRECTION OUTPUT ;
    USE SIGNAL ;
    SHAPE ABUTMENT ;
    PORT
      LAYER metal3 ;
      RECT 1204.805 981.190 1204.875 981.400 ;
    END
  END r0_rd_out[428]
  PIN r0_rd_out[429]
    DIRECTION OUTPUT ;
    USE SIGNAL ;
    SHAPE ABUTMENT ;
    PORT
      LAYER metal3 ;
      RECT 1211.805 981.190 1211.875 981.400 ;
    END
  END r0_rd_out[429]
  PIN r0_rd_out[430]
    DIRECTION OUTPUT ;
    USE SIGNAL ;
    SHAPE ABUTMENT ;
    PORT
      LAYER metal3 ;
      RECT 1218.805 981.190 1218.875 981.400 ;
    END
  END r0_rd_out[430]
  PIN r0_rd_out[431]
    DIRECTION OUTPUT ;
    USE SIGNAL ;
    SHAPE ABUTMENT ;
    PORT
      LAYER metal3 ;
      RECT 1225.805 981.190 1225.875 981.400 ;
    END
  END r0_rd_out[431]
  PIN r0_rd_out[432]
    DIRECTION OUTPUT ;
    USE SIGNAL ;
    SHAPE ABUTMENT ;
    PORT
      LAYER metal3 ;
      RECT 1232.805 981.190 1232.875 981.400 ;
    END
  END r0_rd_out[432]
  PIN r0_rd_out[433]
    DIRECTION OUTPUT ;
    USE SIGNAL ;
    SHAPE ABUTMENT ;
    PORT
      LAYER metal3 ;
      RECT 1239.805 981.190 1239.875 981.400 ;
    END
  END r0_rd_out[433]
  PIN r0_rd_out[434]
    DIRECTION OUTPUT ;
    USE SIGNAL ;
    SHAPE ABUTMENT ;
    PORT
      LAYER metal3 ;
      RECT 1246.805 981.190 1246.875 981.400 ;
    END
  END r0_rd_out[434]
  PIN r0_rd_out[435]
    DIRECTION OUTPUT ;
    USE SIGNAL ;
    SHAPE ABUTMENT ;
    PORT
      LAYER metal3 ;
      RECT 1253.805 981.190 1253.875 981.400 ;
    END
  END r0_rd_out[435]
  PIN r0_rd_out[436]
    DIRECTION OUTPUT ;
    USE SIGNAL ;
    SHAPE ABUTMENT ;
    PORT
      LAYER metal3 ;
      RECT 1260.805 981.190 1260.875 981.400 ;
    END
  END r0_rd_out[436]
  PIN r0_rd_out[437]
    DIRECTION OUTPUT ;
    USE SIGNAL ;
    SHAPE ABUTMENT ;
    PORT
      LAYER metal3 ;
      RECT 1267.805 981.190 1267.875 981.400 ;
    END
  END r0_rd_out[437]
  PIN r0_rd_out[438]
    DIRECTION OUTPUT ;
    USE SIGNAL ;
    SHAPE ABUTMENT ;
    PORT
      LAYER metal3 ;
      RECT 1274.805 981.190 1274.875 981.400 ;
    END
  END r0_rd_out[438]
  PIN r0_rd_out[439]
    DIRECTION OUTPUT ;
    USE SIGNAL ;
    SHAPE ABUTMENT ;
    PORT
      LAYER metal3 ;
      RECT 1281.805 981.190 1281.875 981.400 ;
    END
  END r0_rd_out[439]
  PIN r0_rd_out[440]
    DIRECTION OUTPUT ;
    USE SIGNAL ;
    SHAPE ABUTMENT ;
    PORT
      LAYER metal3 ;
      RECT 1288.805 981.190 1288.875 981.400 ;
    END
  END r0_rd_out[440]
  PIN r0_rd_out[441]
    DIRECTION OUTPUT ;
    USE SIGNAL ;
    SHAPE ABUTMENT ;
    PORT
      LAYER metal3 ;
      RECT 1295.805 981.190 1295.875 981.400 ;
    END
  END r0_rd_out[441]
  PIN r0_rd_out[442]
    DIRECTION OUTPUT ;
    USE SIGNAL ;
    SHAPE ABUTMENT ;
    PORT
      LAYER metal3 ;
      RECT 1302.805 981.190 1302.875 981.400 ;
    END
  END r0_rd_out[442]
  PIN r0_rd_out[443]
    DIRECTION OUTPUT ;
    USE SIGNAL ;
    SHAPE ABUTMENT ;
    PORT
      LAYER metal3 ;
      RECT 1309.805 981.190 1309.875 981.400 ;
    END
  END r0_rd_out[443]
  PIN r0_rd_out[444]
    DIRECTION OUTPUT ;
    USE SIGNAL ;
    SHAPE ABUTMENT ;
    PORT
      LAYER metal3 ;
      RECT 1316.805 981.190 1316.875 981.400 ;
    END
  END r0_rd_out[444]
  PIN r0_rd_out[445]
    DIRECTION OUTPUT ;
    USE SIGNAL ;
    SHAPE ABUTMENT ;
    PORT
      LAYER metal3 ;
      RECT 1323.805 981.190 1323.875 981.400 ;
    END
  END r0_rd_out[445]
  PIN r0_rd_out[446]
    DIRECTION OUTPUT ;
    USE SIGNAL ;
    SHAPE ABUTMENT ;
    PORT
      LAYER metal3 ;
      RECT 1330.805 981.190 1330.875 981.400 ;
    END
  END r0_rd_out[446]
  PIN r0_rd_out[447]
    DIRECTION OUTPUT ;
    USE SIGNAL ;
    SHAPE ABUTMENT ;
    PORT
      LAYER metal3 ;
      RECT 1337.805 981.190 1337.875 981.400 ;
    END
  END r0_rd_out[447]
  PIN r0_rd_out[448]
    DIRECTION OUTPUT ;
    USE SIGNAL ;
    SHAPE ABUTMENT ;
    PORT
      LAYER metal3 ;
      RECT 1344.805 981.190 1344.875 981.400 ;
    END
  END r0_rd_out[448]
  PIN r0_rd_out[449]
    DIRECTION OUTPUT ;
    USE SIGNAL ;
    SHAPE ABUTMENT ;
    PORT
      LAYER metal3 ;
      RECT 1351.805 981.190 1351.875 981.400 ;
    END
  END r0_rd_out[449]
  PIN r0_rd_out[450]
    DIRECTION OUTPUT ;
    USE SIGNAL ;
    SHAPE ABUTMENT ;
    PORT
      LAYER metal3 ;
      RECT 1358.805 981.190 1358.875 981.400 ;
    END
  END r0_rd_out[450]
  PIN r0_rd_out[451]
    DIRECTION OUTPUT ;
    USE SIGNAL ;
    SHAPE ABUTMENT ;
    PORT
      LAYER metal3 ;
      RECT 1365.805 981.190 1365.875 981.400 ;
    END
  END r0_rd_out[451]
  PIN r0_rd_out[452]
    DIRECTION OUTPUT ;
    USE SIGNAL ;
    SHAPE ABUTMENT ;
    PORT
      LAYER metal3 ;
      RECT 1372.805 981.190 1372.875 981.400 ;
    END
  END r0_rd_out[452]
  PIN r0_rd_out[453]
    DIRECTION OUTPUT ;
    USE SIGNAL ;
    SHAPE ABUTMENT ;
    PORT
      LAYER metal3 ;
      RECT 1379.805 981.190 1379.875 981.400 ;
    END
  END r0_rd_out[453]
  PIN r0_rd_out[454]
    DIRECTION OUTPUT ;
    USE SIGNAL ;
    SHAPE ABUTMENT ;
    PORT
      LAYER metal3 ;
      RECT 1386.805 981.190 1386.875 981.400 ;
    END
  END r0_rd_out[454]
  PIN r0_rd_out[455]
    DIRECTION OUTPUT ;
    USE SIGNAL ;
    SHAPE ABUTMENT ;
    PORT
      LAYER metal3 ;
      RECT 1393.805 981.190 1393.875 981.400 ;
    END
  END r0_rd_out[455]
  PIN r0_rd_out[456]
    DIRECTION OUTPUT ;
    USE SIGNAL ;
    SHAPE ABUTMENT ;
    PORT
      LAYER metal3 ;
      RECT 1400.805 981.190 1400.875 981.400 ;
    END
  END r0_rd_out[456]
  PIN r0_rd_out[457]
    DIRECTION OUTPUT ;
    USE SIGNAL ;
    SHAPE ABUTMENT ;
    PORT
      LAYER metal3 ;
      RECT 1407.805 981.190 1407.875 981.400 ;
    END
  END r0_rd_out[457]
  PIN r0_rd_out[458]
    DIRECTION OUTPUT ;
    USE SIGNAL ;
    SHAPE ABUTMENT ;
    PORT
      LAYER metal3 ;
      RECT 1414.805 981.190 1414.875 981.400 ;
    END
  END r0_rd_out[458]
  PIN r0_rd_out[459]
    DIRECTION OUTPUT ;
    USE SIGNAL ;
    SHAPE ABUTMENT ;
    PORT
      LAYER metal3 ;
      RECT 1421.805 981.190 1421.875 981.400 ;
    END
  END r0_rd_out[459]
  PIN r0_rd_out[460]
    DIRECTION OUTPUT ;
    USE SIGNAL ;
    SHAPE ABUTMENT ;
    PORT
      LAYER metal3 ;
      RECT 1428.805 981.190 1428.875 981.400 ;
    END
  END r0_rd_out[460]
  PIN r0_rd_out[461]
    DIRECTION OUTPUT ;
    USE SIGNAL ;
    SHAPE ABUTMENT ;
    PORT
      LAYER metal3 ;
      RECT 1435.805 981.190 1435.875 981.400 ;
    END
  END r0_rd_out[461]
  PIN r0_rd_out[462]
    DIRECTION OUTPUT ;
    USE SIGNAL ;
    SHAPE ABUTMENT ;
    PORT
      LAYER metal3 ;
      RECT 1442.805 981.190 1442.875 981.400 ;
    END
  END r0_rd_out[462]
  PIN r0_rd_out[463]
    DIRECTION OUTPUT ;
    USE SIGNAL ;
    SHAPE ABUTMENT ;
    PORT
      LAYER metal3 ;
      RECT 1449.805 981.190 1449.875 981.400 ;
    END
  END r0_rd_out[463]
  PIN r0_rd_out[464]
    DIRECTION OUTPUT ;
    USE SIGNAL ;
    SHAPE ABUTMENT ;
    PORT
      LAYER metal3 ;
      RECT 1456.805 981.190 1456.875 981.400 ;
    END
  END r0_rd_out[464]
  PIN r0_rd_out[465]
    DIRECTION OUTPUT ;
    USE SIGNAL ;
    SHAPE ABUTMENT ;
    PORT
      LAYER metal3 ;
      RECT 1463.805 981.190 1463.875 981.400 ;
    END
  END r0_rd_out[465]
  PIN r0_rd_out[466]
    DIRECTION OUTPUT ;
    USE SIGNAL ;
    SHAPE ABUTMENT ;
    PORT
      LAYER metal3 ;
      RECT 1470.805 981.190 1470.875 981.400 ;
    END
  END r0_rd_out[466]
  PIN r0_rd_out[467]
    DIRECTION OUTPUT ;
    USE SIGNAL ;
    SHAPE ABUTMENT ;
    PORT
      LAYER metal3 ;
      RECT 1477.805 981.190 1477.875 981.400 ;
    END
  END r0_rd_out[467]
  PIN r0_rd_out[468]
    DIRECTION OUTPUT ;
    USE SIGNAL ;
    SHAPE ABUTMENT ;
    PORT
      LAYER metal3 ;
      RECT 1484.805 981.190 1484.875 981.400 ;
    END
  END r0_rd_out[468]
  PIN r0_rd_out[469]
    DIRECTION OUTPUT ;
    USE SIGNAL ;
    SHAPE ABUTMENT ;
    PORT
      LAYER metal3 ;
      RECT 1491.805 981.190 1491.875 981.400 ;
    END
  END r0_rd_out[469]
  PIN r0_rd_out[470]
    DIRECTION OUTPUT ;
    USE SIGNAL ;
    SHAPE ABUTMENT ;
    PORT
      LAYER metal3 ;
      RECT 1498.805 981.190 1498.875 981.400 ;
    END
  END r0_rd_out[470]
  PIN r0_rd_out[471]
    DIRECTION OUTPUT ;
    USE SIGNAL ;
    SHAPE ABUTMENT ;
    PORT
      LAYER metal3 ;
      RECT 1505.805 981.190 1505.875 981.400 ;
    END
  END r0_rd_out[471]
  PIN r0_rd_out[472]
    DIRECTION OUTPUT ;
    USE SIGNAL ;
    SHAPE ABUTMENT ;
    PORT
      LAYER metal3 ;
      RECT 1512.805 981.190 1512.875 981.400 ;
    END
  END r0_rd_out[472]
  PIN r0_rd_out[473]
    DIRECTION OUTPUT ;
    USE SIGNAL ;
    SHAPE ABUTMENT ;
    PORT
      LAYER metal3 ;
      RECT 1519.805 981.190 1519.875 981.400 ;
    END
  END r0_rd_out[473]
  PIN r0_rd_out[474]
    DIRECTION OUTPUT ;
    USE SIGNAL ;
    SHAPE ABUTMENT ;
    PORT
      LAYER metal3 ;
      RECT 1526.805 981.190 1526.875 981.400 ;
    END
  END r0_rd_out[474]
  PIN r0_rd_out[475]
    DIRECTION OUTPUT ;
    USE SIGNAL ;
    SHAPE ABUTMENT ;
    PORT
      LAYER metal3 ;
      RECT 1533.805 981.190 1533.875 981.400 ;
    END
  END r0_rd_out[475]
  PIN r0_rd_out[476]
    DIRECTION OUTPUT ;
    USE SIGNAL ;
    SHAPE ABUTMENT ;
    PORT
      LAYER metal3 ;
      RECT 1540.805 981.190 1540.875 981.400 ;
    END
  END r0_rd_out[476]
  PIN r0_rd_out[477]
    DIRECTION OUTPUT ;
    USE SIGNAL ;
    SHAPE ABUTMENT ;
    PORT
      LAYER metal3 ;
      RECT 1547.805 981.190 1547.875 981.400 ;
    END
  END r0_rd_out[477]
  PIN r0_rd_out[478]
    DIRECTION OUTPUT ;
    USE SIGNAL ;
    SHAPE ABUTMENT ;
    PORT
      LAYER metal3 ;
      RECT 1554.805 981.190 1554.875 981.400 ;
    END
  END r0_rd_out[478]
  PIN r0_rd_out[479]
    DIRECTION OUTPUT ;
    USE SIGNAL ;
    SHAPE ABUTMENT ;
    PORT
      LAYER metal3 ;
      RECT 1561.805 981.190 1561.875 981.400 ;
    END
  END r0_rd_out[479]
  PIN r0_rd_out[480]
    DIRECTION OUTPUT ;
    USE SIGNAL ;
    SHAPE ABUTMENT ;
    PORT
      LAYER metal3 ;
      RECT 1568.805 981.190 1568.875 981.400 ;
    END
  END r0_rd_out[480]
  PIN r0_rd_out[481]
    DIRECTION OUTPUT ;
    USE SIGNAL ;
    SHAPE ABUTMENT ;
    PORT
      LAYER metal3 ;
      RECT 1575.805 981.190 1575.875 981.400 ;
    END
  END r0_rd_out[481]
  PIN r0_rd_out[482]
    DIRECTION OUTPUT ;
    USE SIGNAL ;
    SHAPE ABUTMENT ;
    PORT
      LAYER metal3 ;
      RECT 1582.805 981.190 1582.875 981.400 ;
    END
  END r0_rd_out[482]
  PIN r0_rd_out[483]
    DIRECTION OUTPUT ;
    USE SIGNAL ;
    SHAPE ABUTMENT ;
    PORT
      LAYER metal3 ;
      RECT 1589.805 981.190 1589.875 981.400 ;
    END
  END r0_rd_out[483]
  PIN r0_rd_out[484]
    DIRECTION OUTPUT ;
    USE SIGNAL ;
    SHAPE ABUTMENT ;
    PORT
      LAYER metal3 ;
      RECT 1596.805 981.190 1596.875 981.400 ;
    END
  END r0_rd_out[484]
  PIN r0_rd_out[485]
    DIRECTION OUTPUT ;
    USE SIGNAL ;
    SHAPE ABUTMENT ;
    PORT
      LAYER metal3 ;
      RECT 1603.805 981.190 1603.875 981.400 ;
    END
  END r0_rd_out[485]
  PIN r0_rd_out[486]
    DIRECTION OUTPUT ;
    USE SIGNAL ;
    SHAPE ABUTMENT ;
    PORT
      LAYER metal3 ;
      RECT 1610.805 981.190 1610.875 981.400 ;
    END
  END r0_rd_out[486]
  PIN r0_rd_out[487]
    DIRECTION OUTPUT ;
    USE SIGNAL ;
    SHAPE ABUTMENT ;
    PORT
      LAYER metal3 ;
      RECT 1617.805 981.190 1617.875 981.400 ;
    END
  END r0_rd_out[487]
  PIN r0_rd_out[488]
    DIRECTION OUTPUT ;
    USE SIGNAL ;
    SHAPE ABUTMENT ;
    PORT
      LAYER metal3 ;
      RECT 1624.805 981.190 1624.875 981.400 ;
    END
  END r0_rd_out[488]
  PIN r0_rd_out[489]
    DIRECTION OUTPUT ;
    USE SIGNAL ;
    SHAPE ABUTMENT ;
    PORT
      LAYER metal3 ;
      RECT 1631.805 981.190 1631.875 981.400 ;
    END
  END r0_rd_out[489]
  PIN r0_rd_out[490]
    DIRECTION OUTPUT ;
    USE SIGNAL ;
    SHAPE ABUTMENT ;
    PORT
      LAYER metal3 ;
      RECT 1638.805 981.190 1638.875 981.400 ;
    END
  END r0_rd_out[490]
  PIN r0_rd_out[491]
    DIRECTION OUTPUT ;
    USE SIGNAL ;
    SHAPE ABUTMENT ;
    PORT
      LAYER metal3 ;
      RECT 1645.805 981.190 1645.875 981.400 ;
    END
  END r0_rd_out[491]
  PIN r0_rd_out[492]
    DIRECTION OUTPUT ;
    USE SIGNAL ;
    SHAPE ABUTMENT ;
    PORT
      LAYER metal3 ;
      RECT 1652.805 981.190 1652.875 981.400 ;
    END
  END r0_rd_out[492]
  PIN r0_rd_out[493]
    DIRECTION OUTPUT ;
    USE SIGNAL ;
    SHAPE ABUTMENT ;
    PORT
      LAYER metal3 ;
      RECT 1659.805 981.190 1659.875 981.400 ;
    END
  END r0_rd_out[493]
  PIN r0_rd_out[494]
    DIRECTION OUTPUT ;
    USE SIGNAL ;
    SHAPE ABUTMENT ;
    PORT
      LAYER metal3 ;
      RECT 1666.805 981.190 1666.875 981.400 ;
    END
  END r0_rd_out[494]
  PIN r0_rd_out[495]
    DIRECTION OUTPUT ;
    USE SIGNAL ;
    SHAPE ABUTMENT ;
    PORT
      LAYER metal3 ;
      RECT 1673.805 981.190 1673.875 981.400 ;
    END
  END r0_rd_out[495]
  PIN r0_rd_out[496]
    DIRECTION OUTPUT ;
    USE SIGNAL ;
    SHAPE ABUTMENT ;
    PORT
      LAYER metal3 ;
      RECT 1680.805 981.190 1680.875 981.400 ;
    END
  END r0_rd_out[496]
  PIN r0_rd_out[497]
    DIRECTION OUTPUT ;
    USE SIGNAL ;
    SHAPE ABUTMENT ;
    PORT
      LAYER metal3 ;
      RECT 1687.805 981.190 1687.875 981.400 ;
    END
  END r0_rd_out[497]
  PIN r0_rd_out[498]
    DIRECTION OUTPUT ;
    USE SIGNAL ;
    SHAPE ABUTMENT ;
    PORT
      LAYER metal3 ;
      RECT 1694.805 981.190 1694.875 981.400 ;
    END
  END r0_rd_out[498]
  PIN r0_rd_out[499]
    DIRECTION OUTPUT ;
    USE SIGNAL ;
    SHAPE ABUTMENT ;
    PORT
      LAYER metal3 ;
      RECT 1701.805 981.190 1701.875 981.400 ;
    END
  END r0_rd_out[499]
  PIN r0_rd_out[500]
    DIRECTION OUTPUT ;
    USE SIGNAL ;
    SHAPE ABUTMENT ;
    PORT
      LAYER metal3 ;
      RECT 1708.805 981.190 1708.875 981.400 ;
    END
  END r0_rd_out[500]
  PIN r0_rd_out[501]
    DIRECTION OUTPUT ;
    USE SIGNAL ;
    SHAPE ABUTMENT ;
    PORT
      LAYER metal3 ;
      RECT 1715.805 981.190 1715.875 981.400 ;
    END
  END r0_rd_out[501]
  PIN r0_rd_out[502]
    DIRECTION OUTPUT ;
    USE SIGNAL ;
    SHAPE ABUTMENT ;
    PORT
      LAYER metal3 ;
      RECT 1722.805 981.190 1722.875 981.400 ;
    END
  END r0_rd_out[502]
  PIN r0_rd_out[503]
    DIRECTION OUTPUT ;
    USE SIGNAL ;
    SHAPE ABUTMENT ;
    PORT
      LAYER metal3 ;
      RECT 1729.805 981.190 1729.875 981.400 ;
    END
  END r0_rd_out[503]
  PIN r0_rd_out[504]
    DIRECTION OUTPUT ;
    USE SIGNAL ;
    SHAPE ABUTMENT ;
    PORT
      LAYER metal3 ;
      RECT 1736.805 981.190 1736.875 981.400 ;
    END
  END r0_rd_out[504]
  PIN r0_rd_out[505]
    DIRECTION OUTPUT ;
    USE SIGNAL ;
    SHAPE ABUTMENT ;
    PORT
      LAYER metal3 ;
      RECT 1743.805 981.190 1743.875 981.400 ;
    END
  END r0_rd_out[505]
  PIN r0_rd_out[506]
    DIRECTION OUTPUT ;
    USE SIGNAL ;
    SHAPE ABUTMENT ;
    PORT
      LAYER metal3 ;
      RECT 1750.805 981.190 1750.875 981.400 ;
    END
  END r0_rd_out[506]
  PIN r0_rd_out[507]
    DIRECTION OUTPUT ;
    USE SIGNAL ;
    SHAPE ABUTMENT ;
    PORT
      LAYER metal3 ;
      RECT 1757.805 981.190 1757.875 981.400 ;
    END
  END r0_rd_out[507]
  PIN r0_rd_out[508]
    DIRECTION OUTPUT ;
    USE SIGNAL ;
    SHAPE ABUTMENT ;
    PORT
      LAYER metal3 ;
      RECT 1764.805 981.190 1764.875 981.400 ;
    END
  END r0_rd_out[508]
  PIN r0_rd_out[509]
    DIRECTION OUTPUT ;
    USE SIGNAL ;
    SHAPE ABUTMENT ;
    PORT
      LAYER metal3 ;
      RECT 1771.805 981.190 1771.875 981.400 ;
    END
  END r0_rd_out[509]
  PIN r0_rd_out[510]
    DIRECTION OUTPUT ;
    USE SIGNAL ;
    SHAPE ABUTMENT ;
    PORT
      LAYER metal3 ;
      RECT 1778.805 981.190 1778.875 981.400 ;
    END
  END r0_rd_out[510]
  PIN r0_rd_out[511]
    DIRECTION OUTPUT ;
    USE SIGNAL ;
    SHAPE ABUTMENT ;
    PORT
      LAYER metal3 ;
      RECT 1785.805 981.190 1785.875 981.400 ;
    END
  END r0_rd_out[511]
  PIN w0_addr_in[0]
    DIRECTION INPUT ;
    USE SIGNAL ;
    SHAPE ABUTMENT ;
    PORT
      LAYER metal4 ;
      RECT 0.000 897.645 0.210 897.715 ;
    END
  END w0_addr_in[0]
  PIN w0_addr_in[1]
    DIRECTION INPUT ;
    USE SIGNAL ;
    SHAPE ABUTMENT ;
    PORT
      LAYER metal4 ;
      RECT 0.000 904.645 0.210 904.715 ;
    END
  END w0_addr_in[1]
  PIN w0_addr_in[2]
    DIRECTION INPUT ;
    USE SIGNAL ;
    SHAPE ABUTMENT ;
    PORT
      LAYER metal4 ;
      RECT 0.000 911.645 0.210 911.715 ;
    END
  END w0_addr_in[2]
  PIN w0_addr_in[3]
    DIRECTION INPUT ;
    USE SIGNAL ;
    SHAPE ABUTMENT ;
    PORT
      LAYER metal4 ;
      RECT 0.000 918.645 0.210 918.715 ;
    END
  END w0_addr_in[3]
  PIN w0_addr_in[4]
    DIRECTION INPUT ;
    USE SIGNAL ;
    SHAPE ABUTMENT ;
    PORT
      LAYER metal4 ;
      RECT 0.000 925.645 0.210 925.715 ;
    END
  END w0_addr_in[4]
  PIN w0_addr_in[5]
    DIRECTION INPUT ;
    USE SIGNAL ;
    SHAPE ABUTMENT ;
    PORT
      LAYER metal4 ;
      RECT 1832.530 897.645 1832.740 897.715 ;
    END
  END w0_addr_in[5]
  PIN w0_addr_in[6]
    DIRECTION INPUT ;
    USE SIGNAL ;
    SHAPE ABUTMENT ;
    PORT
      LAYER metal4 ;
      RECT 1832.530 904.645 1832.740 904.715 ;
    END
  END w0_addr_in[6]
  PIN w0_addr_in[7]
    DIRECTION INPUT ;
    USE SIGNAL ;
    SHAPE ABUTMENT ;
    PORT
      LAYER metal4 ;
      RECT 1832.530 911.645 1832.740 911.715 ;
    END
  END w0_addr_in[7]
  PIN w0_addr_in[8]
    DIRECTION INPUT ;
    USE SIGNAL ;
    SHAPE ABUTMENT ;
    PORT
      LAYER metal4 ;
      RECT 1832.530 918.645 1832.740 918.715 ;
    END
  END w0_addr_in[8]
  PIN w0_addr_in[9]
    DIRECTION INPUT ;
    USE SIGNAL ;
    SHAPE ABUTMENT ;
    PORT
      LAYER metal4 ;
      RECT 1832.530 925.645 1832.740 925.715 ;
    END
  END w0_addr_in[9]
  PIN r0_addr_in[0]
    DIRECTION INPUT ;
    USE SIGNAL ;
    SHAPE ABUTMENT ;
    PORT
      LAYER metal4 ;
      RECT 0.000 932.645 0.210 932.715 ;
    END
  END r0_addr_in[0]
  PIN r0_addr_in[1]
    DIRECTION INPUT ;
    USE SIGNAL ;
    SHAPE ABUTMENT ;
    PORT
      LAYER metal4 ;
      RECT 0.000 939.645 0.210 939.715 ;
    END
  END r0_addr_in[1]
  PIN r0_addr_in[2]
    DIRECTION INPUT ;
    USE SIGNAL ;
    SHAPE ABUTMENT ;
    PORT
      LAYER metal4 ;
      RECT 0.000 946.645 0.210 946.715 ;
    END
  END r0_addr_in[2]
  PIN r0_addr_in[3]
    DIRECTION INPUT ;
    USE SIGNAL ;
    SHAPE ABUTMENT ;
    PORT
      LAYER metal4 ;
      RECT 0.000 953.645 0.210 953.715 ;
    END
  END r0_addr_in[3]
  PIN r0_addr_in[4]
    DIRECTION INPUT ;
    USE SIGNAL ;
    SHAPE ABUTMENT ;
    PORT
      LAYER metal4 ;
      RECT 0.000 960.645 0.210 960.715 ;
    END
  END r0_addr_in[4]
  PIN r0_addr_in[5]
    DIRECTION INPUT ;
    USE SIGNAL ;
    SHAPE ABUTMENT ;
    PORT
      LAYER metal4 ;
      RECT 1832.530 932.645 1832.740 932.715 ;
    END
  END r0_addr_in[5]
  PIN r0_addr_in[6]
    DIRECTION INPUT ;
    USE SIGNAL ;
    SHAPE ABUTMENT ;
    PORT
      LAYER metal4 ;
      RECT 1832.530 939.645 1832.740 939.715 ;
    END
  END r0_addr_in[6]
  PIN r0_addr_in[7]
    DIRECTION INPUT ;
    USE SIGNAL ;
    SHAPE ABUTMENT ;
    PORT
      LAYER metal4 ;
      RECT 1832.530 946.645 1832.740 946.715 ;
    END
  END r0_addr_in[7]
  PIN r0_addr_in[8]
    DIRECTION INPUT ;
    USE SIGNAL ;
    SHAPE ABUTMENT ;
    PORT
      LAYER metal4 ;
      RECT 1832.530 953.645 1832.740 953.715 ;
    END
  END r0_addr_in[8]
  PIN r0_addr_in[9]
    DIRECTION INPUT ;
    USE SIGNAL ;
    SHAPE ABUTMENT ;
    PORT
      LAYER metal4 ;
      RECT 1832.530 960.645 1832.740 960.715 ;
    END
  END r0_addr_in[9]
  PIN w0_we_in
    DIRECTION INPUT ;
    USE SIGNAL ;
    SHAPE ABUTMENT ;
    PORT
      LAYER metal3 ;
      RECT 1792.805 981.190 1792.875 981.400 ;
    END
  END w0_we_in
  PIN w0_ce_in
    DIRECTION INPUT ;
    USE SIGNAL ;
    SHAPE ABUTMENT ;
    PORT
      LAYER metal3 ;
      RECT 1799.805 981.190 1799.875 981.400 ;
    END
  END w0_ce_in
  PIN w0_clk
    DIRECTION INPUT ;
    USE SIGNAL ;
    SHAPE ABUTMENT ;
    PORT
      LAYER metal3 ;
      RECT 1806.805 981.190 1806.875 981.400 ;
    END
  END w0_clk
  PIN r0_ce_in
    DIRECTION INPUT ;
    USE SIGNAL ;
    SHAPE ABUTMENT ;
    PORT
      LAYER metal3 ;
      RECT 1813.805 981.190 1813.875 981.400 ;
    END
  END r0_ce_in
  PIN r0_clk
    DIRECTION INPUT ;
    USE SIGNAL ;
    SHAPE ABUTMENT ;
    PORT
      LAYER metal3 ;
      RECT 1820.805 981.190 1820.875 981.400 ;
    END
  END r0_clk
  PIN VSS
    DIRECTION INOUT ;
    USE GROUND ;
    PORT
      LAYER metal4 ;
      RECT 0.840 1.540 1831.900 1.820 ;
      RECT 0.840 6.020 1831.900 6.300 ;
      RECT 0.840 10.500 1831.900 10.780 ;
      RECT 0.840 14.980 1831.900 15.260 ;
      RECT 0.840 19.460 1831.900 19.740 ;
      RECT 0.840 23.940 1831.900 24.220 ;
      RECT 0.840 28.420 1831.900 28.700 ;
      RECT 0.840 32.900 1831.900 33.180 ;
      RECT 0.840 37.380 1831.900 37.660 ;
      RECT 0.840 41.860 1831.900 42.140 ;
      RECT 0.840 46.340 1831.900 46.620 ;
      RECT 0.840 50.820 1831.900 51.100 ;
      RECT 0.840 55.300 1831.900 55.580 ;
      RECT 0.840 59.780 1831.900 60.060 ;
      RECT 0.840 64.260 1831.900 64.540 ;
      RECT 0.840 68.740 1831.900 69.020 ;
      RECT 0.840 73.220 1831.900 73.500 ;
      RECT 0.840 77.700 1831.900 77.980 ;
      RECT 0.840 82.180 1831.900 82.460 ;
      RECT 0.840 86.660 1831.900 86.940 ;
      RECT 0.840 91.140 1831.900 91.420 ;
      RECT 0.840 95.620 1831.900 95.900 ;
      RECT 0.840 100.100 1831.900 100.380 ;
      RECT 0.840 104.580 1831.900 104.860 ;
      RECT 0.840 109.060 1831.900 109.340 ;
      RECT 0.840 113.540 1831.900 113.820 ;
      RECT 0.840 118.020 1831.900 118.300 ;
      RECT 0.840 122.500 1831.900 122.780 ;
      RECT 0.840 126.980 1831.900 127.260 ;
      RECT 0.840 131.460 1831.900 131.740 ;
      RECT 0.840 135.940 1831.900 136.220 ;
      RECT 0.840 140.420 1831.900 140.700 ;
      RECT 0.840 144.900 1831.900 145.180 ;
      RECT 0.840 149.380 1831.900 149.660 ;
      RECT 0.840 153.860 1831.900 154.140 ;
      RECT 0.840 158.340 1831.900 158.620 ;
      RECT 0.840 162.820 1831.900 163.100 ;
      RECT 0.840 167.300 1831.900 167.580 ;
      RECT 0.840 171.780 1831.900 172.060 ;
      RECT 0.840 176.260 1831.900 176.540 ;
      RECT 0.840 180.740 1831.900 181.020 ;
      RECT 0.840 185.220 1831.900 185.500 ;
      RECT 0.840 189.700 1831.900 189.980 ;
      RECT 0.840 194.180 1831.900 194.460 ;
      RECT 0.840 198.660 1831.900 198.940 ;
      RECT 0.840 203.140 1831.900 203.420 ;
      RECT 0.840 207.620 1831.900 207.900 ;
      RECT 0.840 212.100 1831.900 212.380 ;
      RECT 0.840 216.580 1831.900 216.860 ;
      RECT 0.840 221.060 1831.900 221.340 ;
      RECT 0.840 225.540 1831.900 225.820 ;
      RECT 0.840 230.020 1831.900 230.300 ;
      RECT 0.840 234.500 1831.900 234.780 ;
      RECT 0.840 238.980 1831.900 239.260 ;
      RECT 0.840 243.460 1831.900 243.740 ;
      RECT 0.840 247.940 1831.900 248.220 ;
      RECT 0.840 252.420 1831.900 252.700 ;
      RECT 0.840 256.900 1831.900 257.180 ;
      RECT 0.840 261.380 1831.900 261.660 ;
      RECT 0.840 265.860 1831.900 266.140 ;
      RECT 0.840 270.340 1831.900 270.620 ;
      RECT 0.840 274.820 1831.900 275.100 ;
      RECT 0.840 279.300 1831.900 279.580 ;
      RECT 0.840 283.780 1831.900 284.060 ;
      RECT 0.840 288.260 1831.900 288.540 ;
      RECT 0.840 292.740 1831.900 293.020 ;
      RECT 0.840 297.220 1831.900 297.500 ;
      RECT 0.840 301.700 1831.900 301.980 ;
      RECT 0.840 306.180 1831.900 306.460 ;
      RECT 0.840 310.660 1831.900 310.940 ;
      RECT 0.840 315.140 1831.900 315.420 ;
      RECT 0.840 319.620 1831.900 319.900 ;
      RECT 0.840 324.100 1831.900 324.380 ;
      RECT 0.840 328.580 1831.900 328.860 ;
      RECT 0.840 333.060 1831.900 333.340 ;
      RECT 0.840 337.540 1831.900 337.820 ;
      RECT 0.840 342.020 1831.900 342.300 ;
      RECT 0.840 346.500 1831.900 346.780 ;
      RECT 0.840 350.980 1831.900 351.260 ;
      RECT 0.840 355.460 1831.900 355.740 ;
      RECT 0.840 359.940 1831.900 360.220 ;
      RECT 0.840 364.420 1831.900 364.700 ;
      RECT 0.840 368.900 1831.900 369.180 ;
      RECT 0.840 373.380 1831.900 373.660 ;
      RECT 0.840 377.860 1831.900 378.140 ;
      RECT 0.840 382.340 1831.900 382.620 ;
      RECT 0.840 386.820 1831.900 387.100 ;
      RECT 0.840 391.300 1831.900 391.580 ;
      RECT 0.840 395.780 1831.900 396.060 ;
      RECT 0.840 400.260 1831.900 400.540 ;
      RECT 0.840 404.740 1831.900 405.020 ;
      RECT 0.840 409.220 1831.900 409.500 ;
      RECT 0.840 413.700 1831.900 413.980 ;
      RECT 0.840 418.180 1831.900 418.460 ;
      RECT 0.840 422.660 1831.900 422.940 ;
      RECT 0.840 427.140 1831.900 427.420 ;
      RECT 0.840 431.620 1831.900 431.900 ;
      RECT 0.840 436.100 1831.900 436.380 ;
      RECT 0.840 440.580 1831.900 440.860 ;
      RECT 0.840 445.060 1831.900 445.340 ;
      RECT 0.840 449.540 1831.900 449.820 ;
      RECT 0.840 454.020 1831.900 454.300 ;
      RECT 0.840 458.500 1831.900 458.780 ;
      RECT 0.840 462.980 1831.900 463.260 ;
      RECT 0.840 467.460 1831.900 467.740 ;
      RECT 0.840 471.940 1831.900 472.220 ;
      RECT 0.840 476.420 1831.900 476.700 ;
      RECT 0.840 480.900 1831.900 481.180 ;
      RECT 0.840 485.380 1831.900 485.660 ;
      RECT 0.840 489.860 1831.900 490.140 ;
      RECT 0.840 494.340 1831.900 494.620 ;
      RECT 0.840 498.820 1831.900 499.100 ;
      RECT 0.840 503.300 1831.900 503.580 ;
      RECT 0.840 507.780 1831.900 508.060 ;
      RECT 0.840 512.260 1831.900 512.540 ;
      RECT 0.840 516.740 1831.900 517.020 ;
      RECT 0.840 521.220 1831.900 521.500 ;
      RECT 0.840 525.700 1831.900 525.980 ;
      RECT 0.840 530.180 1831.900 530.460 ;
      RECT 0.840 534.660 1831.900 534.940 ;
      RECT 0.840 539.140 1831.900 539.420 ;
      RECT 0.840 543.620 1831.900 543.900 ;
      RECT 0.840 548.100 1831.900 548.380 ;
      RECT 0.840 552.580 1831.900 552.860 ;
      RECT 0.840 557.060 1831.900 557.340 ;
      RECT 0.840 561.540 1831.900 561.820 ;
      RECT 0.840 566.020 1831.900 566.300 ;
      RECT 0.840 570.500 1831.900 570.780 ;
      RECT 0.840 574.980 1831.900 575.260 ;
      RECT 0.840 579.460 1831.900 579.740 ;
      RECT 0.840 583.940 1831.900 584.220 ;
      RECT 0.840 588.420 1831.900 588.700 ;
      RECT 0.840 592.900 1831.900 593.180 ;
      RECT 0.840 597.380 1831.900 597.660 ;
      RECT 0.840 601.860 1831.900 602.140 ;
      RECT 0.840 606.340 1831.900 606.620 ;
      RECT 0.840 610.820 1831.900 611.100 ;
      RECT 0.840 615.300 1831.900 615.580 ;
      RECT 0.840 619.780 1831.900 620.060 ;
      RECT 0.840 624.260 1831.900 624.540 ;
      RECT 0.840 628.740 1831.900 629.020 ;
      RECT 0.840 633.220 1831.900 633.500 ;
      RECT 0.840 637.700 1831.900 637.980 ;
      RECT 0.840 642.180 1831.900 642.460 ;
      RECT 0.840 646.660 1831.900 646.940 ;
      RECT 0.840 651.140 1831.900 651.420 ;
      RECT 0.840 655.620 1831.900 655.900 ;
      RECT 0.840 660.100 1831.900 660.380 ;
      RECT 0.840 664.580 1831.900 664.860 ;
      RECT 0.840 669.060 1831.900 669.340 ;
      RECT 0.840 673.540 1831.900 673.820 ;
      RECT 0.840 678.020 1831.900 678.300 ;
      RECT 0.840 682.500 1831.900 682.780 ;
      RECT 0.840 686.980 1831.900 687.260 ;
      RECT 0.840 691.460 1831.900 691.740 ;
      RECT 0.840 695.940 1831.900 696.220 ;
      RECT 0.840 700.420 1831.900 700.700 ;
      RECT 0.840 704.900 1831.900 705.180 ;
      RECT 0.840 709.380 1831.900 709.660 ;
      RECT 0.840 713.860 1831.900 714.140 ;
      RECT 0.840 718.340 1831.900 718.620 ;
      RECT 0.840 722.820 1831.900 723.100 ;
      RECT 0.840 727.300 1831.900 727.580 ;
      RECT 0.840 731.780 1831.900 732.060 ;
      RECT 0.840 736.260 1831.900 736.540 ;
      RECT 0.840 740.740 1831.900 741.020 ;
      RECT 0.840 745.220 1831.900 745.500 ;
      RECT 0.840 749.700 1831.900 749.980 ;
      RECT 0.840 754.180 1831.900 754.460 ;
      RECT 0.840 758.660 1831.900 758.940 ;
      RECT 0.840 763.140 1831.900 763.420 ;
      RECT 0.840 767.620 1831.900 767.900 ;
      RECT 0.840 772.100 1831.900 772.380 ;
      RECT 0.840 776.580 1831.900 776.860 ;
      RECT 0.840 781.060 1831.900 781.340 ;
      RECT 0.840 785.540 1831.900 785.820 ;
      RECT 0.840 790.020 1831.900 790.300 ;
      RECT 0.840 794.500 1831.900 794.780 ;
      RECT 0.840 798.980 1831.900 799.260 ;
      RECT 0.840 803.460 1831.900 803.740 ;
      RECT 0.840 807.940 1831.900 808.220 ;
      RECT 0.840 812.420 1831.900 812.700 ;
      RECT 0.840 816.900 1831.900 817.180 ;
      RECT 0.840 821.380 1831.900 821.660 ;
      RECT 0.840 825.860 1831.900 826.140 ;
      RECT 0.840 830.340 1831.900 830.620 ;
      RECT 0.840 834.820 1831.900 835.100 ;
      RECT 0.840 839.300 1831.900 839.580 ;
      RECT 0.840 843.780 1831.900 844.060 ;
      RECT 0.840 848.260 1831.900 848.540 ;
      RECT 0.840 852.740 1831.900 853.020 ;
      RECT 0.840 857.220 1831.900 857.500 ;
      RECT 0.840 861.700 1831.900 861.980 ;
      RECT 0.840 866.180 1831.900 866.460 ;
      RECT 0.840 870.660 1831.900 870.940 ;
      RECT 0.840 875.140 1831.900 875.420 ;
      RECT 0.840 879.620 1831.900 879.900 ;
      RECT 0.840 884.100 1831.900 884.380 ;
      RECT 0.840 888.580 1831.900 888.860 ;
      RECT 0.840 893.060 1831.900 893.340 ;
      RECT 0.840 897.540 1831.900 897.820 ;
      RECT 0.840 902.020 1831.900 902.300 ;
      RECT 0.840 906.500 1831.900 906.780 ;
      RECT 0.840 910.980 1831.900 911.260 ;
      RECT 0.840 915.460 1831.900 915.740 ;
      RECT 0.840 919.940 1831.900 920.220 ;
      RECT 0.840 924.420 1831.900 924.700 ;
      RECT 0.840 928.900 1831.900 929.180 ;
      RECT 0.840 933.380 1831.900 933.660 ;
      RECT 0.840 937.860 1831.900 938.140 ;
      RECT 0.840 942.340 1831.900 942.620 ;
      RECT 0.840 946.820 1831.900 947.100 ;
      RECT 0.840 951.300 1831.900 951.580 ;
      RECT 0.840 955.780 1831.900 956.060 ;
      RECT 0.840 960.260 1831.900 960.540 ;
      RECT 0.840 964.740 1831.900 965.020 ;
      RECT 0.840 969.220 1831.900 969.500 ;
      RECT 0.840 973.700 1831.900 973.980 ;
      RECT 0.840 978.180 1831.900 978.460 ;
    END
  END VSS
  PIN VDD
    DIRECTION INOUT ;
    USE POWER ;
    PORT
      LAYER metal4 ;
      RECT 0.840 1.540 1831.900 1.820 ;
      RECT 0.840 6.020 1831.900 6.300 ;
      RECT 0.840 10.500 1831.900 10.780 ;
      RECT 0.840 14.980 1831.900 15.260 ;
      RECT 0.840 19.460 1831.900 19.740 ;
      RECT 0.840 23.940 1831.900 24.220 ;
      RECT 0.840 28.420 1831.900 28.700 ;
      RECT 0.840 32.900 1831.900 33.180 ;
      RECT 0.840 37.380 1831.900 37.660 ;
      RECT 0.840 41.860 1831.900 42.140 ;
      RECT 0.840 46.340 1831.900 46.620 ;
      RECT 0.840 50.820 1831.900 51.100 ;
      RECT 0.840 55.300 1831.900 55.580 ;
      RECT 0.840 59.780 1831.900 60.060 ;
      RECT 0.840 64.260 1831.900 64.540 ;
      RECT 0.840 68.740 1831.900 69.020 ;
      RECT 0.840 73.220 1831.900 73.500 ;
      RECT 0.840 77.700 1831.900 77.980 ;
      RECT 0.840 82.180 1831.900 82.460 ;
      RECT 0.840 86.660 1831.900 86.940 ;
      RECT 0.840 91.140 1831.900 91.420 ;
      RECT 0.840 95.620 1831.900 95.900 ;
      RECT 0.840 100.100 1831.900 100.380 ;
      RECT 0.840 104.580 1831.900 104.860 ;
      RECT 0.840 109.060 1831.900 109.340 ;
      RECT 0.840 113.540 1831.900 113.820 ;
      RECT 0.840 118.020 1831.900 118.300 ;
      RECT 0.840 122.500 1831.900 122.780 ;
      RECT 0.840 126.980 1831.900 127.260 ;
      RECT 0.840 131.460 1831.900 131.740 ;
      RECT 0.840 135.940 1831.900 136.220 ;
      RECT 0.840 140.420 1831.900 140.700 ;
      RECT 0.840 144.900 1831.900 145.180 ;
      RECT 0.840 149.380 1831.900 149.660 ;
      RECT 0.840 153.860 1831.900 154.140 ;
      RECT 0.840 158.340 1831.900 158.620 ;
      RECT 0.840 162.820 1831.900 163.100 ;
      RECT 0.840 167.300 1831.900 167.580 ;
      RECT 0.840 171.780 1831.900 172.060 ;
      RECT 0.840 176.260 1831.900 176.540 ;
      RECT 0.840 180.740 1831.900 181.020 ;
      RECT 0.840 185.220 1831.900 185.500 ;
      RECT 0.840 189.700 1831.900 189.980 ;
      RECT 0.840 194.180 1831.900 194.460 ;
      RECT 0.840 198.660 1831.900 198.940 ;
      RECT 0.840 203.140 1831.900 203.420 ;
      RECT 0.840 207.620 1831.900 207.900 ;
      RECT 0.840 212.100 1831.900 212.380 ;
      RECT 0.840 216.580 1831.900 216.860 ;
      RECT 0.840 221.060 1831.900 221.340 ;
      RECT 0.840 225.540 1831.900 225.820 ;
      RECT 0.840 230.020 1831.900 230.300 ;
      RECT 0.840 234.500 1831.900 234.780 ;
      RECT 0.840 238.980 1831.900 239.260 ;
      RECT 0.840 243.460 1831.900 243.740 ;
      RECT 0.840 247.940 1831.900 248.220 ;
      RECT 0.840 252.420 1831.900 252.700 ;
      RECT 0.840 256.900 1831.900 257.180 ;
      RECT 0.840 261.380 1831.900 261.660 ;
      RECT 0.840 265.860 1831.900 266.140 ;
      RECT 0.840 270.340 1831.900 270.620 ;
      RECT 0.840 274.820 1831.900 275.100 ;
      RECT 0.840 279.300 1831.900 279.580 ;
      RECT 0.840 283.780 1831.900 284.060 ;
      RECT 0.840 288.260 1831.900 288.540 ;
      RECT 0.840 292.740 1831.900 293.020 ;
      RECT 0.840 297.220 1831.900 297.500 ;
      RECT 0.840 301.700 1831.900 301.980 ;
      RECT 0.840 306.180 1831.900 306.460 ;
      RECT 0.840 310.660 1831.900 310.940 ;
      RECT 0.840 315.140 1831.900 315.420 ;
      RECT 0.840 319.620 1831.900 319.900 ;
      RECT 0.840 324.100 1831.900 324.380 ;
      RECT 0.840 328.580 1831.900 328.860 ;
      RECT 0.840 333.060 1831.900 333.340 ;
      RECT 0.840 337.540 1831.900 337.820 ;
      RECT 0.840 342.020 1831.900 342.300 ;
      RECT 0.840 346.500 1831.900 346.780 ;
      RECT 0.840 350.980 1831.900 351.260 ;
      RECT 0.840 355.460 1831.900 355.740 ;
      RECT 0.840 359.940 1831.900 360.220 ;
      RECT 0.840 364.420 1831.900 364.700 ;
      RECT 0.840 368.900 1831.900 369.180 ;
      RECT 0.840 373.380 1831.900 373.660 ;
      RECT 0.840 377.860 1831.900 378.140 ;
      RECT 0.840 382.340 1831.900 382.620 ;
      RECT 0.840 386.820 1831.900 387.100 ;
      RECT 0.840 391.300 1831.900 391.580 ;
      RECT 0.840 395.780 1831.900 396.060 ;
      RECT 0.840 400.260 1831.900 400.540 ;
      RECT 0.840 404.740 1831.900 405.020 ;
      RECT 0.840 409.220 1831.900 409.500 ;
      RECT 0.840 413.700 1831.900 413.980 ;
      RECT 0.840 418.180 1831.900 418.460 ;
      RECT 0.840 422.660 1831.900 422.940 ;
      RECT 0.840 427.140 1831.900 427.420 ;
      RECT 0.840 431.620 1831.900 431.900 ;
      RECT 0.840 436.100 1831.900 436.380 ;
      RECT 0.840 440.580 1831.900 440.860 ;
      RECT 0.840 445.060 1831.900 445.340 ;
      RECT 0.840 449.540 1831.900 449.820 ;
      RECT 0.840 454.020 1831.900 454.300 ;
      RECT 0.840 458.500 1831.900 458.780 ;
      RECT 0.840 462.980 1831.900 463.260 ;
      RECT 0.840 467.460 1831.900 467.740 ;
      RECT 0.840 471.940 1831.900 472.220 ;
      RECT 0.840 476.420 1831.900 476.700 ;
      RECT 0.840 480.900 1831.900 481.180 ;
      RECT 0.840 485.380 1831.900 485.660 ;
      RECT 0.840 489.860 1831.900 490.140 ;
      RECT 0.840 494.340 1831.900 494.620 ;
      RECT 0.840 498.820 1831.900 499.100 ;
      RECT 0.840 503.300 1831.900 503.580 ;
      RECT 0.840 507.780 1831.900 508.060 ;
      RECT 0.840 512.260 1831.900 512.540 ;
      RECT 0.840 516.740 1831.900 517.020 ;
      RECT 0.840 521.220 1831.900 521.500 ;
      RECT 0.840 525.700 1831.900 525.980 ;
      RECT 0.840 530.180 1831.900 530.460 ;
      RECT 0.840 534.660 1831.900 534.940 ;
      RECT 0.840 539.140 1831.900 539.420 ;
      RECT 0.840 543.620 1831.900 543.900 ;
      RECT 0.840 548.100 1831.900 548.380 ;
      RECT 0.840 552.580 1831.900 552.860 ;
      RECT 0.840 557.060 1831.900 557.340 ;
      RECT 0.840 561.540 1831.900 561.820 ;
      RECT 0.840 566.020 1831.900 566.300 ;
      RECT 0.840 570.500 1831.900 570.780 ;
      RECT 0.840 574.980 1831.900 575.260 ;
      RECT 0.840 579.460 1831.900 579.740 ;
      RECT 0.840 583.940 1831.900 584.220 ;
      RECT 0.840 588.420 1831.900 588.700 ;
      RECT 0.840 592.900 1831.900 593.180 ;
      RECT 0.840 597.380 1831.900 597.660 ;
      RECT 0.840 601.860 1831.900 602.140 ;
      RECT 0.840 606.340 1831.900 606.620 ;
      RECT 0.840 610.820 1831.900 611.100 ;
      RECT 0.840 615.300 1831.900 615.580 ;
      RECT 0.840 619.780 1831.900 620.060 ;
      RECT 0.840 624.260 1831.900 624.540 ;
      RECT 0.840 628.740 1831.900 629.020 ;
      RECT 0.840 633.220 1831.900 633.500 ;
      RECT 0.840 637.700 1831.900 637.980 ;
      RECT 0.840 642.180 1831.900 642.460 ;
      RECT 0.840 646.660 1831.900 646.940 ;
      RECT 0.840 651.140 1831.900 651.420 ;
      RECT 0.840 655.620 1831.900 655.900 ;
      RECT 0.840 660.100 1831.900 660.380 ;
      RECT 0.840 664.580 1831.900 664.860 ;
      RECT 0.840 669.060 1831.900 669.340 ;
      RECT 0.840 673.540 1831.900 673.820 ;
      RECT 0.840 678.020 1831.900 678.300 ;
      RECT 0.840 682.500 1831.900 682.780 ;
      RECT 0.840 686.980 1831.900 687.260 ;
      RECT 0.840 691.460 1831.900 691.740 ;
      RECT 0.840 695.940 1831.900 696.220 ;
      RECT 0.840 700.420 1831.900 700.700 ;
      RECT 0.840 704.900 1831.900 705.180 ;
      RECT 0.840 709.380 1831.900 709.660 ;
      RECT 0.840 713.860 1831.900 714.140 ;
      RECT 0.840 718.340 1831.900 718.620 ;
      RECT 0.840 722.820 1831.900 723.100 ;
      RECT 0.840 727.300 1831.900 727.580 ;
      RECT 0.840 731.780 1831.900 732.060 ;
      RECT 0.840 736.260 1831.900 736.540 ;
      RECT 0.840 740.740 1831.900 741.020 ;
      RECT 0.840 745.220 1831.900 745.500 ;
      RECT 0.840 749.700 1831.900 749.980 ;
      RECT 0.840 754.180 1831.900 754.460 ;
      RECT 0.840 758.660 1831.900 758.940 ;
      RECT 0.840 763.140 1831.900 763.420 ;
      RECT 0.840 767.620 1831.900 767.900 ;
      RECT 0.840 772.100 1831.900 772.380 ;
      RECT 0.840 776.580 1831.900 776.860 ;
      RECT 0.840 781.060 1831.900 781.340 ;
      RECT 0.840 785.540 1831.900 785.820 ;
      RECT 0.840 790.020 1831.900 790.300 ;
      RECT 0.840 794.500 1831.900 794.780 ;
      RECT 0.840 798.980 1831.900 799.260 ;
      RECT 0.840 803.460 1831.900 803.740 ;
      RECT 0.840 807.940 1831.900 808.220 ;
      RECT 0.840 812.420 1831.900 812.700 ;
      RECT 0.840 816.900 1831.900 817.180 ;
      RECT 0.840 821.380 1831.900 821.660 ;
      RECT 0.840 825.860 1831.900 826.140 ;
      RECT 0.840 830.340 1831.900 830.620 ;
      RECT 0.840 834.820 1831.900 835.100 ;
      RECT 0.840 839.300 1831.900 839.580 ;
      RECT 0.840 843.780 1831.900 844.060 ;
      RECT 0.840 848.260 1831.900 848.540 ;
      RECT 0.840 852.740 1831.900 853.020 ;
      RECT 0.840 857.220 1831.900 857.500 ;
      RECT 0.840 861.700 1831.900 861.980 ;
      RECT 0.840 866.180 1831.900 866.460 ;
      RECT 0.840 870.660 1831.900 870.940 ;
      RECT 0.840 875.140 1831.900 875.420 ;
      RECT 0.840 879.620 1831.900 879.900 ;
      RECT 0.840 884.100 1831.900 884.380 ;
      RECT 0.840 888.580 1831.900 888.860 ;
      RECT 0.840 893.060 1831.900 893.340 ;
      RECT 0.840 897.540 1831.900 897.820 ;
      RECT 0.840 902.020 1831.900 902.300 ;
      RECT 0.840 906.500 1831.900 906.780 ;
      RECT 0.840 910.980 1831.900 911.260 ;
      RECT 0.840 915.460 1831.900 915.740 ;
      RECT 0.840 919.940 1831.900 920.220 ;
      RECT 0.840 924.420 1831.900 924.700 ;
      RECT 0.840 928.900 1831.900 929.180 ;
      RECT 0.840 933.380 1831.900 933.660 ;
      RECT 0.840 937.860 1831.900 938.140 ;
      RECT 0.840 942.340 1831.900 942.620 ;
      RECT 0.840 946.820 1831.900 947.100 ;
      RECT 0.840 951.300 1831.900 951.580 ;
      RECT 0.840 955.780 1831.900 956.060 ;
      RECT 0.840 960.260 1831.900 960.540 ;
      RECT 0.840 964.740 1831.900 965.020 ;
      RECT 0.840 969.220 1831.900 969.500 ;
      RECT 0.840 973.700 1831.900 973.980 ;
      RECT 0.840 978.180 1831.900 978.460 ;
    END
  END VDD
  OBS
    LAYER metal1 ;
    RECT 0 0 1832.740 981.400 ;
    LAYER metal2 ;
    RECT 0 0 1832.740 981.400 ;
    LAYER metal3 ;
    RECT 0 0 1832.740 981.400 ;
    LAYER metal4 ;
    RECT 0 0 1832.740 981.400 ;
    LAYER OVERLAP ;
    RECT 0 0 1832.740 981.400 ;
  END
END fakeram_512x1024_1r1w

END LIBRARY
